VERSION 5.8 ;
BUSBITCHARS "[]" ;
DIVIDERCHAR "/" ;
UNITS
    DATABASE MICRONS 1000 ;
END UNITS

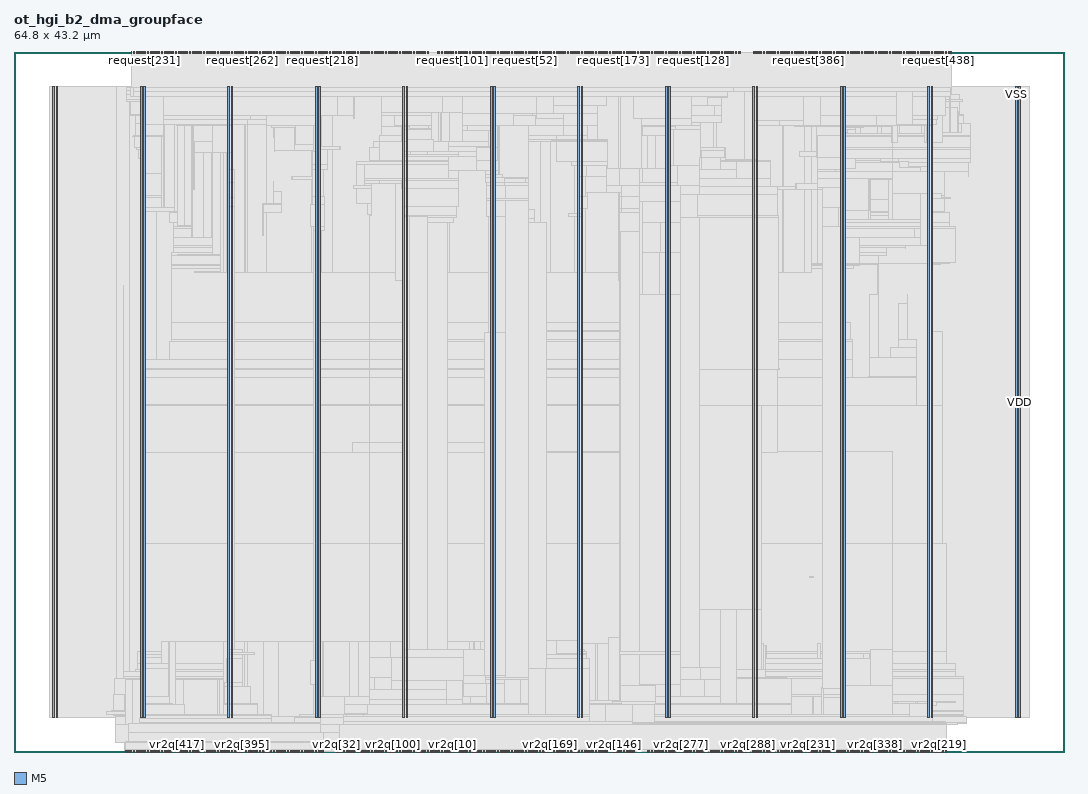
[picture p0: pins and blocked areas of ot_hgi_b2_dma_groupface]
MACRO ot_hgi_b2_dma_groupface
  FOREIGN ot_hgi_b2_dma_groupface 0 0 ;
  CLASS BLOCK ;
  SIZE 64.8 BY 43.2 ;
  PIN clk
    DIRECTION INPUT ;
    USE SIGNAL ;
    PORT
      LAYER M5 ;
        RECT  38.736 43.116 38.76 43.2 ;
    END
  END clk
  PIN request[0]
    DIRECTION INPUT ;
    USE SIGNAL ;
    PORT
      LAYER M5 ;
        RECT  38.832 43.116 38.856 43.2 ;
    END
  END request[0]
  PIN request[100]
    DIRECTION INPUT ;
    USE SIGNAL ;
    PORT
      LAYER M5 ;
        RECT  26.928 43.116 26.952 43.2 ;
    END
  END request[100]
  PIN request[101]
    DIRECTION INPUT ;
    USE SIGNAL ;
    PORT
      LAYER M5 ;
        RECT  27.024 43.116 27.048 43.2 ;
    END
  END request[101]
  PIN request[102]
    DIRECTION INPUT ;
    USE SIGNAL ;
    PORT
      LAYER M5 ;
        RECT  27.12 43.116 27.144 43.2 ;
    END
  END request[102]
  PIN request[103]
    DIRECTION INPUT ;
    USE SIGNAL ;
    PORT
      LAYER M5 ;
        RECT  27.216 43.116 27.24 43.2 ;
    END
  END request[103]
  PIN request[104]
    DIRECTION INPUT ;
    USE SIGNAL ;
    PORT
      LAYER M5 ;
        RECT  27.312 43.116 27.336 43.2 ;
    END
  END request[104]
  PIN request[105]
    DIRECTION INPUT ;
    USE SIGNAL ;
    PORT
      LAYER M5 ;
        RECT  27.408 43.116 27.432 43.2 ;
    END
  END request[105]
  PIN request[106]
    DIRECTION INPUT ;
    USE SIGNAL ;
    PORT
      LAYER M5 ;
        RECT  27.504 43.116 27.528 43.2 ;
    END
  END request[106]
  PIN request[107]
    DIRECTION INPUT ;
    USE SIGNAL ;
    PORT
      LAYER M5 ;
        RECT  27.6 43.116 27.624 43.2 ;
    END
  END request[107]
  PIN request[108]
    DIRECTION INPUT ;
    USE SIGNAL ;
    PORT
      LAYER M5 ;
        RECT  27.696 43.116 27.72 43.2 ;
    END
  END request[108]
  PIN request[109]
    DIRECTION INPUT ;
    USE SIGNAL ;
    PORT
      LAYER M5 ;
        RECT  27.792 43.116 27.816 43.2 ;
    END
  END request[109]
  PIN request[10]
    DIRECTION INPUT ;
    USE SIGNAL ;
    PORT
      LAYER M5 ;
        RECT  39.792 43.116 39.816 43.2 ;
    END
  END request[10]
  PIN request[110]
    DIRECTION INPUT ;
    USE SIGNAL ;
    PORT
      LAYER M5 ;
        RECT  27.888 43.116 27.912 43.2 ;
    END
  END request[110]
  PIN request[111]
    DIRECTION INPUT ;
    USE SIGNAL ;
    PORT
      LAYER M5 ;
        RECT  27.984 43.116 28.008 43.2 ;
    END
  END request[111]
  PIN request[112]
    DIRECTION INPUT ;
    USE SIGNAL ;
    PORT
      LAYER M5 ;
        RECT  28.08 43.116 28.104 43.2 ;
    END
  END request[112]
  PIN request[113]
    DIRECTION INPUT ;
    USE SIGNAL ;
    PORT
      LAYER M5 ;
        RECT  28.176 43.116 28.2 43.2 ;
    END
  END request[113]
  PIN request[114]
    DIRECTION INPUT ;
    USE SIGNAL ;
    PORT
      LAYER M5 ;
        RECT  28.272 43.116 28.296 43.2 ;
    END
  END request[114]
  PIN request[115]
    DIRECTION INPUT ;
    USE SIGNAL ;
    PORT
      LAYER M5 ;
        RECT  28.368 43.116 28.392 43.2 ;
    END
  END request[115]
  PIN request[116]
    DIRECTION INPUT ;
    USE SIGNAL ;
    PORT
      LAYER M5 ;
        RECT  28.464 43.116 28.488 43.2 ;
    END
  END request[116]
  PIN request[117]
    DIRECTION INPUT ;
    USE SIGNAL ;
    PORT
      LAYER M5 ;
        RECT  28.56 43.116 28.584 43.2 ;
    END
  END request[117]
  PIN request[118]
    DIRECTION INPUT ;
    USE SIGNAL ;
    PORT
      LAYER M5 ;
        RECT  28.656 43.116 28.68 43.2 ;
    END
  END request[118]
  PIN request[119]
    DIRECTION INPUT ;
    USE SIGNAL ;
    PORT
      LAYER M5 ;
        RECT  28.752 43.116 28.776 43.2 ;
    END
  END request[119]
  PIN request[11]
    DIRECTION INPUT ;
    USE SIGNAL ;
    PORT
      LAYER M5 ;
        RECT  39.888 43.116 39.912 43.2 ;
    END
  END request[11]
  PIN request[120]
    DIRECTION INPUT ;
    USE SIGNAL ;
    PORT
      LAYER M5 ;
        RECT  28.848 43.116 28.872 43.2 ;
    END
  END request[120]
  PIN request[121]
    DIRECTION INPUT ;
    USE SIGNAL ;
    PORT
      LAYER M5 ;
        RECT  28.944 43.116 28.968 43.2 ;
    END
  END request[121]
  PIN request[122]
    DIRECTION INPUT ;
    USE SIGNAL ;
    PORT
      LAYER M5 ;
        RECT  29.04 43.116 29.064 43.2 ;
    END
  END request[122]
  PIN request[123]
    DIRECTION INPUT ;
    USE SIGNAL ;
    PORT
      LAYER M5 ;
        RECT  29.136 43.116 29.16 43.2 ;
    END
  END request[123]
  PIN request[124]
    DIRECTION INPUT ;
    USE SIGNAL ;
    PORT
      LAYER M5 ;
        RECT  29.232 43.116 29.256 43.2 ;
    END
  END request[124]
  PIN request[125]
    DIRECTION INPUT ;
    USE SIGNAL ;
    PORT
      LAYER M5 ;
        RECT  29.328 43.116 29.352 43.2 ;
    END
  END request[125]
  PIN request[126]
    DIRECTION INPUT ;
    USE SIGNAL ;
    PORT
      LAYER M5 ;
        RECT  29.424 43.116 29.448 43.2 ;
    END
  END request[126]
  PIN request[127]
    DIRECTION INPUT ;
    USE SIGNAL ;
    PORT
      LAYER M5 ;
        RECT  41.808 43.116 41.832 43.2 ;
    END
  END request[127]
  PIN request[128]
    DIRECTION INPUT ;
    USE SIGNAL ;
    PORT
      LAYER M5 ;
        RECT  41.904 43.116 41.928 43.2 ;
    END
  END request[128]
  PIN request[129]
    DIRECTION INPUT ;
    USE SIGNAL ;
    PORT
      LAYER M5 ;
        RECT  42 43.116 42.024 43.2 ;
    END
  END request[129]
  PIN request[12]
    DIRECTION INPUT ;
    USE SIGNAL ;
    PORT
      LAYER M5 ;
        RECT  39.984 43.116 40.008 43.2 ;
    END
  END request[12]
  PIN request[130]
    DIRECTION INPUT ;
    USE SIGNAL ;
    PORT
      LAYER M5 ;
        RECT  42.096 43.116 42.12 43.2 ;
    END
  END request[130]
  PIN request[131]
    DIRECTION INPUT ;
    USE SIGNAL ;
    PORT
      LAYER M5 ;
        RECT  42.192 43.116 42.216 43.2 ;
    END
  END request[131]
  PIN request[132]
    DIRECTION INPUT ;
    USE SIGNAL ;
    PORT
      LAYER M5 ;
        RECT  42.288 43.116 42.312 43.2 ;
    END
  END request[132]
  PIN request[133]
    DIRECTION INPUT ;
    USE SIGNAL ;
    PORT
      LAYER M5 ;
        RECT  42.384 43.116 42.408 43.2 ;
    END
  END request[133]
  PIN request[134]
    DIRECTION INPUT ;
    USE SIGNAL ;
    PORT
      LAYER M5 ;
        RECT  42.48 43.116 42.504 43.2 ;
    END
  END request[134]
  PIN request[135]
    DIRECTION INPUT ;
    USE SIGNAL ;
    PORT
      LAYER M5 ;
        RECT  42.576 43.116 42.6 43.2 ;
    END
  END request[135]
  PIN request[136]
    DIRECTION INPUT ;
    USE SIGNAL ;
    PORT
      LAYER M5 ;
        RECT  42.672 43.116 42.696 43.2 ;
    END
  END request[136]
  PIN request[137]
    DIRECTION INPUT ;
    USE SIGNAL ;
    PORT
      LAYER M5 ;
        RECT  42.768 43.116 42.792 43.2 ;
    END
  END request[137]
  PIN request[138]
    DIRECTION INPUT ;
    USE SIGNAL ;
    PORT
      LAYER M5 ;
        RECT  42.864 43.116 42.888 43.2 ;
    END
  END request[138]
  PIN request[139]
    DIRECTION INPUT ;
    USE SIGNAL ;
    PORT
      LAYER M5 ;
        RECT  42.96 43.116 42.984 43.2 ;
    END
  END request[139]
  PIN request[13]
    DIRECTION INPUT ;
    USE SIGNAL ;
    PORT
      LAYER M5 ;
        RECT  40.08 43.116 40.104 43.2 ;
    END
  END request[13]
  PIN request[140]
    DIRECTION INPUT ;
    USE SIGNAL ;
    PORT
      LAYER M5 ;
        RECT  43.056 43.116 43.08 43.2 ;
    END
  END request[140]
  PIN request[141]
    DIRECTION INPUT ;
    USE SIGNAL ;
    PORT
      LAYER M5 ;
        RECT  43.152 43.116 43.176 43.2 ;
    END
  END request[141]
  PIN request[142]
    DIRECTION INPUT ;
    USE SIGNAL ;
    PORT
      LAYER M5 ;
        RECT  43.248 43.116 43.272 43.2 ;
    END
  END request[142]
  PIN request[143]
    DIRECTION INPUT ;
    USE SIGNAL ;
    PORT
      LAYER M5 ;
        RECT  43.344 43.116 43.368 43.2 ;
    END
  END request[143]
  PIN request[144]
    DIRECTION INPUT ;
    USE SIGNAL ;
    PORT
      LAYER M5 ;
        RECT  43.44 43.116 43.464 43.2 ;
    END
  END request[144]
  PIN request[145]
    DIRECTION INPUT ;
    USE SIGNAL ;
    PORT
      LAYER M5 ;
        RECT  43.536 43.116 43.56 43.2 ;
    END
  END request[145]
  PIN request[146]
    DIRECTION INPUT ;
    USE SIGNAL ;
    PORT
      LAYER M5 ;
        RECT  43.632 43.116 43.656 43.2 ;
    END
  END request[146]
  PIN request[147]
    DIRECTION INPUT ;
    USE SIGNAL ;
    PORT
      LAYER M5 ;
        RECT  43.728 43.116 43.752 43.2 ;
    END
  END request[147]
  PIN request[148]
    DIRECTION INPUT ;
    USE SIGNAL ;
    PORT
      LAYER M5 ;
        RECT  43.824 43.116 43.848 43.2 ;
    END
  END request[148]
  PIN request[149]
    DIRECTION INPUT ;
    USE SIGNAL ;
    PORT
      LAYER M5 ;
        RECT  43.92 43.116 43.944 43.2 ;
    END
  END request[149]
  PIN request[14]
    DIRECTION INPUT ;
    USE SIGNAL ;
    PORT
      LAYER M5 ;
        RECT  40.176 43.116 40.2 43.2 ;
    END
  END request[14]
  PIN request[150]
    DIRECTION INPUT ;
    USE SIGNAL ;
    PORT
      LAYER M5 ;
        RECT  44.016 43.116 44.04 43.2 ;
    END
  END request[150]
  PIN request[151]
    DIRECTION INPUT ;
    USE SIGNAL ;
    PORT
      LAYER M5 ;
        RECT  44.112 43.116 44.136 43.2 ;
    END
  END request[151]
  PIN request[152]
    DIRECTION INPUT ;
    USE SIGNAL ;
    PORT
      LAYER M5 ;
        RECT  44.208 43.116 44.232 43.2 ;
    END
  END request[152]
  PIN request[153]
    DIRECTION INPUT ;
    USE SIGNAL ;
    PORT
      LAYER M5 ;
        RECT  44.304 43.116 44.328 43.2 ;
    END
  END request[153]
  PIN request[154]
    DIRECTION INPUT ;
    USE SIGNAL ;
    PORT
      LAYER M5 ;
        RECT  44.4 43.116 44.424 43.2 ;
    END
  END request[154]
  PIN request[155]
    DIRECTION INPUT ;
    USE SIGNAL ;
    PORT
      LAYER M5 ;
        RECT  44.496 43.116 44.52 43.2 ;
    END
  END request[155]
  PIN request[156]
    DIRECTION INPUT ;
    USE SIGNAL ;
    PORT
      LAYER M5 ;
        RECT  44.592 43.116 44.616 43.2 ;
    END
  END request[156]
  PIN request[157]
    DIRECTION INPUT ;
    USE SIGNAL ;
    PORT
      LAYER M5 ;
        RECT  44.688 43.116 44.712 43.2 ;
    END
  END request[157]
  PIN request[158]
    DIRECTION INPUT ;
    USE SIGNAL ;
    PORT
      LAYER M5 ;
        RECT  44.784 43.116 44.808 43.2 ;
    END
  END request[158]
  PIN request[159]
    DIRECTION INPUT ;
    USE SIGNAL ;
    PORT
      LAYER M5 ;
        RECT  35.664 43.116 35.688 43.2 ;
    END
  END request[159]
  PIN request[15]
    DIRECTION INPUT ;
    USE SIGNAL ;
    PORT
      LAYER M5 ;
        RECT  40.272 43.116 40.296 43.2 ;
    END
  END request[15]
  PIN request[160]
    DIRECTION INPUT ;
    USE SIGNAL ;
    PORT
      LAYER M5 ;
        RECT  35.76 43.116 35.784 43.2 ;
    END
  END request[160]
  PIN request[161]
    DIRECTION INPUT ;
    USE SIGNAL ;
    PORT
      LAYER M5 ;
        RECT  35.856 43.116 35.88 43.2 ;
    END
  END request[161]
  PIN request[162]
    DIRECTION INPUT ;
    USE SIGNAL ;
    PORT
      LAYER M5 ;
        RECT  35.952 43.116 35.976 43.2 ;
    END
  END request[162]
  PIN request[163]
    DIRECTION INPUT ;
    USE SIGNAL ;
    PORT
      LAYER M5 ;
        RECT  36.048 43.116 36.072 43.2 ;
    END
  END request[163]
  PIN request[164]
    DIRECTION INPUT ;
    USE SIGNAL ;
    PORT
      LAYER M5 ;
        RECT  36.144 43.116 36.168 43.2 ;
    END
  END request[164]
  PIN request[165]
    DIRECTION INPUT ;
    USE SIGNAL ;
    PORT
      LAYER M5 ;
        RECT  36.24 43.116 36.264 43.2 ;
    END
  END request[165]
  PIN request[166]
    DIRECTION INPUT ;
    USE SIGNAL ;
    PORT
      LAYER M5 ;
        RECT  36.336 43.116 36.36 43.2 ;
    END
  END request[166]
  PIN request[167]
    DIRECTION INPUT ;
    USE SIGNAL ;
    PORT
      LAYER M5 ;
        RECT  36.432 43.116 36.456 43.2 ;
    END
  END request[167]
  PIN request[168]
    DIRECTION INPUT ;
    USE SIGNAL ;
    PORT
      LAYER M5 ;
        RECT  36.528 43.116 36.552 43.2 ;
    END
  END request[168]
  PIN request[169]
    DIRECTION INPUT ;
    USE SIGNAL ;
    PORT
      LAYER M5 ;
        RECT  36.624 43.116 36.648 43.2 ;
    END
  END request[169]
  PIN request[16]
    DIRECTION INPUT ;
    USE SIGNAL ;
    PORT
      LAYER M5 ;
        RECT  40.368 43.116 40.392 43.2 ;
    END
  END request[16]
  PIN request[170]
    DIRECTION INPUT ;
    USE SIGNAL ;
    PORT
      LAYER M5 ;
        RECT  36.72 43.116 36.744 43.2 ;
    END
  END request[170]
  PIN request[171]
    DIRECTION INPUT ;
    USE SIGNAL ;
    PORT
      LAYER M5 ;
        RECT  36.816 43.116 36.84 43.2 ;
    END
  END request[171]
  PIN request[172]
    DIRECTION INPUT ;
    USE SIGNAL ;
    PORT
      LAYER M5 ;
        RECT  36.912 43.116 36.936 43.2 ;
    END
  END request[172]
  PIN request[173]
    DIRECTION INPUT ;
    USE SIGNAL ;
    PORT
      LAYER M5 ;
        RECT  37.008 43.116 37.032 43.2 ;
    END
  END request[173]
  PIN request[174]
    DIRECTION INPUT ;
    USE SIGNAL ;
    PORT
      LAYER M5 ;
        RECT  37.104 43.116 37.128 43.2 ;
    END
  END request[174]
  PIN request[175]
    DIRECTION INPUT ;
    USE SIGNAL ;
    PORT
      LAYER M5 ;
        RECT  37.2 43.116 37.224 43.2 ;
    END
  END request[175]
  PIN request[176]
    DIRECTION INPUT ;
    USE SIGNAL ;
    PORT
      LAYER M5 ;
        RECT  37.296 43.116 37.32 43.2 ;
    END
  END request[176]
  PIN request[177]
    DIRECTION INPUT ;
    USE SIGNAL ;
    PORT
      LAYER M5 ;
        RECT  37.392 43.116 37.416 43.2 ;
    END
  END request[177]
  PIN request[178]
    DIRECTION INPUT ;
    USE SIGNAL ;
    PORT
      LAYER M5 ;
        RECT  37.488 43.116 37.512 43.2 ;
    END
  END request[178]
  PIN request[179]
    DIRECTION INPUT ;
    USE SIGNAL ;
    PORT
      LAYER M5 ;
        RECT  37.584 43.116 37.608 43.2 ;
    END
  END request[179]
  PIN request[17]
    DIRECTION INPUT ;
    USE SIGNAL ;
    PORT
      LAYER M5 ;
        RECT  40.464 43.116 40.488 43.2 ;
    END
  END request[17]
  PIN request[180]
    DIRECTION INPUT ;
    USE SIGNAL ;
    PORT
      LAYER M5 ;
        RECT  37.68 43.116 37.704 43.2 ;
    END
  END request[180]
  PIN request[181]
    DIRECTION INPUT ;
    USE SIGNAL ;
    PORT
      LAYER M5 ;
        RECT  37.776 43.116 37.8 43.2 ;
    END
  END request[181]
  PIN request[182]
    DIRECTION INPUT ;
    USE SIGNAL ;
    PORT
      LAYER M5 ;
        RECT  37.872 43.116 37.896 43.2 ;
    END
  END request[182]
  PIN request[183]
    DIRECTION INPUT ;
    USE SIGNAL ;
    PORT
      LAYER M5 ;
        RECT  37.968 43.116 37.992 43.2 ;
    END
  END request[183]
  PIN request[184]
    DIRECTION INPUT ;
    USE SIGNAL ;
    PORT
      LAYER M5 ;
        RECT  38.064 43.116 38.088 43.2 ;
    END
  END request[184]
  PIN request[185]
    DIRECTION INPUT ;
    USE SIGNAL ;
    PORT
      LAYER M5 ;
        RECT  38.16 43.116 38.184 43.2 ;
    END
  END request[185]
  PIN request[186]
    DIRECTION INPUT ;
    USE SIGNAL ;
    PORT
      LAYER M5 ;
        RECT  38.256 43.116 38.28 43.2 ;
    END
  END request[186]
  PIN request[187]
    DIRECTION INPUT ;
    USE SIGNAL ;
    PORT
      LAYER M5 ;
        RECT  38.352 43.116 38.376 43.2 ;
    END
  END request[187]
  PIN request[188]
    DIRECTION INPUT ;
    USE SIGNAL ;
    PORT
      LAYER M5 ;
        RECT  38.448 43.116 38.472 43.2 ;
    END
  END request[188]
  PIN request[189]
    DIRECTION INPUT ;
    USE SIGNAL ;
    PORT
      LAYER M5 ;
        RECT  38.544 43.116 38.568 43.2 ;
    END
  END request[189]
  PIN request[18]
    DIRECTION INPUT ;
    USE SIGNAL ;
    PORT
      LAYER M5 ;
        RECT  40.56 43.116 40.584 43.2 ;
    END
  END request[18]
  PIN request[190]
    DIRECTION INPUT ;
    USE SIGNAL ;
    PORT
      LAYER M5 ;
        RECT  38.64 43.116 38.664 43.2 ;
    END
  END request[190]
  PIN request[191]
    DIRECTION INPUT ;
    USE SIGNAL ;
    PORT
      LAYER M5 ;
        RECT  16.464 43.116 16.488 43.2 ;
    END
  END request[191]
  PIN request[192]
    DIRECTION INPUT ;
    USE SIGNAL ;
    PORT
      LAYER M5 ;
        RECT  16.56 43.116 16.584 43.2 ;
    END
  END request[192]
  PIN request[193]
    DIRECTION INPUT ;
    USE SIGNAL ;
    PORT
      LAYER M5 ;
        RECT  16.656 43.116 16.68 43.2 ;
    END
  END request[193]
  PIN request[194]
    DIRECTION INPUT ;
    USE SIGNAL ;
    PORT
      LAYER M5 ;
        RECT  16.752 43.116 16.776 43.2 ;
    END
  END request[194]
  PIN request[195]
    DIRECTION INPUT ;
    USE SIGNAL ;
    PORT
      LAYER M5 ;
        RECT  16.848 43.116 16.872 43.2 ;
    END
  END request[195]
  PIN request[196]
    DIRECTION INPUT ;
    USE SIGNAL ;
    PORT
      LAYER M5 ;
        RECT  16.944 43.116 16.968 43.2 ;
    END
  END request[196]
  PIN request[197]
    DIRECTION INPUT ;
    USE SIGNAL ;
    PORT
      LAYER M5 ;
        RECT  17.04 43.116 17.064 43.2 ;
    END
  END request[197]
  PIN request[198]
    DIRECTION INPUT ;
    USE SIGNAL ;
    PORT
      LAYER M5 ;
        RECT  17.136 43.116 17.16 43.2 ;
    END
  END request[198]
  PIN request[199]
    DIRECTION INPUT ;
    USE SIGNAL ;
    PORT
      LAYER M5 ;
        RECT  17.232 43.116 17.256 43.2 ;
    END
  END request[199]
  PIN request[19]
    DIRECTION INPUT ;
    USE SIGNAL ;
    PORT
      LAYER M5 ;
        RECT  40.656 43.116 40.68 43.2 ;
    END
  END request[19]
  PIN request[1]
    DIRECTION INPUT ;
    USE SIGNAL ;
    PORT
      LAYER M5 ;
        RECT  38.928 43.116 38.952 43.2 ;
    END
  END request[1]
  PIN request[200]
    DIRECTION INPUT ;
    USE SIGNAL ;
    PORT
      LAYER M5 ;
        RECT  17.328 43.116 17.352 43.2 ;
    END
  END request[200]
  PIN request[201]
    DIRECTION INPUT ;
    USE SIGNAL ;
    PORT
      LAYER M5 ;
        RECT  17.424 43.116 17.448 43.2 ;
    END
  END request[201]
  PIN request[202]
    DIRECTION INPUT ;
    USE SIGNAL ;
    PORT
      LAYER M5 ;
        RECT  17.52 43.116 17.544 43.2 ;
    END
  END request[202]
  PIN request[203]
    DIRECTION INPUT ;
    USE SIGNAL ;
    PORT
      LAYER M5 ;
        RECT  17.616 43.116 17.64 43.2 ;
    END
  END request[203]
  PIN request[204]
    DIRECTION INPUT ;
    USE SIGNAL ;
    PORT
      LAYER M5 ;
        RECT  17.712 43.116 17.736 43.2 ;
    END
  END request[204]
  PIN request[205]
    DIRECTION INPUT ;
    USE SIGNAL ;
    PORT
      LAYER M5 ;
        RECT  17.808 43.116 17.832 43.2 ;
    END
  END request[205]
  PIN request[206]
    DIRECTION INPUT ;
    USE SIGNAL ;
    PORT
      LAYER M5 ;
        RECT  17.904 43.116 17.928 43.2 ;
    END
  END request[206]
  PIN request[207]
    DIRECTION INPUT ;
    USE SIGNAL ;
    PORT
      LAYER M5 ;
        RECT  18 43.116 18.024 43.2 ;
    END
  END request[207]
  PIN request[208]
    DIRECTION INPUT ;
    USE SIGNAL ;
    PORT
      LAYER M5 ;
        RECT  18.096 43.116 18.12 43.2 ;
    END
  END request[208]
  PIN request[209]
    DIRECTION INPUT ;
    USE SIGNAL ;
    PORT
      LAYER M5 ;
        RECT  18.192 43.116 18.216 43.2 ;
    END
  END request[209]
  PIN request[20]
    DIRECTION INPUT ;
    USE SIGNAL ;
    PORT
      LAYER M5 ;
        RECT  40.752 43.116 40.776 43.2 ;
    END
  END request[20]
  PIN request[210]
    DIRECTION INPUT ;
    USE SIGNAL ;
    PORT
      LAYER M5 ;
        RECT  18.288 43.116 18.312 43.2 ;
    END
  END request[210]
  PIN request[211]
    DIRECTION INPUT ;
    USE SIGNAL ;
    PORT
      LAYER M5 ;
        RECT  18.384 43.116 18.408 43.2 ;
    END
  END request[211]
  PIN request[212]
    DIRECTION INPUT ;
    USE SIGNAL ;
    PORT
      LAYER M5 ;
        RECT  18.48 43.116 18.504 43.2 ;
    END
  END request[212]
  PIN request[213]
    DIRECTION INPUT ;
    USE SIGNAL ;
    PORT
      LAYER M5 ;
        RECT  18.576 43.116 18.6 43.2 ;
    END
  END request[213]
  PIN request[214]
    DIRECTION INPUT ;
    USE SIGNAL ;
    PORT
      LAYER M5 ;
        RECT  18.672 43.116 18.696 43.2 ;
    END
  END request[214]
  PIN request[215]
    DIRECTION INPUT ;
    USE SIGNAL ;
    PORT
      LAYER M5 ;
        RECT  18.768 43.116 18.792 43.2 ;
    END
  END request[215]
  PIN request[216]
    DIRECTION INPUT ;
    USE SIGNAL ;
    PORT
      LAYER M5 ;
        RECT  18.864 43.116 18.888 43.2 ;
    END
  END request[216]
  PIN request[217]
    DIRECTION INPUT ;
    USE SIGNAL ;
    PORT
      LAYER M5 ;
        RECT  18.96 43.116 18.984 43.2 ;
    END
  END request[217]
  PIN request[218]
    DIRECTION INPUT ;
    USE SIGNAL ;
    PORT
      LAYER M5 ;
        RECT  19.056 43.116 19.08 43.2 ;
    END
  END request[218]
  PIN request[219]
    DIRECTION INPUT ;
    USE SIGNAL ;
    PORT
      LAYER M5 ;
        RECT  19.152 43.116 19.176 43.2 ;
    END
  END request[219]
  PIN request[21]
    DIRECTION INPUT ;
    USE SIGNAL ;
    PORT
      LAYER M5 ;
        RECT  40.848 43.116 40.872 43.2 ;
    END
  END request[21]
  PIN request[220]
    DIRECTION INPUT ;
    USE SIGNAL ;
    PORT
      LAYER M5 ;
        RECT  19.248 43.116 19.272 43.2 ;
    END
  END request[220]
  PIN request[221]
    DIRECTION INPUT ;
    USE SIGNAL ;
    PORT
      LAYER M5 ;
        RECT  19.344 43.116 19.368 43.2 ;
    END
  END request[221]
  PIN request[222]
    DIRECTION INPUT ;
    USE SIGNAL ;
    PORT
      LAYER M5 ;
        RECT  19.44 43.116 19.464 43.2 ;
    END
  END request[222]
  PIN request[223]
    DIRECTION INPUT ;
    USE SIGNAL ;
    PORT
      LAYER M5 ;
        RECT  7.248 43.116 7.272 43.2 ;
    END
  END request[223]
  PIN request[224]
    DIRECTION INPUT ;
    USE SIGNAL ;
    PORT
      LAYER M5 ;
        RECT  7.344 43.116 7.368 43.2 ;
    END
  END request[224]
  PIN request[225]
    DIRECTION INPUT ;
    USE SIGNAL ;
    PORT
      LAYER M5 ;
        RECT  7.44 43.116 7.464 43.2 ;
    END
  END request[225]
  PIN request[226]
    DIRECTION INPUT ;
    USE SIGNAL ;
    PORT
      LAYER M5 ;
        RECT  7.536 43.116 7.56 43.2 ;
    END
  END request[226]
  PIN request[227]
    DIRECTION INPUT ;
    USE SIGNAL ;
    PORT
      LAYER M5 ;
        RECT  7.632 43.116 7.656 43.2 ;
    END
  END request[227]
  PIN request[228]
    DIRECTION INPUT ;
    USE SIGNAL ;
    PORT
      LAYER M5 ;
        RECT  7.728 43.116 7.752 43.2 ;
    END
  END request[228]
  PIN request[229]
    DIRECTION INPUT ;
    USE SIGNAL ;
    PORT
      LAYER M5 ;
        RECT  7.824 43.116 7.848 43.2 ;
    END
  END request[229]
  PIN request[22]
    DIRECTION INPUT ;
    USE SIGNAL ;
    PORT
      LAYER M5 ;
        RECT  40.944 43.116 40.968 43.2 ;
    END
  END request[22]
  PIN request[230]
    DIRECTION INPUT ;
    USE SIGNAL ;
    PORT
      LAYER M5 ;
        RECT  7.92 43.116 7.944 43.2 ;
    END
  END request[230]
  PIN request[231]
    DIRECTION INPUT ;
    USE SIGNAL ;
    PORT
      LAYER M5 ;
        RECT  8.016 43.116 8.04 43.2 ;
    END
  END request[231]
  PIN request[232]
    DIRECTION INPUT ;
    USE SIGNAL ;
    PORT
      LAYER M5 ;
        RECT  8.112 43.116 8.136 43.2 ;
    END
  END request[232]
  PIN request[233]
    DIRECTION INPUT ;
    USE SIGNAL ;
    PORT
      LAYER M5 ;
        RECT  8.208 43.116 8.232 43.2 ;
    END
  END request[233]
  PIN request[234]
    DIRECTION INPUT ;
    USE SIGNAL ;
    PORT
      LAYER M5 ;
        RECT  8.304 43.116 8.328 43.2 ;
    END
  END request[234]
  PIN request[235]
    DIRECTION INPUT ;
    USE SIGNAL ;
    PORT
      LAYER M5 ;
        RECT  8.4 43.116 8.424 43.2 ;
    END
  END request[235]
  PIN request[236]
    DIRECTION INPUT ;
    USE SIGNAL ;
    PORT
      LAYER M5 ;
        RECT  8.496 43.116 8.52 43.2 ;
    END
  END request[236]
  PIN request[237]
    DIRECTION INPUT ;
    USE SIGNAL ;
    PORT
      LAYER M5 ;
        RECT  8.592 43.116 8.616 43.2 ;
    END
  END request[237]
  PIN request[238]
    DIRECTION INPUT ;
    USE SIGNAL ;
    PORT
      LAYER M5 ;
        RECT  8.688 43.116 8.712 43.2 ;
    END
  END request[238]
  PIN request[239]
    DIRECTION INPUT ;
    USE SIGNAL ;
    PORT
      LAYER M5 ;
        RECT  8.784 43.116 8.808 43.2 ;
    END
  END request[239]
  PIN request[23]
    DIRECTION INPUT ;
    USE SIGNAL ;
    PORT
      LAYER M5 ;
        RECT  41.04 43.116 41.064 43.2 ;
    END
  END request[23]
  PIN request[240]
    DIRECTION INPUT ;
    USE SIGNAL ;
    PORT
      LAYER M5 ;
        RECT  8.88 43.116 8.904 43.2 ;
    END
  END request[240]
  PIN request[241]
    DIRECTION INPUT ;
    USE SIGNAL ;
    PORT
      LAYER M5 ;
        RECT  8.976 43.116 9 43.2 ;
    END
  END request[241]
  PIN request[242]
    DIRECTION INPUT ;
    USE SIGNAL ;
    PORT
      LAYER M5 ;
        RECT  9.072 43.116 9.096 43.2 ;
    END
  END request[242]
  PIN request[243]
    DIRECTION INPUT ;
    USE SIGNAL ;
    PORT
      LAYER M5 ;
        RECT  9.168 43.116 9.192 43.2 ;
    END
  END request[243]
  PIN request[244]
    DIRECTION INPUT ;
    USE SIGNAL ;
    PORT
      LAYER M5 ;
        RECT  9.264 43.116 9.288 43.2 ;
    END
  END request[244]
  PIN request[245]
    DIRECTION INPUT ;
    USE SIGNAL ;
    PORT
      LAYER M5 ;
        RECT  9.36 43.116 9.384 43.2 ;
    END
  END request[245]
  PIN request[246]
    DIRECTION INPUT ;
    USE SIGNAL ;
    PORT
      LAYER M5 ;
        RECT  9.456 43.116 9.48 43.2 ;
    END
  END request[246]
  PIN request[247]
    DIRECTION INPUT ;
    USE SIGNAL ;
    PORT
      LAYER M5 ;
        RECT  9.552 43.116 9.576 43.2 ;
    END
  END request[247]
  PIN request[248]
    DIRECTION INPUT ;
    USE SIGNAL ;
    PORT
      LAYER M5 ;
        RECT  9.648 43.116 9.672 43.2 ;
    END
  END request[248]
  PIN request[249]
    DIRECTION INPUT ;
    USE SIGNAL ;
    PORT
      LAYER M5 ;
        RECT  9.744 43.116 9.768 43.2 ;
    END
  END request[249]
  PIN request[24]
    DIRECTION INPUT ;
    USE SIGNAL ;
    PORT
      LAYER M5 ;
        RECT  41.136 43.116 41.16 43.2 ;
    END
  END request[24]
  PIN request[250]
    DIRECTION INPUT ;
    USE SIGNAL ;
    PORT
      LAYER M5 ;
        RECT  9.84 43.116 9.864 43.2 ;
    END
  END request[250]
  PIN request[251]
    DIRECTION INPUT ;
    USE SIGNAL ;
    PORT
      LAYER M5 ;
        RECT  9.936 43.116 9.96 43.2 ;
    END
  END request[251]
  PIN request[252]
    DIRECTION INPUT ;
    USE SIGNAL ;
    PORT
      LAYER M5 ;
        RECT  10.032 43.116 10.056 43.2 ;
    END
  END request[252]
  PIN request[253]
    DIRECTION INPUT ;
    USE SIGNAL ;
    PORT
      LAYER M5 ;
        RECT  10.128 43.116 10.152 43.2 ;
    END
  END request[253]
  PIN request[254]
    DIRECTION INPUT ;
    USE SIGNAL ;
    PORT
      LAYER M5 ;
        RECT  10.224 43.116 10.248 43.2 ;
    END
  END request[254]
  PIN request[255]
    DIRECTION INPUT ;
    USE SIGNAL ;
    PORT
      LAYER M5 ;
        RECT  13.392 43.116 13.416 43.2 ;
    END
  END request[255]
  PIN request[256]
    DIRECTION INPUT ;
    USE SIGNAL ;
    PORT
      LAYER M5 ;
        RECT  13.488 43.116 13.512 43.2 ;
    END
  END request[256]
  PIN request[257]
    DIRECTION INPUT ;
    USE SIGNAL ;
    PORT
      LAYER M5 ;
        RECT  13.584 43.116 13.608 43.2 ;
    END
  END request[257]
  PIN request[258]
    DIRECTION INPUT ;
    USE SIGNAL ;
    PORT
      LAYER M5 ;
        RECT  13.68 43.116 13.704 43.2 ;
    END
  END request[258]
  PIN request[259]
    DIRECTION INPUT ;
    USE SIGNAL ;
    PORT
      LAYER M5 ;
        RECT  13.776 43.116 13.8 43.2 ;
    END
  END request[259]
  PIN request[25]
    DIRECTION INPUT ;
    USE SIGNAL ;
    PORT
      LAYER M5 ;
        RECT  41.232 43.116 41.256 43.2 ;
    END
  END request[25]
  PIN request[260]
    DIRECTION INPUT ;
    USE SIGNAL ;
    PORT
      LAYER M5 ;
        RECT  13.872 43.116 13.896 43.2 ;
    END
  END request[260]
  PIN request[261]
    DIRECTION INPUT ;
    USE SIGNAL ;
    PORT
      LAYER M5 ;
        RECT  13.968 43.116 13.992 43.2 ;
    END
  END request[261]
  PIN request[262]
    DIRECTION INPUT ;
    USE SIGNAL ;
    PORT
      LAYER M5 ;
        RECT  14.064 43.116 14.088 43.2 ;
    END
  END request[262]
  PIN request[263]
    DIRECTION INPUT ;
    USE SIGNAL ;
    PORT
      LAYER M5 ;
        RECT  14.16 43.116 14.184 43.2 ;
    END
  END request[263]
  PIN request[264]
    DIRECTION INPUT ;
    USE SIGNAL ;
    PORT
      LAYER M5 ;
        RECT  14.256 43.116 14.28 43.2 ;
    END
  END request[264]
  PIN request[265]
    DIRECTION INPUT ;
    USE SIGNAL ;
    PORT
      LAYER M5 ;
        RECT  14.352 43.116 14.376 43.2 ;
    END
  END request[265]
  PIN request[266]
    DIRECTION INPUT ;
    USE SIGNAL ;
    PORT
      LAYER M5 ;
        RECT  14.448 43.116 14.472 43.2 ;
    END
  END request[266]
  PIN request[267]
    DIRECTION INPUT ;
    USE SIGNAL ;
    PORT
      LAYER M5 ;
        RECT  14.544 43.116 14.568 43.2 ;
    END
  END request[267]
  PIN request[268]
    DIRECTION INPUT ;
    USE SIGNAL ;
    PORT
      LAYER M5 ;
        RECT  14.64 43.116 14.664 43.2 ;
    END
  END request[268]
  PIN request[269]
    DIRECTION INPUT ;
    USE SIGNAL ;
    PORT
      LAYER M5 ;
        RECT  14.736 43.116 14.76 43.2 ;
    END
  END request[269]
  PIN request[26]
    DIRECTION INPUT ;
    USE SIGNAL ;
    PORT
      LAYER M5 ;
        RECT  41.328 43.116 41.352 43.2 ;
    END
  END request[26]
  PIN request[270]
    DIRECTION INPUT ;
    USE SIGNAL ;
    PORT
      LAYER M5 ;
        RECT  14.832 43.116 14.856 43.2 ;
    END
  END request[270]
  PIN request[271]
    DIRECTION INPUT ;
    USE SIGNAL ;
    PORT
      LAYER M5 ;
        RECT  14.928 43.116 14.952 43.2 ;
    END
  END request[271]
  PIN request[272]
    DIRECTION INPUT ;
    USE SIGNAL ;
    PORT
      LAYER M5 ;
        RECT  15.024 43.116 15.048 43.2 ;
    END
  END request[272]
  PIN request[273]
    DIRECTION INPUT ;
    USE SIGNAL ;
    PORT
      LAYER M5 ;
        RECT  15.12 43.116 15.144 43.2 ;
    END
  END request[273]
  PIN request[274]
    DIRECTION INPUT ;
    USE SIGNAL ;
    PORT
      LAYER M5 ;
        RECT  15.216 43.116 15.24 43.2 ;
    END
  END request[274]
  PIN request[275]
    DIRECTION INPUT ;
    USE SIGNAL ;
    PORT
      LAYER M5 ;
        RECT  15.312 43.116 15.336 43.2 ;
    END
  END request[275]
  PIN request[276]
    DIRECTION INPUT ;
    USE SIGNAL ;
    PORT
      LAYER M5 ;
        RECT  15.408 43.116 15.432 43.2 ;
    END
  END request[276]
  PIN request[277]
    DIRECTION INPUT ;
    USE SIGNAL ;
    PORT
      LAYER M5 ;
        RECT  15.504 43.116 15.528 43.2 ;
    END
  END request[277]
  PIN request[278]
    DIRECTION INPUT ;
    USE SIGNAL ;
    PORT
      LAYER M5 ;
        RECT  15.6 43.116 15.624 43.2 ;
    END
  END request[278]
  PIN request[279]
    DIRECTION INPUT ;
    USE SIGNAL ;
    PORT
      LAYER M5 ;
        RECT  15.696 43.116 15.72 43.2 ;
    END
  END request[279]
  PIN request[27]
    DIRECTION INPUT ;
    USE SIGNAL ;
    PORT
      LAYER M5 ;
        RECT  41.424 43.116 41.448 43.2 ;
    END
  END request[27]
  PIN request[280]
    DIRECTION INPUT ;
    USE SIGNAL ;
    PORT
      LAYER M5 ;
        RECT  15.792 43.116 15.816 43.2 ;
    END
  END request[280]
  PIN request[281]
    DIRECTION INPUT ;
    USE SIGNAL ;
    PORT
      LAYER M5 ;
        RECT  15.888 43.116 15.912 43.2 ;
    END
  END request[281]
  PIN request[282]
    DIRECTION INPUT ;
    USE SIGNAL ;
    PORT
      LAYER M5 ;
        RECT  15.984 43.116 16.008 43.2 ;
    END
  END request[282]
  PIN request[283]
    DIRECTION INPUT ;
    USE SIGNAL ;
    PORT
      LAYER M5 ;
        RECT  16.08 43.116 16.104 43.2 ;
    END
  END request[283]
  PIN request[284]
    DIRECTION INPUT ;
    USE SIGNAL ;
    PORT
      LAYER M5 ;
        RECT  16.176 43.116 16.2 43.2 ;
    END
  END request[284]
  PIN request[285]
    DIRECTION INPUT ;
    USE SIGNAL ;
    PORT
      LAYER M5 ;
        RECT  16.272 43.116 16.296 43.2 ;
    END
  END request[285]
  PIN request[286]
    DIRECTION INPUT ;
    USE SIGNAL ;
    PORT
      LAYER M5 ;
        RECT  16.368 43.116 16.392 43.2 ;
    END
  END request[286]
  PIN request[287]
    DIRECTION INPUT ;
    USE SIGNAL ;
    PORT
      LAYER M5 ;
        RECT  10.32 43.116 10.344 43.2 ;
    END
  END request[287]
  PIN request[288]
    DIRECTION INPUT ;
    USE SIGNAL ;
    PORT
      LAYER M5 ;
        RECT  10.416 43.116 10.44 43.2 ;
    END
  END request[288]
  PIN request[289]
    DIRECTION INPUT ;
    USE SIGNAL ;
    PORT
      LAYER M5 ;
        RECT  10.512 43.116 10.536 43.2 ;
    END
  END request[289]
  PIN request[28]
    DIRECTION INPUT ;
    USE SIGNAL ;
    PORT
      LAYER M5 ;
        RECT  41.52 43.116 41.544 43.2 ;
    END
  END request[28]
  PIN request[290]
    DIRECTION INPUT ;
    USE SIGNAL ;
    PORT
      LAYER M5 ;
        RECT  10.608 43.116 10.632 43.2 ;
    END
  END request[290]
  PIN request[291]
    DIRECTION INPUT ;
    USE SIGNAL ;
    PORT
      LAYER M5 ;
        RECT  10.704 43.116 10.728 43.2 ;
    END
  END request[291]
  PIN request[292]
    DIRECTION INPUT ;
    USE SIGNAL ;
    PORT
      LAYER M5 ;
        RECT  10.8 43.116 10.824 43.2 ;
    END
  END request[292]
  PIN request[293]
    DIRECTION INPUT ;
    USE SIGNAL ;
    PORT
      LAYER M5 ;
        RECT  10.896 43.116 10.92 43.2 ;
    END
  END request[293]
  PIN request[294]
    DIRECTION INPUT ;
    USE SIGNAL ;
    PORT
      LAYER M5 ;
        RECT  10.992 43.116 11.016 43.2 ;
    END
  END request[294]
  PIN request[295]
    DIRECTION INPUT ;
    USE SIGNAL ;
    PORT
      LAYER M5 ;
        RECT  11.088 43.116 11.112 43.2 ;
    END
  END request[295]
  PIN request[296]
    DIRECTION INPUT ;
    USE SIGNAL ;
    PORT
      LAYER M5 ;
        RECT  11.184 43.116 11.208 43.2 ;
    END
  END request[296]
  PIN request[297]
    DIRECTION INPUT ;
    USE SIGNAL ;
    PORT
      LAYER M5 ;
        RECT  11.28 43.116 11.304 43.2 ;
    END
  END request[297]
  PIN request[298]
    DIRECTION INPUT ;
    USE SIGNAL ;
    PORT
      LAYER M5 ;
        RECT  11.376 43.116 11.4 43.2 ;
    END
  END request[298]
  PIN request[299]
    DIRECTION INPUT ;
    USE SIGNAL ;
    PORT
      LAYER M5 ;
        RECT  11.472 43.116 11.496 43.2 ;
    END
  END request[299]
  PIN request[29]
    DIRECTION INPUT ;
    USE SIGNAL ;
    PORT
      LAYER M5 ;
        RECT  41.616 43.116 41.64 43.2 ;
    END
  END request[29]
  PIN request[2]
    DIRECTION INPUT ;
    USE SIGNAL ;
    PORT
      LAYER M5 ;
        RECT  39.024 43.116 39.048 43.2 ;
    END
  END request[2]
  PIN request[300]
    DIRECTION INPUT ;
    USE SIGNAL ;
    PORT
      LAYER M5 ;
        RECT  11.568 43.116 11.592 43.2 ;
    END
  END request[300]
  PIN request[301]
    DIRECTION INPUT ;
    USE SIGNAL ;
    PORT
      LAYER M5 ;
        RECT  11.664 43.116 11.688 43.2 ;
    END
  END request[301]
  PIN request[302]
    DIRECTION INPUT ;
    USE SIGNAL ;
    PORT
      LAYER M5 ;
        RECT  11.76 43.116 11.784 43.2 ;
    END
  END request[302]
  PIN request[303]
    DIRECTION INPUT ;
    USE SIGNAL ;
    PORT
      LAYER M5 ;
        RECT  11.856 43.116 11.88 43.2 ;
    END
  END request[303]
  PIN request[304]
    DIRECTION INPUT ;
    USE SIGNAL ;
    PORT
      LAYER M5 ;
        RECT  11.952 43.116 11.976 43.2 ;
    END
  END request[304]
  PIN request[305]
    DIRECTION INPUT ;
    USE SIGNAL ;
    PORT
      LAYER M5 ;
        RECT  12.048 43.116 12.072 43.2 ;
    END
  END request[305]
  PIN request[306]
    DIRECTION INPUT ;
    USE SIGNAL ;
    PORT
      LAYER M5 ;
        RECT  12.144 43.116 12.168 43.2 ;
    END
  END request[306]
  PIN request[307]
    DIRECTION INPUT ;
    USE SIGNAL ;
    PORT
      LAYER M5 ;
        RECT  12.24 43.116 12.264 43.2 ;
    END
  END request[307]
  PIN request[308]
    DIRECTION INPUT ;
    USE SIGNAL ;
    PORT
      LAYER M5 ;
        RECT  12.336 43.116 12.36 43.2 ;
    END
  END request[308]
  PIN request[309]
    DIRECTION INPUT ;
    USE SIGNAL ;
    PORT
      LAYER M5 ;
        RECT  12.432 43.116 12.456 43.2 ;
    END
  END request[309]
  PIN request[30]
    DIRECTION INPUT ;
    USE SIGNAL ;
    PORT
      LAYER M5 ;
        RECT  41.712 43.116 41.736 43.2 ;
    END
  END request[30]
  PIN request[310]
    DIRECTION INPUT ;
    USE SIGNAL ;
    PORT
      LAYER M5 ;
        RECT  12.528 43.116 12.552 43.2 ;
    END
  END request[310]
  PIN request[311]
    DIRECTION INPUT ;
    USE SIGNAL ;
    PORT
      LAYER M5 ;
        RECT  12.624 43.116 12.648 43.2 ;
    END
  END request[311]
  PIN request[312]
    DIRECTION INPUT ;
    USE SIGNAL ;
    PORT
      LAYER M5 ;
        RECT  12.72 43.116 12.744 43.2 ;
    END
  END request[312]
  PIN request[313]
    DIRECTION INPUT ;
    USE SIGNAL ;
    PORT
      LAYER M5 ;
        RECT  12.816 43.116 12.84 43.2 ;
    END
  END request[313]
  PIN request[314]
    DIRECTION INPUT ;
    USE SIGNAL ;
    PORT
      LAYER M5 ;
        RECT  12.912 43.116 12.936 43.2 ;
    END
  END request[314]
  PIN request[315]
    DIRECTION INPUT ;
    USE SIGNAL ;
    PORT
      LAYER M5 ;
        RECT  13.008 43.116 13.032 43.2 ;
    END
  END request[315]
  PIN request[316]
    DIRECTION INPUT ;
    USE SIGNAL ;
    PORT
      LAYER M5 ;
        RECT  13.104 43.116 13.128 43.2 ;
    END
  END request[316]
  PIN request[317]
    DIRECTION INPUT ;
    USE SIGNAL ;
    PORT
      LAYER M5 ;
        RECT  13.2 43.116 13.224 43.2 ;
    END
  END request[317]
  PIN request[318]
    DIRECTION INPUT ;
    USE SIGNAL ;
    PORT
      LAYER M5 ;
        RECT  13.296 43.116 13.32 43.2 ;
    END
  END request[318]
  PIN request[319]
    DIRECTION INPUT ;
    USE SIGNAL ;
    PORT
      LAYER M5 ;
        RECT  19.536 43.116 19.56 43.2 ;
    END
  END request[319]
  PIN request[31]
    DIRECTION INPUT ;
    USE SIGNAL ;
    PORT
      LAYER M5 ;
        RECT  29.52 43.116 29.544 43.2 ;
    END
  END request[31]
  PIN request[320]
    DIRECTION INPUT ;
    USE SIGNAL ;
    PORT
      LAYER M5 ;
        RECT  19.632 43.116 19.656 43.2 ;
    END
  END request[320]
  PIN request[321]
    DIRECTION INPUT ;
    USE SIGNAL ;
    PORT
      LAYER M5 ;
        RECT  19.728 43.116 19.752 43.2 ;
    END
  END request[321]
  PIN request[322]
    DIRECTION INPUT ;
    USE SIGNAL ;
    PORT
      LAYER M5 ;
        RECT  19.824 43.116 19.848 43.2 ;
    END
  END request[322]
  PIN request[323]
    DIRECTION INPUT ;
    USE SIGNAL ;
    PORT
      LAYER M5 ;
        RECT  19.92 43.116 19.944 43.2 ;
    END
  END request[323]
  PIN request[324]
    DIRECTION INPUT ;
    USE SIGNAL ;
    PORT
      LAYER M5 ;
        RECT  20.016 43.116 20.04 43.2 ;
    END
  END request[324]
  PIN request[325]
    DIRECTION INPUT ;
    USE SIGNAL ;
    PORT
      LAYER M5 ;
        RECT  20.112 43.116 20.136 43.2 ;
    END
  END request[325]
  PIN request[326]
    DIRECTION INPUT ;
    USE SIGNAL ;
    PORT
      LAYER M5 ;
        RECT  20.208 43.116 20.232 43.2 ;
    END
  END request[326]
  PIN request[327]
    DIRECTION INPUT ;
    USE SIGNAL ;
    PORT
      LAYER M5 ;
        RECT  20.304 43.116 20.328 43.2 ;
    END
  END request[327]
  PIN request[328]
    DIRECTION INPUT ;
    USE SIGNAL ;
    PORT
      LAYER M5 ;
        RECT  20.4 43.116 20.424 43.2 ;
    END
  END request[328]
  PIN request[329]
    DIRECTION INPUT ;
    USE SIGNAL ;
    PORT
      LAYER M5 ;
        RECT  20.496 43.116 20.52 43.2 ;
    END
  END request[329]
  PIN request[32]
    DIRECTION INPUT ;
    USE SIGNAL ;
    PORT
      LAYER M5 ;
        RECT  29.616 43.116 29.64 43.2 ;
    END
  END request[32]
  PIN request[330]
    DIRECTION INPUT ;
    USE SIGNAL ;
    PORT
      LAYER M5 ;
        RECT  20.592 43.116 20.616 43.2 ;
    END
  END request[330]
  PIN request[331]
    DIRECTION INPUT ;
    USE SIGNAL ;
    PORT
      LAYER M5 ;
        RECT  20.688 43.116 20.712 43.2 ;
    END
  END request[331]
  PIN request[332]
    DIRECTION INPUT ;
    USE SIGNAL ;
    PORT
      LAYER M5 ;
        RECT  20.784 43.116 20.808 43.2 ;
    END
  END request[332]
  PIN request[333]
    DIRECTION INPUT ;
    USE SIGNAL ;
    PORT
      LAYER M5 ;
        RECT  20.88 43.116 20.904 43.2 ;
    END
  END request[333]
  PIN request[334]
    DIRECTION INPUT ;
    USE SIGNAL ;
    PORT
      LAYER M5 ;
        RECT  20.976 43.116 21 43.2 ;
    END
  END request[334]
  PIN request[335]
    DIRECTION INPUT ;
    USE SIGNAL ;
    PORT
      LAYER M5 ;
        RECT  21.072 43.116 21.096 43.2 ;
    END
  END request[335]
  PIN request[336]
    DIRECTION INPUT ;
    USE SIGNAL ;
    PORT
      LAYER M5 ;
        RECT  21.168 43.116 21.192 43.2 ;
    END
  END request[336]
  PIN request[337]
    DIRECTION INPUT ;
    USE SIGNAL ;
    PORT
      LAYER M5 ;
        RECT  21.264 43.116 21.288 43.2 ;
    END
  END request[337]
  PIN request[338]
    DIRECTION INPUT ;
    USE SIGNAL ;
    PORT
      LAYER M5 ;
        RECT  21.36 43.116 21.384 43.2 ;
    END
  END request[338]
  PIN request[339]
    DIRECTION INPUT ;
    USE SIGNAL ;
    PORT
      LAYER M5 ;
        RECT  21.456 43.116 21.48 43.2 ;
    END
  END request[339]
  PIN request[33]
    DIRECTION INPUT ;
    USE SIGNAL ;
    PORT
      LAYER M5 ;
        RECT  29.712 43.116 29.736 43.2 ;
    END
  END request[33]
  PIN request[340]
    DIRECTION INPUT ;
    USE SIGNAL ;
    PORT
      LAYER M5 ;
        RECT  21.552 43.116 21.576 43.2 ;
    END
  END request[340]
  PIN request[341]
    DIRECTION INPUT ;
    USE SIGNAL ;
    PORT
      LAYER M5 ;
        RECT  21.648 43.116 21.672 43.2 ;
    END
  END request[341]
  PIN request[342]
    DIRECTION INPUT ;
    USE SIGNAL ;
    PORT
      LAYER M5 ;
        RECT  21.744 43.116 21.768 43.2 ;
    END
  END request[342]
  PIN request[343]
    DIRECTION INPUT ;
    USE SIGNAL ;
    PORT
      LAYER M5 ;
        RECT  21.84 43.116 21.864 43.2 ;
    END
  END request[343]
  PIN request[344]
    DIRECTION INPUT ;
    USE SIGNAL ;
    PORT
      LAYER M5 ;
        RECT  21.936 43.116 21.96 43.2 ;
    END
  END request[344]
  PIN request[345]
    DIRECTION INPUT ;
    USE SIGNAL ;
    PORT
      LAYER M5 ;
        RECT  22.032 43.116 22.056 43.2 ;
    END
  END request[345]
  PIN request[346]
    DIRECTION INPUT ;
    USE SIGNAL ;
    PORT
      LAYER M5 ;
        RECT  22.128 43.116 22.152 43.2 ;
    END
  END request[346]
  PIN request[347]
    DIRECTION INPUT ;
    USE SIGNAL ;
    PORT
      LAYER M5 ;
        RECT  22.224 43.116 22.248 43.2 ;
    END
  END request[347]
  PIN request[348]
    DIRECTION INPUT ;
    USE SIGNAL ;
    PORT
      LAYER M5 ;
        RECT  22.32 43.116 22.344 43.2 ;
    END
  END request[348]
  PIN request[349]
    DIRECTION INPUT ;
    USE SIGNAL ;
    PORT
      LAYER M5 ;
        RECT  22.416 43.116 22.44 43.2 ;
    END
  END request[349]
  PIN request[34]
    DIRECTION INPUT ;
    USE SIGNAL ;
    PORT
      LAYER M5 ;
        RECT  29.808 43.116 29.832 43.2 ;
    END
  END request[34]
  PIN request[350]
    DIRECTION INPUT ;
    USE SIGNAL ;
    PORT
      LAYER M5 ;
        RECT  22.512 43.116 22.536 43.2 ;
    END
  END request[350]
  PIN request[351]
    DIRECTION INPUT ;
    USE SIGNAL ;
    PORT
      LAYER M5 ;
        RECT  22.608 43.116 22.632 43.2 ;
    END
  END request[351]
  PIN request[352]
    DIRECTION INPUT ;
    USE SIGNAL ;
    PORT
      LAYER M5 ;
        RECT  22.704 43.116 22.728 43.2 ;
    END
  END request[352]
  PIN request[353]
    DIRECTION INPUT ;
    USE SIGNAL ;
    PORT
      LAYER M5 ;
        RECT  22.8 43.116 22.824 43.2 ;
    END
  END request[353]
  PIN request[354]
    DIRECTION INPUT ;
    USE SIGNAL ;
    PORT
      LAYER M5 ;
        RECT  22.896 43.116 22.92 43.2 ;
    END
  END request[354]
  PIN request[355]
    DIRECTION INPUT ;
    USE SIGNAL ;
    PORT
      LAYER M5 ;
        RECT  22.992 43.116 23.016 43.2 ;
    END
  END request[355]
  PIN request[356]
    DIRECTION INPUT ;
    USE SIGNAL ;
    PORT
      LAYER M5 ;
        RECT  23.088 43.116 23.112 43.2 ;
    END
  END request[356]
  PIN request[357]
    DIRECTION INPUT ;
    USE SIGNAL ;
    PORT
      LAYER M5 ;
        RECT  23.184 43.116 23.208 43.2 ;
    END
  END request[357]
  PIN request[358]
    DIRECTION INPUT ;
    USE SIGNAL ;
    PORT
      LAYER M5 ;
        RECT  23.28 43.116 23.304 43.2 ;
    END
  END request[358]
  PIN request[359]
    DIRECTION INPUT ;
    USE SIGNAL ;
    PORT
      LAYER M5 ;
        RECT  23.376 43.116 23.4 43.2 ;
    END
  END request[359]
  PIN request[35]
    DIRECTION INPUT ;
    USE SIGNAL ;
    PORT
      LAYER M5 ;
        RECT  29.904 43.116 29.928 43.2 ;
    END
  END request[35]
  PIN request[360]
    DIRECTION INPUT ;
    USE SIGNAL ;
    PORT
      LAYER M5 ;
        RECT  23.472 43.116 23.496 43.2 ;
    END
  END request[360]
  PIN request[361]
    DIRECTION INPUT ;
    USE SIGNAL ;
    PORT
      LAYER M5 ;
        RECT  23.568 43.116 23.592 43.2 ;
    END
  END request[361]
  PIN request[362]
    DIRECTION INPUT ;
    USE SIGNAL ;
    PORT
      LAYER M5 ;
        RECT  23.664 43.116 23.688 43.2 ;
    END
  END request[362]
  PIN request[363]
    DIRECTION INPUT ;
    USE SIGNAL ;
    PORT
      LAYER M5 ;
        RECT  23.76 43.116 23.784 43.2 ;
    END
  END request[363]
  PIN request[364]
    DIRECTION INPUT ;
    USE SIGNAL ;
    PORT
      LAYER M5 ;
        RECT  23.856 43.116 23.88 43.2 ;
    END
  END request[364]
  PIN request[365]
    DIRECTION INPUT ;
    USE SIGNAL ;
    PORT
      LAYER M5 ;
        RECT  23.952 43.116 23.976 43.2 ;
    END
  END request[365]
  PIN request[366]
    DIRECTION INPUT ;
    USE SIGNAL ;
    PORT
      LAYER M5 ;
        RECT  24.048 43.116 24.072 43.2 ;
    END
  END request[366]
  PIN request[367]
    DIRECTION INPUT ;
    USE SIGNAL ;
    PORT
      LAYER M5 ;
        RECT  24.144 43.116 24.168 43.2 ;
    END
  END request[367]
  PIN request[368]
    DIRECTION INPUT ;
    USE SIGNAL ;
    PORT
      LAYER M5 ;
        RECT  24.24 43.116 24.264 43.2 ;
    END
  END request[368]
  PIN request[369]
    DIRECTION INPUT ;
    USE SIGNAL ;
    PORT
      LAYER M5 ;
        RECT  24.336 43.116 24.36 43.2 ;
    END
  END request[369]
  PIN request[36]
    DIRECTION INPUT ;
    USE SIGNAL ;
    PORT
      LAYER M5 ;
        RECT  30 43.116 30.024 43.2 ;
    END
  END request[36]
  PIN request[370]
    DIRECTION INPUT ;
    USE SIGNAL ;
    PORT
      LAYER M5 ;
        RECT  24.432 43.116 24.456 43.2 ;
    END
  END request[370]
  PIN request[371]
    DIRECTION INPUT ;
    USE SIGNAL ;
    PORT
      LAYER M5 ;
        RECT  24.528 43.116 24.552 43.2 ;
    END
  END request[371]
  PIN request[372]
    DIRECTION INPUT ;
    USE SIGNAL ;
    PORT
      LAYER M5 ;
        RECT  24.624 43.116 24.648 43.2 ;
    END
  END request[372]
  PIN request[373]
    DIRECTION INPUT ;
    USE SIGNAL ;
    PORT
      LAYER M5 ;
        RECT  24.72 43.116 24.744 43.2 ;
    END
  END request[373]
  PIN request[374]
    DIRECTION INPUT ;
    USE SIGNAL ;
    PORT
      LAYER M5 ;
        RECT  24.816 43.116 24.84 43.2 ;
    END
  END request[374]
  PIN request[375]
    DIRECTION INPUT ;
    USE SIGNAL ;
    PORT
      LAYER M5 ;
        RECT  24.912 43.116 24.936 43.2 ;
    END
  END request[375]
  PIN request[376]
    DIRECTION INPUT ;
    USE SIGNAL ;
    PORT
      LAYER M5 ;
        RECT  25.008 43.116 25.032 43.2 ;
    END
  END request[376]
  PIN request[377]
    DIRECTION INPUT ;
    USE SIGNAL ;
    PORT
      LAYER M5 ;
        RECT  25.104 43.116 25.128 43.2 ;
    END
  END request[377]
  PIN request[378]
    DIRECTION INPUT ;
    USE SIGNAL ;
    PORT
      LAYER M5 ;
        RECT  25.2 43.116 25.224 43.2 ;
    END
  END request[378]
  PIN request[379]
    DIRECTION INPUT ;
    USE SIGNAL ;
    PORT
      LAYER M5 ;
        RECT  25.296 43.116 25.32 43.2 ;
    END
  END request[379]
  PIN request[37]
    DIRECTION INPUT ;
    USE SIGNAL ;
    PORT
      LAYER M5 ;
        RECT  30.096 43.116 30.12 43.2 ;
    END
  END request[37]
  PIN request[380]
    DIRECTION INPUT ;
    USE SIGNAL ;
    PORT
      LAYER M5 ;
        RECT  25.392 43.116 25.416 43.2 ;
    END
  END request[380]
  PIN request[381]
    DIRECTION INPUT ;
    USE SIGNAL ;
    PORT
      LAYER M5 ;
        RECT  25.488 43.116 25.512 43.2 ;
    END
  END request[381]
  PIN request[382]
    DIRECTION INPUT ;
    USE SIGNAL ;
    PORT
      LAYER M5 ;
        RECT  25.584 43.116 25.608 43.2 ;
    END
  END request[382]
  PIN request[383]
    DIRECTION INPUT ;
    USE SIGNAL ;
    PORT
      LAYER M5 ;
        RECT  48.72 43.116 48.744 43.2 ;
    END
  END request[383]
  PIN request[384]
    DIRECTION INPUT ;
    USE SIGNAL ;
    PORT
      LAYER M5 ;
        RECT  48.816 43.116 48.84 43.2 ;
    END
  END request[384]
  PIN request[385]
    DIRECTION INPUT ;
    USE SIGNAL ;
    PORT
      LAYER M5 ;
        RECT  48.912 43.116 48.936 43.2 ;
    END
  END request[385]
  PIN request[386]
    DIRECTION INPUT ;
    USE SIGNAL ;
    PORT
      LAYER M5 ;
        RECT  49.008 43.116 49.032 43.2 ;
    END
  END request[386]
  PIN request[387]
    DIRECTION INPUT ;
    USE SIGNAL ;
    PORT
      LAYER M5 ;
        RECT  49.104 43.116 49.128 43.2 ;
    END
  END request[387]
  PIN request[388]
    DIRECTION INPUT ;
    USE SIGNAL ;
    PORT
      LAYER M5 ;
        RECT  49.2 43.116 49.224 43.2 ;
    END
  END request[388]
  PIN request[389]
    DIRECTION INPUT ;
    USE SIGNAL ;
    PORT
      LAYER M5 ;
        RECT  49.296 43.116 49.32 43.2 ;
    END
  END request[389]
  PIN request[38]
    DIRECTION INPUT ;
    USE SIGNAL ;
    PORT
      LAYER M5 ;
        RECT  30.192 43.116 30.216 43.2 ;
    END
  END request[38]
  PIN request[390]
    DIRECTION INPUT ;
    USE SIGNAL ;
    PORT
      LAYER M5 ;
        RECT  49.392 43.116 49.416 43.2 ;
    END
  END request[390]
  PIN request[391]
    DIRECTION INPUT ;
    USE SIGNAL ;
    PORT
      LAYER M5 ;
        RECT  49.488 43.116 49.512 43.2 ;
    END
  END request[391]
  PIN request[392]
    DIRECTION INPUT ;
    USE SIGNAL ;
    PORT
      LAYER M5 ;
        RECT  49.584 43.116 49.608 43.2 ;
    END
  END request[392]
  PIN request[393]
    DIRECTION INPUT ;
    USE SIGNAL ;
    PORT
      LAYER M5 ;
        RECT  49.68 43.116 49.704 43.2 ;
    END
  END request[393]
  PIN request[394]
    DIRECTION INPUT ;
    USE SIGNAL ;
    PORT
      LAYER M5 ;
        RECT  49.776 43.116 49.8 43.2 ;
    END
  END request[394]
  PIN request[395]
    DIRECTION INPUT ;
    USE SIGNAL ;
    PORT
      LAYER M5 ;
        RECT  49.872 43.116 49.896 43.2 ;
    END
  END request[395]
  PIN request[396]
    DIRECTION INPUT ;
    USE SIGNAL ;
    PORT
      LAYER M5 ;
        RECT  49.968 43.116 49.992 43.2 ;
    END
  END request[396]
  PIN request[397]
    DIRECTION INPUT ;
    USE SIGNAL ;
    PORT
      LAYER M5 ;
        RECT  50.064 43.116 50.088 43.2 ;
    END
  END request[397]
  PIN request[398]
    DIRECTION INPUT ;
    USE SIGNAL ;
    PORT
      LAYER M5 ;
        RECT  50.16 43.116 50.184 43.2 ;
    END
  END request[398]
  PIN request[399]
    DIRECTION INPUT ;
    USE SIGNAL ;
    PORT
      LAYER M5 ;
        RECT  50.256 43.116 50.28 43.2 ;
    END
  END request[399]
  PIN request[39]
    DIRECTION INPUT ;
    USE SIGNAL ;
    PORT
      LAYER M5 ;
        RECT  30.288 43.116 30.312 43.2 ;
    END
  END request[39]
  PIN request[3]
    DIRECTION INPUT ;
    USE SIGNAL ;
    PORT
      LAYER M5 ;
        RECT  39.12 43.116 39.144 43.2 ;
    END
  END request[3]
  PIN request[400]
    DIRECTION INPUT ;
    USE SIGNAL ;
    PORT
      LAYER M5 ;
        RECT  50.352 43.116 50.376 43.2 ;
    END
  END request[400]
  PIN request[401]
    DIRECTION INPUT ;
    USE SIGNAL ;
    PORT
      LAYER M5 ;
        RECT  50.448 43.116 50.472 43.2 ;
    END
  END request[401]
  PIN request[402]
    DIRECTION INPUT ;
    USE SIGNAL ;
    PORT
      LAYER M5 ;
        RECT  50.544 43.116 50.568 43.2 ;
    END
  END request[402]
  PIN request[403]
    DIRECTION INPUT ;
    USE SIGNAL ;
    PORT
      LAYER M5 ;
        RECT  50.64 43.116 50.664 43.2 ;
    END
  END request[403]
  PIN request[404]
    DIRECTION INPUT ;
    USE SIGNAL ;
    PORT
      LAYER M5 ;
        RECT  50.736 43.116 50.76 43.2 ;
    END
  END request[404]
  PIN request[405]
    DIRECTION INPUT ;
    USE SIGNAL ;
    PORT
      LAYER M5 ;
        RECT  50.832 43.116 50.856 43.2 ;
    END
  END request[405]
  PIN request[406]
    DIRECTION INPUT ;
    USE SIGNAL ;
    PORT
      LAYER M5 ;
        RECT  50.928 43.116 50.952 43.2 ;
    END
  END request[406]
  PIN request[407]
    DIRECTION INPUT ;
    USE SIGNAL ;
    PORT
      LAYER M5 ;
        RECT  51.024 43.116 51.048 43.2 ;
    END
  END request[407]
  PIN request[408]
    DIRECTION INPUT ;
    USE SIGNAL ;
    PORT
      LAYER M5 ;
        RECT  51.12 43.116 51.144 43.2 ;
    END
  END request[408]
  PIN request[409]
    DIRECTION INPUT ;
    USE SIGNAL ;
    PORT
      LAYER M5 ;
        RECT  51.216 43.116 51.24 43.2 ;
    END
  END request[409]
  PIN request[40]
    DIRECTION INPUT ;
    USE SIGNAL ;
    PORT
      LAYER M5 ;
        RECT  30.384 43.116 30.408 43.2 ;
    END
  END request[40]
  PIN request[410]
    DIRECTION INPUT ;
    USE SIGNAL ;
    PORT
      LAYER M5 ;
        RECT  51.312 43.116 51.336 43.2 ;
    END
  END request[410]
  PIN request[411]
    DIRECTION INPUT ;
    USE SIGNAL ;
    PORT
      LAYER M5 ;
        RECT  51.408 43.116 51.432 43.2 ;
    END
  END request[411]
  PIN request[412]
    DIRECTION INPUT ;
    USE SIGNAL ;
    PORT
      LAYER M5 ;
        RECT  51.504 43.116 51.528 43.2 ;
    END
  END request[412]
  PIN request[413]
    DIRECTION INPUT ;
    USE SIGNAL ;
    PORT
      LAYER M5 ;
        RECT  51.6 43.116 51.624 43.2 ;
    END
  END request[413]
  PIN request[414]
    DIRECTION INPUT ;
    USE SIGNAL ;
    PORT
      LAYER M5 ;
        RECT  51.696 43.116 51.72 43.2 ;
    END
  END request[414]
  PIN request[415]
    DIRECTION INPUT ;
    USE SIGNAL ;
    PORT
      LAYER M5 ;
        RECT  54.864 43.116 54.888 43.2 ;
    END
  END request[415]
  PIN request[416]
    DIRECTION INPUT ;
    USE SIGNAL ;
    PORT
      LAYER M5 ;
        RECT  54.96 43.116 54.984 43.2 ;
    END
  END request[416]
  PIN request[417]
    DIRECTION INPUT ;
    USE SIGNAL ;
    PORT
      LAYER M5 ;
        RECT  55.056 43.116 55.08 43.2 ;
    END
  END request[417]
  PIN request[418]
    DIRECTION INPUT ;
    USE SIGNAL ;
    PORT
      LAYER M5 ;
        RECT  55.152 43.116 55.176 43.2 ;
    END
  END request[418]
  PIN request[419]
    DIRECTION INPUT ;
    USE SIGNAL ;
    PORT
      LAYER M5 ;
        RECT  55.248 43.116 55.272 43.2 ;
    END
  END request[419]
  PIN request[41]
    DIRECTION INPUT ;
    USE SIGNAL ;
    PORT
      LAYER M5 ;
        RECT  30.48 43.116 30.504 43.2 ;
    END
  END request[41]
  PIN request[420]
    DIRECTION INPUT ;
    USE SIGNAL ;
    PORT
      LAYER M5 ;
        RECT  55.344 43.116 55.368 43.2 ;
    END
  END request[420]
  PIN request[421]
    DIRECTION INPUT ;
    USE SIGNAL ;
    PORT
      LAYER M5 ;
        RECT  55.44 43.116 55.464 43.2 ;
    END
  END request[421]
  PIN request[422]
    DIRECTION INPUT ;
    USE SIGNAL ;
    PORT
      LAYER M5 ;
        RECT  55.536 43.116 55.56 43.2 ;
    END
  END request[422]
  PIN request[423]
    DIRECTION INPUT ;
    USE SIGNAL ;
    PORT
      LAYER M5 ;
        RECT  55.632 43.116 55.656 43.2 ;
    END
  END request[423]
  PIN request[424]
    DIRECTION INPUT ;
    USE SIGNAL ;
    PORT
      LAYER M5 ;
        RECT  55.728 43.116 55.752 43.2 ;
    END
  END request[424]
  PIN request[425]
    DIRECTION INPUT ;
    USE SIGNAL ;
    PORT
      LAYER M5 ;
        RECT  55.824 43.116 55.848 43.2 ;
    END
  END request[425]
  PIN request[426]
    DIRECTION INPUT ;
    USE SIGNAL ;
    PORT
      LAYER M5 ;
        RECT  55.92 43.116 55.944 43.2 ;
    END
  END request[426]
  PIN request[427]
    DIRECTION INPUT ;
    USE SIGNAL ;
    PORT
      LAYER M5 ;
        RECT  56.016 43.116 56.04 43.2 ;
    END
  END request[427]
  PIN request[428]
    DIRECTION INPUT ;
    USE SIGNAL ;
    PORT
      LAYER M5 ;
        RECT  56.112 43.116 56.136 43.2 ;
    END
  END request[428]
  PIN request[429]
    DIRECTION INPUT ;
    USE SIGNAL ;
    PORT
      LAYER M5 ;
        RECT  56.208 43.116 56.232 43.2 ;
    END
  END request[429]
  PIN request[42]
    DIRECTION INPUT ;
    USE SIGNAL ;
    PORT
      LAYER M5 ;
        RECT  30.576 43.116 30.6 43.2 ;
    END
  END request[42]
  PIN request[430]
    DIRECTION INPUT ;
    USE SIGNAL ;
    PORT
      LAYER M5 ;
        RECT  56.304 43.116 56.328 43.2 ;
    END
  END request[430]
  PIN request[431]
    DIRECTION INPUT ;
    USE SIGNAL ;
    PORT
      LAYER M5 ;
        RECT  56.4 43.116 56.424 43.2 ;
    END
  END request[431]
  PIN request[432]
    DIRECTION INPUT ;
    USE SIGNAL ;
    PORT
      LAYER M5 ;
        RECT  56.496 43.116 56.52 43.2 ;
    END
  END request[432]
  PIN request[433]
    DIRECTION INPUT ;
    USE SIGNAL ;
    PORT
      LAYER M5 ;
        RECT  56.592 43.116 56.616 43.2 ;
    END
  END request[433]
  PIN request[434]
    DIRECTION INPUT ;
    USE SIGNAL ;
    PORT
      LAYER M5 ;
        RECT  56.688 43.116 56.712 43.2 ;
    END
  END request[434]
  PIN request[435]
    DIRECTION INPUT ;
    USE SIGNAL ;
    PORT
      LAYER M5 ;
        RECT  56.784 43.116 56.808 43.2 ;
    END
  END request[435]
  PIN request[436]
    DIRECTION INPUT ;
    USE SIGNAL ;
    PORT
      LAYER M5 ;
        RECT  56.88 43.116 56.904 43.2 ;
    END
  END request[436]
  PIN request[437]
    DIRECTION INPUT ;
    USE SIGNAL ;
    PORT
      LAYER M5 ;
        RECT  56.976 43.116 57 43.2 ;
    END
  END request[437]
  PIN request[438]
    DIRECTION INPUT ;
    USE SIGNAL ;
    PORT
      LAYER M5 ;
        RECT  57.072 43.116 57.096 43.2 ;
    END
  END request[438]
  PIN request[439]
    DIRECTION INPUT ;
    USE SIGNAL ;
    PORT
      LAYER M5 ;
        RECT  57.168 43.116 57.192 43.2 ;
    END
  END request[439]
  PIN request[43]
    DIRECTION INPUT ;
    USE SIGNAL ;
    PORT
      LAYER M5 ;
        RECT  30.672 43.116 30.696 43.2 ;
    END
  END request[43]
  PIN request[440]
    DIRECTION INPUT ;
    USE SIGNAL ;
    PORT
      LAYER M5 ;
        RECT  57.264 43.116 57.288 43.2 ;
    END
  END request[440]
  PIN request[441]
    DIRECTION INPUT ;
    USE SIGNAL ;
    PORT
      LAYER M5 ;
        RECT  57.36 43.116 57.384 43.2 ;
    END
  END request[441]
  PIN request[442]
    DIRECTION INPUT ;
    USE SIGNAL ;
    PORT
      LAYER M5 ;
        RECT  57.456 43.116 57.48 43.2 ;
    END
  END request[442]
  PIN request[443]
    DIRECTION INPUT ;
    USE SIGNAL ;
    PORT
      LAYER M5 ;
        RECT  57.552 43.116 57.576 43.2 ;
    END
  END request[443]
  PIN request[444]
    DIRECTION INPUT ;
    USE SIGNAL ;
    PORT
      LAYER M5 ;
        RECT  57.648 43.116 57.672 43.2 ;
    END
  END request[444]
  PIN request[445]
    DIRECTION INPUT ;
    USE SIGNAL ;
    PORT
      LAYER M5 ;
        RECT  57.744 43.116 57.768 43.2 ;
    END
  END request[445]
  PIN request[446]
    DIRECTION INPUT ;
    USE SIGNAL ;
    PORT
      LAYER M5 ;
        RECT  57.84 43.116 57.864 43.2 ;
    END
  END request[446]
  PIN request[447]
    DIRECTION INPUT ;
    USE SIGNAL ;
    PORT
      LAYER M5 ;
        RECT  45.648 43.116 45.672 43.2 ;
    END
  END request[447]
  PIN request[448]
    DIRECTION INPUT ;
    USE SIGNAL ;
    PORT
      LAYER M5 ;
        RECT  45.744 43.116 45.768 43.2 ;
    END
  END request[448]
  PIN request[449]
    DIRECTION INPUT ;
    USE SIGNAL ;
    PORT
      LAYER M5 ;
        RECT  45.84 43.116 45.864 43.2 ;
    END
  END request[449]
  PIN request[44]
    DIRECTION INPUT ;
    USE SIGNAL ;
    PORT
      LAYER M5 ;
        RECT  30.768 43.116 30.792 43.2 ;
    END
  END request[44]
  PIN request[450]
    DIRECTION INPUT ;
    USE SIGNAL ;
    PORT
      LAYER M5 ;
        RECT  45.936 43.116 45.96 43.2 ;
    END
  END request[450]
  PIN request[451]
    DIRECTION INPUT ;
    USE SIGNAL ;
    PORT
      LAYER M5 ;
        RECT  46.032 43.116 46.056 43.2 ;
    END
  END request[451]
  PIN request[452]
    DIRECTION INPUT ;
    USE SIGNAL ;
    PORT
      LAYER M5 ;
        RECT  46.128 43.116 46.152 43.2 ;
    END
  END request[452]
  PIN request[453]
    DIRECTION INPUT ;
    USE SIGNAL ;
    PORT
      LAYER M5 ;
        RECT  46.224 43.116 46.248 43.2 ;
    END
  END request[453]
  PIN request[454]
    DIRECTION INPUT ;
    USE SIGNAL ;
    PORT
      LAYER M5 ;
        RECT  46.32 43.116 46.344 43.2 ;
    END
  END request[454]
  PIN request[455]
    DIRECTION INPUT ;
    USE SIGNAL ;
    PORT
      LAYER M5 ;
        RECT  46.416 43.116 46.44 43.2 ;
    END
  END request[455]
  PIN request[456]
    DIRECTION INPUT ;
    USE SIGNAL ;
    PORT
      LAYER M5 ;
        RECT  46.512 43.116 46.536 43.2 ;
    END
  END request[456]
  PIN request[457]
    DIRECTION INPUT ;
    USE SIGNAL ;
    PORT
      LAYER M5 ;
        RECT  46.608 43.116 46.632 43.2 ;
    END
  END request[457]
  PIN request[458]
    DIRECTION INPUT ;
    USE SIGNAL ;
    PORT
      LAYER M5 ;
        RECT  46.704 43.116 46.728 43.2 ;
    END
  END request[458]
  PIN request[459]
    DIRECTION INPUT ;
    USE SIGNAL ;
    PORT
      LAYER M5 ;
        RECT  46.8 43.116 46.824 43.2 ;
    END
  END request[459]
  PIN request[45]
    DIRECTION INPUT ;
    USE SIGNAL ;
    PORT
      LAYER M5 ;
        RECT  30.864 43.116 30.888 43.2 ;
    END
  END request[45]
  PIN request[460]
    DIRECTION INPUT ;
    USE SIGNAL ;
    PORT
      LAYER M5 ;
        RECT  46.896 43.116 46.92 43.2 ;
    END
  END request[460]
  PIN request[461]
    DIRECTION INPUT ;
    USE SIGNAL ;
    PORT
      LAYER M5 ;
        RECT  46.992 43.116 47.016 43.2 ;
    END
  END request[461]
  PIN request[462]
    DIRECTION INPUT ;
    USE SIGNAL ;
    PORT
      LAYER M5 ;
        RECT  47.088 43.116 47.112 43.2 ;
    END
  END request[462]
  PIN request[463]
    DIRECTION INPUT ;
    USE SIGNAL ;
    PORT
      LAYER M5 ;
        RECT  47.184 43.116 47.208 43.2 ;
    END
  END request[463]
  PIN request[464]
    DIRECTION INPUT ;
    USE SIGNAL ;
    PORT
      LAYER M5 ;
        RECT  47.28 43.116 47.304 43.2 ;
    END
  END request[464]
  PIN request[465]
    DIRECTION INPUT ;
    USE SIGNAL ;
    PORT
      LAYER M5 ;
        RECT  47.376 43.116 47.4 43.2 ;
    END
  END request[465]
  PIN request[466]
    DIRECTION INPUT ;
    USE SIGNAL ;
    PORT
      LAYER M5 ;
        RECT  47.472 43.116 47.496 43.2 ;
    END
  END request[466]
  PIN request[467]
    DIRECTION INPUT ;
    USE SIGNAL ;
    PORT
      LAYER M5 ;
        RECT  47.568 43.116 47.592 43.2 ;
    END
  END request[467]
  PIN request[468]
    DIRECTION INPUT ;
    USE SIGNAL ;
    PORT
      LAYER M5 ;
        RECT  47.664 43.116 47.688 43.2 ;
    END
  END request[468]
  PIN request[469]
    DIRECTION INPUT ;
    USE SIGNAL ;
    PORT
      LAYER M5 ;
        RECT  47.76 43.116 47.784 43.2 ;
    END
  END request[469]
  PIN request[46]
    DIRECTION INPUT ;
    USE SIGNAL ;
    PORT
      LAYER M5 ;
        RECT  30.96 43.116 30.984 43.2 ;
    END
  END request[46]
  PIN request[470]
    DIRECTION INPUT ;
    USE SIGNAL ;
    PORT
      LAYER M5 ;
        RECT  47.856 43.116 47.88 43.2 ;
    END
  END request[470]
  PIN request[471]
    DIRECTION INPUT ;
    USE SIGNAL ;
    PORT
      LAYER M5 ;
        RECT  47.952 43.116 47.976 43.2 ;
    END
  END request[471]
  PIN request[472]
    DIRECTION INPUT ;
    USE SIGNAL ;
    PORT
      LAYER M5 ;
        RECT  48.048 43.116 48.072 43.2 ;
    END
  END request[472]
  PIN request[473]
    DIRECTION INPUT ;
    USE SIGNAL ;
    PORT
      LAYER M5 ;
        RECT  48.144 43.116 48.168 43.2 ;
    END
  END request[473]
  PIN request[474]
    DIRECTION INPUT ;
    USE SIGNAL ;
    PORT
      LAYER M5 ;
        RECT  48.24 43.116 48.264 43.2 ;
    END
  END request[474]
  PIN request[475]
    DIRECTION INPUT ;
    USE SIGNAL ;
    PORT
      LAYER M5 ;
        RECT  48.336 43.116 48.36 43.2 ;
    END
  END request[475]
  PIN request[476]
    DIRECTION INPUT ;
    USE SIGNAL ;
    PORT
      LAYER M5 ;
        RECT  48.432 43.116 48.456 43.2 ;
    END
  END request[476]
  PIN request[477]
    DIRECTION INPUT ;
    USE SIGNAL ;
    PORT
      LAYER M5 ;
        RECT  48.528 43.116 48.552 43.2 ;
    END
  END request[477]
  PIN request[478]
    DIRECTION INPUT ;
    USE SIGNAL ;
    PORT
      LAYER M5 ;
        RECT  48.624 43.116 48.648 43.2 ;
    END
  END request[478]
  PIN request[479]
    DIRECTION INPUT ;
    USE SIGNAL ;
    PORT
      LAYER M5 ;
        RECT  51.792 43.116 51.816 43.2 ;
    END
  END request[479]
  PIN request[47]
    DIRECTION INPUT ;
    USE SIGNAL ;
    PORT
      LAYER M5 ;
        RECT  31.056 43.116 31.08 43.2 ;
    END
  END request[47]
  PIN request[480]
    DIRECTION INPUT ;
    USE SIGNAL ;
    PORT
      LAYER M5 ;
        RECT  51.888 43.116 51.912 43.2 ;
    END
  END request[480]
  PIN request[481]
    DIRECTION INPUT ;
    USE SIGNAL ;
    PORT
      LAYER M5 ;
        RECT  51.984 43.116 52.008 43.2 ;
    END
  END request[481]
  PIN request[482]
    DIRECTION INPUT ;
    USE SIGNAL ;
    PORT
      LAYER M5 ;
        RECT  52.08 43.116 52.104 43.2 ;
    END
  END request[482]
  PIN request[483]
    DIRECTION INPUT ;
    USE SIGNAL ;
    PORT
      LAYER M5 ;
        RECT  52.176 43.116 52.2 43.2 ;
    END
  END request[483]
  PIN request[484]
    DIRECTION INPUT ;
    USE SIGNAL ;
    PORT
      LAYER M5 ;
        RECT  52.272 43.116 52.296 43.2 ;
    END
  END request[484]
  PIN request[485]
    DIRECTION INPUT ;
    USE SIGNAL ;
    PORT
      LAYER M5 ;
        RECT  52.368 43.116 52.392 43.2 ;
    END
  END request[485]
  PIN request[486]
    DIRECTION INPUT ;
    USE SIGNAL ;
    PORT
      LAYER M5 ;
        RECT  52.464 43.116 52.488 43.2 ;
    END
  END request[486]
  PIN request[487]
    DIRECTION INPUT ;
    USE SIGNAL ;
    PORT
      LAYER M5 ;
        RECT  52.56 43.116 52.584 43.2 ;
    END
  END request[487]
  PIN request[488]
    DIRECTION INPUT ;
    USE SIGNAL ;
    PORT
      LAYER M5 ;
        RECT  52.656 43.116 52.68 43.2 ;
    END
  END request[488]
  PIN request[489]
    DIRECTION INPUT ;
    USE SIGNAL ;
    PORT
      LAYER M5 ;
        RECT  52.752 43.116 52.776 43.2 ;
    END
  END request[489]
  PIN request[48]
    DIRECTION INPUT ;
    USE SIGNAL ;
    PORT
      LAYER M5 ;
        RECT  31.152 43.116 31.176 43.2 ;
    END
  END request[48]
  PIN request[490]
    DIRECTION INPUT ;
    USE SIGNAL ;
    PORT
      LAYER M5 ;
        RECT  52.848 43.116 52.872 43.2 ;
    END
  END request[490]
  PIN request[491]
    DIRECTION INPUT ;
    USE SIGNAL ;
    PORT
      LAYER M5 ;
        RECT  52.944 43.116 52.968 43.2 ;
    END
  END request[491]
  PIN request[492]
    DIRECTION INPUT ;
    USE SIGNAL ;
    PORT
      LAYER M5 ;
        RECT  53.04 43.116 53.064 43.2 ;
    END
  END request[492]
  PIN request[493]
    DIRECTION INPUT ;
    USE SIGNAL ;
    PORT
      LAYER M5 ;
        RECT  53.136 43.116 53.16 43.2 ;
    END
  END request[493]
  PIN request[494]
    DIRECTION INPUT ;
    USE SIGNAL ;
    PORT
      LAYER M5 ;
        RECT  53.232 43.116 53.256 43.2 ;
    END
  END request[494]
  PIN request[495]
    DIRECTION INPUT ;
    USE SIGNAL ;
    PORT
      LAYER M5 ;
        RECT  53.328 43.116 53.352 43.2 ;
    END
  END request[495]
  PIN request[496]
    DIRECTION INPUT ;
    USE SIGNAL ;
    PORT
      LAYER M5 ;
        RECT  53.424 43.116 53.448 43.2 ;
    END
  END request[496]
  PIN request[497]
    DIRECTION INPUT ;
    USE SIGNAL ;
    PORT
      LAYER M5 ;
        RECT  53.52 43.116 53.544 43.2 ;
    END
  END request[497]
  PIN request[498]
    DIRECTION INPUT ;
    USE SIGNAL ;
    PORT
      LAYER M5 ;
        RECT  53.616 43.116 53.64 43.2 ;
    END
  END request[498]
  PIN request[499]
    DIRECTION INPUT ;
    USE SIGNAL ;
    PORT
      LAYER M5 ;
        RECT  53.712 43.116 53.736 43.2 ;
    END
  END request[499]
  PIN request[49]
    DIRECTION INPUT ;
    USE SIGNAL ;
    PORT
      LAYER M5 ;
        RECT  31.248 43.116 31.272 43.2 ;
    END
  END request[49]
  PIN request[4]
    DIRECTION INPUT ;
    USE SIGNAL ;
    PORT
      LAYER M5 ;
        RECT  39.216 43.116 39.24 43.2 ;
    END
  END request[4]
  PIN request[500]
    DIRECTION INPUT ;
    USE SIGNAL ;
    PORT
      LAYER M5 ;
        RECT  53.808 43.116 53.832 43.2 ;
    END
  END request[500]
  PIN request[501]
    DIRECTION INPUT ;
    USE SIGNAL ;
    PORT
      LAYER M5 ;
        RECT  53.904 43.116 53.928 43.2 ;
    END
  END request[501]
  PIN request[502]
    DIRECTION INPUT ;
    USE SIGNAL ;
    PORT
      LAYER M5 ;
        RECT  54 43.116 54.024 43.2 ;
    END
  END request[502]
  PIN request[503]
    DIRECTION INPUT ;
    USE SIGNAL ;
    PORT
      LAYER M5 ;
        RECT  54.096 43.116 54.12 43.2 ;
    END
  END request[503]
  PIN request[504]
    DIRECTION INPUT ;
    USE SIGNAL ;
    PORT
      LAYER M5 ;
        RECT  54.192 43.116 54.216 43.2 ;
    END
  END request[504]
  PIN request[505]
    DIRECTION INPUT ;
    USE SIGNAL ;
    PORT
      LAYER M5 ;
        RECT  54.288 43.116 54.312 43.2 ;
    END
  END request[505]
  PIN request[506]
    DIRECTION INPUT ;
    USE SIGNAL ;
    PORT
      LAYER M5 ;
        RECT  54.384 43.116 54.408 43.2 ;
    END
  END request[506]
  PIN request[507]
    DIRECTION INPUT ;
    USE SIGNAL ;
    PORT
      LAYER M5 ;
        RECT  54.48 43.116 54.504 43.2 ;
    END
  END request[507]
  PIN request[508]
    DIRECTION INPUT ;
    USE SIGNAL ;
    PORT
      LAYER M5 ;
        RECT  54.576 43.116 54.6 43.2 ;
    END
  END request[508]
  PIN request[509]
    DIRECTION INPUT ;
    USE SIGNAL ;
    PORT
      LAYER M5 ;
        RECT  54.672 43.116 54.696 43.2 ;
    END
  END request[509]
  PIN request[50]
    DIRECTION INPUT ;
    USE SIGNAL ;
    PORT
      LAYER M5 ;
        RECT  31.344 43.116 31.368 43.2 ;
    END
  END request[50]
  PIN request[510]
    DIRECTION INPUT ;
    USE SIGNAL ;
    PORT
      LAYER M5 ;
        RECT  54.768 43.116 54.792 43.2 ;
    END
  END request[510]
  PIN request[511]
    DIRECTION INPUT ;
    USE SIGNAL ;
    PORT
      LAYER M5 ;
        RECT  26.16 43.116 26.184 43.2 ;
    END
  END request[511]
  PIN request[512]
    DIRECTION INPUT ;
    USE SIGNAL ;
    PORT
      LAYER M5 ;
        RECT  26.256 43.116 26.28 43.2 ;
    END
  END request[512]
  PIN request[51]
    DIRECTION INPUT ;
    USE SIGNAL ;
    PORT
      LAYER M5 ;
        RECT  31.44 43.116 31.464 43.2 ;
    END
  END request[51]
  PIN request[52]
    DIRECTION INPUT ;
    USE SIGNAL ;
    PORT
      LAYER M5 ;
        RECT  31.536 43.116 31.56 43.2 ;
    END
  END request[52]
  PIN request[53]
    DIRECTION INPUT ;
    USE SIGNAL ;
    PORT
      LAYER M5 ;
        RECT  31.632 43.116 31.656 43.2 ;
    END
  END request[53]
  PIN request[54]
    DIRECTION INPUT ;
    USE SIGNAL ;
    PORT
      LAYER M5 ;
        RECT  31.728 43.116 31.752 43.2 ;
    END
  END request[54]
  PIN request[55]
    DIRECTION INPUT ;
    USE SIGNAL ;
    PORT
      LAYER M5 ;
        RECT  31.824 43.116 31.848 43.2 ;
    END
  END request[55]
  PIN request[56]
    DIRECTION INPUT ;
    USE SIGNAL ;
    PORT
      LAYER M5 ;
        RECT  31.92 43.116 31.944 43.2 ;
    END
  END request[56]
  PIN request[57]
    DIRECTION INPUT ;
    USE SIGNAL ;
    PORT
      LAYER M5 ;
        RECT  32.016 43.116 32.04 43.2 ;
    END
  END request[57]
  PIN request[58]
    DIRECTION INPUT ;
    USE SIGNAL ;
    PORT
      LAYER M5 ;
        RECT  32.112 43.116 32.136 43.2 ;
    END
  END request[58]
  PIN request[59]
    DIRECTION INPUT ;
    USE SIGNAL ;
    PORT
      LAYER M5 ;
        RECT  32.208 43.116 32.232 43.2 ;
    END
  END request[59]
  PIN request[5]
    DIRECTION INPUT ;
    USE SIGNAL ;
    PORT
      LAYER M5 ;
        RECT  39.312 43.116 39.336 43.2 ;
    END
  END request[5]
  PIN request[60]
    DIRECTION INPUT ;
    USE SIGNAL ;
    PORT
      LAYER M5 ;
        RECT  32.304 43.116 32.328 43.2 ;
    END
  END request[60]
  PIN request[61]
    DIRECTION INPUT ;
    USE SIGNAL ;
    PORT
      LAYER M5 ;
        RECT  32.4 43.116 32.424 43.2 ;
    END
  END request[61]
  PIN request[62]
    DIRECTION INPUT ;
    USE SIGNAL ;
    PORT
      LAYER M5 ;
        RECT  32.496 43.116 32.52 43.2 ;
    END
  END request[62]
  PIN request[63]
    DIRECTION INPUT ;
    USE SIGNAL ;
    PORT
      LAYER M5 ;
        RECT  32.592 43.116 32.616 43.2 ;
    END
  END request[63]
  PIN request[64]
    DIRECTION INPUT ;
    USE SIGNAL ;
    PORT
      LAYER M5 ;
        RECT  32.688 43.116 32.712 43.2 ;
    END
  END request[64]
  PIN request[65]
    DIRECTION INPUT ;
    USE SIGNAL ;
    PORT
      LAYER M5 ;
        RECT  32.784 43.116 32.808 43.2 ;
    END
  END request[65]
  PIN request[66]
    DIRECTION INPUT ;
    USE SIGNAL ;
    PORT
      LAYER M5 ;
        RECT  32.88 43.116 32.904 43.2 ;
    END
  END request[66]
  PIN request[67]
    DIRECTION INPUT ;
    USE SIGNAL ;
    PORT
      LAYER M5 ;
        RECT  32.976 43.116 33 43.2 ;
    END
  END request[67]
  PIN request[68]
    DIRECTION INPUT ;
    USE SIGNAL ;
    PORT
      LAYER M5 ;
        RECT  33.072 43.116 33.096 43.2 ;
    END
  END request[68]
  PIN request[69]
    DIRECTION INPUT ;
    USE SIGNAL ;
    PORT
      LAYER M5 ;
        RECT  33.168 43.116 33.192 43.2 ;
    END
  END request[69]
  PIN request[6]
    DIRECTION INPUT ;
    USE SIGNAL ;
    PORT
      LAYER M5 ;
        RECT  39.408 43.116 39.432 43.2 ;
    END
  END request[6]
  PIN request[70]
    DIRECTION INPUT ;
    USE SIGNAL ;
    PORT
      LAYER M5 ;
        RECT  33.264 43.116 33.288 43.2 ;
    END
  END request[70]
  PIN request[71]
    DIRECTION INPUT ;
    USE SIGNAL ;
    PORT
      LAYER M5 ;
        RECT  33.36 43.116 33.384 43.2 ;
    END
  END request[71]
  PIN request[72]
    DIRECTION INPUT ;
    USE SIGNAL ;
    PORT
      LAYER M5 ;
        RECT  33.456 43.116 33.48 43.2 ;
    END
  END request[72]
  PIN request[73]
    DIRECTION INPUT ;
    USE SIGNAL ;
    PORT
      LAYER M5 ;
        RECT  33.552 43.116 33.576 43.2 ;
    END
  END request[73]
  PIN request[74]
    DIRECTION INPUT ;
    USE SIGNAL ;
    PORT
      LAYER M5 ;
        RECT  33.648 43.116 33.672 43.2 ;
    END
  END request[74]
  PIN request[75]
    DIRECTION INPUT ;
    USE SIGNAL ;
    PORT
      LAYER M5 ;
        RECT  33.744 43.116 33.768 43.2 ;
    END
  END request[75]
  PIN request[76]
    DIRECTION INPUT ;
    USE SIGNAL ;
    PORT
      LAYER M5 ;
        RECT  33.84 43.116 33.864 43.2 ;
    END
  END request[76]
  PIN request[77]
    DIRECTION INPUT ;
    USE SIGNAL ;
    PORT
      LAYER M5 ;
        RECT  33.936 43.116 33.96 43.2 ;
    END
  END request[77]
  PIN request[78]
    DIRECTION INPUT ;
    USE SIGNAL ;
    PORT
      LAYER M5 ;
        RECT  34.032 43.116 34.056 43.2 ;
    END
  END request[78]
  PIN request[79]
    DIRECTION INPUT ;
    USE SIGNAL ;
    PORT
      LAYER M5 ;
        RECT  34.128 43.116 34.152 43.2 ;
    END
  END request[79]
  PIN request[7]
    DIRECTION INPUT ;
    USE SIGNAL ;
    PORT
      LAYER M5 ;
        RECT  39.504 43.116 39.528 43.2 ;
    END
  END request[7]
  PIN request[80]
    DIRECTION INPUT ;
    USE SIGNAL ;
    PORT
      LAYER M5 ;
        RECT  34.224 43.116 34.248 43.2 ;
    END
  END request[80]
  PIN request[81]
    DIRECTION INPUT ;
    USE SIGNAL ;
    PORT
      LAYER M5 ;
        RECT  34.32 43.116 34.344 43.2 ;
    END
  END request[81]
  PIN request[82]
    DIRECTION INPUT ;
    USE SIGNAL ;
    PORT
      LAYER M5 ;
        RECT  34.416 43.116 34.44 43.2 ;
    END
  END request[82]
  PIN request[83]
    DIRECTION INPUT ;
    USE SIGNAL ;
    PORT
      LAYER M5 ;
        RECT  34.512 43.116 34.536 43.2 ;
    END
  END request[83]
  PIN request[84]
    DIRECTION INPUT ;
    USE SIGNAL ;
    PORT
      LAYER M5 ;
        RECT  34.608 43.116 34.632 43.2 ;
    END
  END request[84]
  PIN request[85]
    DIRECTION INPUT ;
    USE SIGNAL ;
    PORT
      LAYER M5 ;
        RECT  34.704 43.116 34.728 43.2 ;
    END
  END request[85]
  PIN request[86]
    DIRECTION INPUT ;
    USE SIGNAL ;
    PORT
      LAYER M5 ;
        RECT  34.8 43.116 34.824 43.2 ;
    END
  END request[86]
  PIN request[87]
    DIRECTION INPUT ;
    USE SIGNAL ;
    PORT
      LAYER M5 ;
        RECT  34.896 43.116 34.92 43.2 ;
    END
  END request[87]
  PIN request[88]
    DIRECTION INPUT ;
    USE SIGNAL ;
    PORT
      LAYER M5 ;
        RECT  34.992 43.116 35.016 43.2 ;
    END
  END request[88]
  PIN request[89]
    DIRECTION INPUT ;
    USE SIGNAL ;
    PORT
      LAYER M5 ;
        RECT  35.088 43.116 35.112 43.2 ;
    END
  END request[89]
  PIN request[8]
    DIRECTION INPUT ;
    USE SIGNAL ;
    PORT
      LAYER M5 ;
        RECT  39.6 43.116 39.624 43.2 ;
    END
  END request[8]
  PIN request[90]
    DIRECTION INPUT ;
    USE SIGNAL ;
    PORT
      LAYER M5 ;
        RECT  35.184 43.116 35.208 43.2 ;
    END
  END request[90]
  PIN request[91]
    DIRECTION INPUT ;
    USE SIGNAL ;
    PORT
      LAYER M5 ;
        RECT  35.28 43.116 35.304 43.2 ;
    END
  END request[91]
  PIN request[92]
    DIRECTION INPUT ;
    USE SIGNAL ;
    PORT
      LAYER M5 ;
        RECT  35.376 43.116 35.4 43.2 ;
    END
  END request[92]
  PIN request[93]
    DIRECTION INPUT ;
    USE SIGNAL ;
    PORT
      LAYER M5 ;
        RECT  35.472 43.116 35.496 43.2 ;
    END
  END request[93]
  PIN request[94]
    DIRECTION INPUT ;
    USE SIGNAL ;
    PORT
      LAYER M5 ;
        RECT  35.568 43.116 35.592 43.2 ;
    END
  END request[94]
  PIN request[95]
    DIRECTION INPUT ;
    USE SIGNAL ;
    PORT
      LAYER M5 ;
        RECT  26.448 43.116 26.472 43.2 ;
    END
  END request[95]
  PIN request[96]
    DIRECTION INPUT ;
    USE SIGNAL ;
    PORT
      LAYER M5 ;
        RECT  26.544 43.116 26.568 43.2 ;
    END
  END request[96]
  PIN request[97]
    DIRECTION INPUT ;
    USE SIGNAL ;
    PORT
      LAYER M5 ;
        RECT  26.64 43.116 26.664 43.2 ;
    END
  END request[97]
  PIN request[98]
    DIRECTION INPUT ;
    USE SIGNAL ;
    PORT
      LAYER M5 ;
        RECT  26.736 43.116 26.76 43.2 ;
    END
  END request[98]
  PIN request[99]
    DIRECTION INPUT ;
    USE SIGNAL ;
    PORT
      LAYER M5 ;
        RECT  26.832 43.116 26.856 43.2 ;
    END
  END request[99]
  PIN request[9]
    DIRECTION INPUT ;
    USE SIGNAL ;
    PORT
      LAYER M5 ;
        RECT  39.696 43.116 39.72 43.2 ;
    END
  END request[9]
  PIN rst_n
    DIRECTION INPUT ;
    USE SIGNAL ;
    PORT
      LAYER M5 ;
        RECT  26.352 43.116 26.376 43.2 ;
    END
  END rst_n
  PIN vr2q[0]
    DIRECTION OUTPUT ;
    USE SIGNAL ;
    PORT
      LAYER M5 ;
        RECT  26.064 0 26.088 0.084 ;
    END
  END vr2q[0]
  PIN vr2q[100]
    DIRECTION OUTPUT ;
    USE SIGNAL ;
    PORT
      LAYER M5 ;
        RECT  23.376 0 23.4 0.084 ;
    END
  END vr2q[100]
  PIN vr2q[101]
    DIRECTION OUTPUT ;
    USE SIGNAL ;
    PORT
      LAYER M5 ;
        RECT  23.472 0 23.496 0.084 ;
    END
  END vr2q[101]
  PIN vr2q[102]
    DIRECTION OUTPUT ;
    USE SIGNAL ;
    PORT
      LAYER M5 ;
        RECT  23.568 0 23.592 0.084 ;
    END
  END vr2q[102]
  PIN vr2q[103]
    DIRECTION OUTPUT ;
    USE SIGNAL ;
    PORT
      LAYER M5 ;
        RECT  23.664 0 23.688 0.084 ;
    END
  END vr2q[103]
  PIN vr2q[104]
    DIRECTION OUTPUT ;
    USE SIGNAL ;
    PORT
      LAYER M5 ;
        RECT  23.76 0 23.784 0.084 ;
    END
  END vr2q[104]
  PIN vr2q[105]
    DIRECTION OUTPUT ;
    USE SIGNAL ;
    PORT
      LAYER M5 ;
        RECT  23.856 0 23.88 0.084 ;
    END
  END vr2q[105]
  PIN vr2q[106]
    DIRECTION OUTPUT ;
    USE SIGNAL ;
    PORT
      LAYER M5 ;
        RECT  23.952 0 23.976 0.084 ;
    END
  END vr2q[106]
  PIN vr2q[107]
    DIRECTION OUTPUT ;
    USE SIGNAL ;
    PORT
      LAYER M5 ;
        RECT  24.048 0 24.072 0.084 ;
    END
  END vr2q[107]
  PIN vr2q[108]
    DIRECTION OUTPUT ;
    USE SIGNAL ;
    PORT
      LAYER M5 ;
        RECT  24.144 0 24.168 0.084 ;
    END
  END vr2q[108]
  PIN vr2q[109]
    DIRECTION OUTPUT ;
    USE SIGNAL ;
    PORT
      LAYER M5 ;
        RECT  24.24 0 24.264 0.084 ;
    END
  END vr2q[109]
  PIN vr2q[10]
    DIRECTION OUTPUT ;
    USE SIGNAL ;
    PORT
      LAYER M5 ;
        RECT  27.024 0 27.048 0.084 ;
    END
  END vr2q[10]
  PIN vr2q[110]
    DIRECTION OUTPUT ;
    USE SIGNAL ;
    PORT
      LAYER M5 ;
        RECT  24.336 0 24.36 0.084 ;
    END
  END vr2q[110]
  PIN vr2q[111]
    DIRECTION OUTPUT ;
    USE SIGNAL ;
    PORT
      LAYER M5 ;
        RECT  24.432 0 24.456 0.084 ;
    END
  END vr2q[111]
  PIN vr2q[112]
    DIRECTION OUTPUT ;
    USE SIGNAL ;
    PORT
      LAYER M5 ;
        RECT  24.528 0 24.552 0.084 ;
    END
  END vr2q[112]
  PIN vr2q[113]
    DIRECTION OUTPUT ;
    USE SIGNAL ;
    PORT
      LAYER M5 ;
        RECT  24.624 0 24.648 0.084 ;
    END
  END vr2q[113]
  PIN vr2q[114]
    DIRECTION OUTPUT ;
    USE SIGNAL ;
    PORT
      LAYER M5 ;
        RECT  24.72 0 24.744 0.084 ;
    END
  END vr2q[114]
  PIN vr2q[115]
    DIRECTION OUTPUT ;
    USE SIGNAL ;
    PORT
      LAYER M5 ;
        RECT  24.816 0 24.84 0.084 ;
    END
  END vr2q[115]
  PIN vr2q[116]
    DIRECTION OUTPUT ;
    USE SIGNAL ;
    PORT
      LAYER M5 ;
        RECT  24.912 0 24.936 0.084 ;
    END
  END vr2q[116]
  PIN vr2q[117]
    DIRECTION OUTPUT ;
    USE SIGNAL ;
    PORT
      LAYER M5 ;
        RECT  25.008 0 25.032 0.084 ;
    END
  END vr2q[117]
  PIN vr2q[118]
    DIRECTION OUTPUT ;
    USE SIGNAL ;
    PORT
      LAYER M5 ;
        RECT  25.104 0 25.128 0.084 ;
    END
  END vr2q[118]
  PIN vr2q[119]
    DIRECTION OUTPUT ;
    USE SIGNAL ;
    PORT
      LAYER M5 ;
        RECT  25.2 0 25.224 0.084 ;
    END
  END vr2q[119]
  PIN vr2q[11]
    DIRECTION OUTPUT ;
    USE SIGNAL ;
    PORT
      LAYER M5 ;
        RECT  27.12 0 27.144 0.084 ;
    END
  END vr2q[11]
  PIN vr2q[120]
    DIRECTION OUTPUT ;
    USE SIGNAL ;
    PORT
      LAYER M5 ;
        RECT  25.296 0 25.32 0.084 ;
    END
  END vr2q[120]
  PIN vr2q[121]
    DIRECTION OUTPUT ;
    USE SIGNAL ;
    PORT
      LAYER M5 ;
        RECT  25.392 0 25.416 0.084 ;
    END
  END vr2q[121]
  PIN vr2q[122]
    DIRECTION OUTPUT ;
    USE SIGNAL ;
    PORT
      LAYER M5 ;
        RECT  25.488 0 25.512 0.084 ;
    END
  END vr2q[122]
  PIN vr2q[123]
    DIRECTION OUTPUT ;
    USE SIGNAL ;
    PORT
      LAYER M5 ;
        RECT  25.584 0 25.608 0.084 ;
    END
  END vr2q[123]
  PIN vr2q[124]
    DIRECTION OUTPUT ;
    USE SIGNAL ;
    PORT
      LAYER M5 ;
        RECT  25.68 0 25.704 0.084 ;
    END
  END vr2q[124]
  PIN vr2q[125]
    DIRECTION OUTPUT ;
    USE SIGNAL ;
    PORT
      LAYER M5 ;
        RECT  25.776 0 25.8 0.084 ;
    END
  END vr2q[125]
  PIN vr2q[126]
    DIRECTION OUTPUT ;
    USE SIGNAL ;
    PORT
      LAYER M5 ;
        RECT  25.872 0 25.896 0.084 ;
    END
  END vr2q[126]
  PIN vr2q[127]
    DIRECTION OUTPUT ;
    USE SIGNAL ;
    PORT
      LAYER M5 ;
        RECT  25.968 0 25.992 0.084 ;
    END
  END vr2q[127]
  PIN vr2q[128]
    DIRECTION OUTPUT ;
    USE SIGNAL ;
    PORT
      LAYER M5 ;
        RECT  35.28 0 35.304 0.084 ;
    END
  END vr2q[128]
  PIN vr2q[129]
    DIRECTION OUTPUT ;
    USE SIGNAL ;
    PORT
      LAYER M5 ;
        RECT  35.376 0 35.4 0.084 ;
    END
  END vr2q[129]
  PIN vr2q[12]
    DIRECTION OUTPUT ;
    USE SIGNAL ;
    PORT
      LAYER M5 ;
        RECT  27.216 0 27.24 0.084 ;
    END
  END vr2q[12]
  PIN vr2q[130]
    DIRECTION OUTPUT ;
    USE SIGNAL ;
    PORT
      LAYER M5 ;
        RECT  35.472 0 35.496 0.084 ;
    END
  END vr2q[130]
  PIN vr2q[131]
    DIRECTION OUTPUT ;
    USE SIGNAL ;
    PORT
      LAYER M5 ;
        RECT  35.568 0 35.592 0.084 ;
    END
  END vr2q[131]
  PIN vr2q[132]
    DIRECTION OUTPUT ;
    USE SIGNAL ;
    PORT
      LAYER M5 ;
        RECT  35.664 0 35.688 0.084 ;
    END
  END vr2q[132]
  PIN vr2q[133]
    DIRECTION OUTPUT ;
    USE SIGNAL ;
    PORT
      LAYER M5 ;
        RECT  35.76 0 35.784 0.084 ;
    END
  END vr2q[133]
  PIN vr2q[134]
    DIRECTION OUTPUT ;
    USE SIGNAL ;
    PORT
      LAYER M5 ;
        RECT  35.856 0 35.88 0.084 ;
    END
  END vr2q[134]
  PIN vr2q[135]
    DIRECTION OUTPUT ;
    USE SIGNAL ;
    PORT
      LAYER M5 ;
        RECT  35.952 0 35.976 0.084 ;
    END
  END vr2q[135]
  PIN vr2q[136]
    DIRECTION OUTPUT ;
    USE SIGNAL ;
    PORT
      LAYER M5 ;
        RECT  36.048 0 36.072 0.084 ;
    END
  END vr2q[136]
  PIN vr2q[137]
    DIRECTION OUTPUT ;
    USE SIGNAL ;
    PORT
      LAYER M5 ;
        RECT  36.144 0 36.168 0.084 ;
    END
  END vr2q[137]
  PIN vr2q[138]
    DIRECTION OUTPUT ;
    USE SIGNAL ;
    PORT
      LAYER M5 ;
        RECT  36.24 0 36.264 0.084 ;
    END
  END vr2q[138]
  PIN vr2q[139]
    DIRECTION OUTPUT ;
    USE SIGNAL ;
    PORT
      LAYER M5 ;
        RECT  36.336 0 36.36 0.084 ;
    END
  END vr2q[139]
  PIN vr2q[13]
    DIRECTION OUTPUT ;
    USE SIGNAL ;
    PORT
      LAYER M5 ;
        RECT  27.312 0 27.336 0.084 ;
    END
  END vr2q[13]
  PIN vr2q[140]
    DIRECTION OUTPUT ;
    USE SIGNAL ;
    PORT
      LAYER M5 ;
        RECT  36.432 0 36.456 0.084 ;
    END
  END vr2q[140]
  PIN vr2q[141]
    DIRECTION OUTPUT ;
    USE SIGNAL ;
    PORT
      LAYER M5 ;
        RECT  36.528 0 36.552 0.084 ;
    END
  END vr2q[141]
  PIN vr2q[142]
    DIRECTION OUTPUT ;
    USE SIGNAL ;
    PORT
      LAYER M5 ;
        RECT  36.624 0 36.648 0.084 ;
    END
  END vr2q[142]
  PIN vr2q[143]
    DIRECTION OUTPUT ;
    USE SIGNAL ;
    PORT
      LAYER M5 ;
        RECT  36.72 0 36.744 0.084 ;
    END
  END vr2q[143]
  PIN vr2q[144]
    DIRECTION OUTPUT ;
    USE SIGNAL ;
    PORT
      LAYER M5 ;
        RECT  36.816 0 36.84 0.084 ;
    END
  END vr2q[144]
  PIN vr2q[145]
    DIRECTION OUTPUT ;
    USE SIGNAL ;
    PORT
      LAYER M5 ;
        RECT  36.912 0 36.936 0.084 ;
    END
  END vr2q[145]
  PIN vr2q[146]
    DIRECTION OUTPUT ;
    USE SIGNAL ;
    PORT
      LAYER M5 ;
        RECT  37.008 0 37.032 0.084 ;
    END
  END vr2q[146]
  PIN vr2q[147]
    DIRECTION OUTPUT ;
    USE SIGNAL ;
    PORT
      LAYER M5 ;
        RECT  37.104 0 37.128 0.084 ;
    END
  END vr2q[147]
  PIN vr2q[148]
    DIRECTION OUTPUT ;
    USE SIGNAL ;
    PORT
      LAYER M5 ;
        RECT  37.2 0 37.224 0.084 ;
    END
  END vr2q[148]
  PIN vr2q[149]
    DIRECTION OUTPUT ;
    USE SIGNAL ;
    PORT
      LAYER M5 ;
        RECT  37.296 0 37.32 0.084 ;
    END
  END vr2q[149]
  PIN vr2q[14]
    DIRECTION OUTPUT ;
    USE SIGNAL ;
    PORT
      LAYER M5 ;
        RECT  27.408 0 27.432 0.084 ;
    END
  END vr2q[14]
  PIN vr2q[150]
    DIRECTION OUTPUT ;
    USE SIGNAL ;
    PORT
      LAYER M5 ;
        RECT  37.392 0 37.416 0.084 ;
    END
  END vr2q[150]
  PIN vr2q[151]
    DIRECTION OUTPUT ;
    USE SIGNAL ;
    PORT
      LAYER M5 ;
        RECT  37.488 0 37.512 0.084 ;
    END
  END vr2q[151]
  PIN vr2q[152]
    DIRECTION OUTPUT ;
    USE SIGNAL ;
    PORT
      LAYER M5 ;
        RECT  37.584 0 37.608 0.084 ;
    END
  END vr2q[152]
  PIN vr2q[153]
    DIRECTION OUTPUT ;
    USE SIGNAL ;
    PORT
      LAYER M5 ;
        RECT  37.68 0 37.704 0.084 ;
    END
  END vr2q[153]
  PIN vr2q[154]
    DIRECTION OUTPUT ;
    USE SIGNAL ;
    PORT
      LAYER M5 ;
        RECT  37.776 0 37.8 0.084 ;
    END
  END vr2q[154]
  PIN vr2q[155]
    DIRECTION OUTPUT ;
    USE SIGNAL ;
    PORT
      LAYER M5 ;
        RECT  37.872 0 37.896 0.084 ;
    END
  END vr2q[155]
  PIN vr2q[156]
    DIRECTION OUTPUT ;
    USE SIGNAL ;
    PORT
      LAYER M5 ;
        RECT  37.968 0 37.992 0.084 ;
    END
  END vr2q[156]
  PIN vr2q[157]
    DIRECTION OUTPUT ;
    USE SIGNAL ;
    PORT
      LAYER M5 ;
        RECT  38.064 0 38.088 0.084 ;
    END
  END vr2q[157]
  PIN vr2q[158]
    DIRECTION OUTPUT ;
    USE SIGNAL ;
    PORT
      LAYER M5 ;
        RECT  38.16 0 38.184 0.084 ;
    END
  END vr2q[158]
  PIN vr2q[159]
    DIRECTION OUTPUT ;
    USE SIGNAL ;
    PORT
      LAYER M5 ;
        RECT  38.256 0 38.28 0.084 ;
    END
  END vr2q[159]
  PIN vr2q[15]
    DIRECTION OUTPUT ;
    USE SIGNAL ;
    PORT
      LAYER M5 ;
        RECT  27.504 0 27.528 0.084 ;
    END
  END vr2q[15]
  PIN vr2q[160]
    DIRECTION OUTPUT ;
    USE SIGNAL ;
    PORT
      LAYER M5 ;
        RECT  32.208 0 32.232 0.084 ;
    END
  END vr2q[160]
  PIN vr2q[161]
    DIRECTION OUTPUT ;
    USE SIGNAL ;
    PORT
      LAYER M5 ;
        RECT  32.304 0 32.328 0.084 ;
    END
  END vr2q[161]
  PIN vr2q[162]
    DIRECTION OUTPUT ;
    USE SIGNAL ;
    PORT
      LAYER M5 ;
        RECT  32.4 0 32.424 0.084 ;
    END
  END vr2q[162]
  PIN vr2q[163]
    DIRECTION OUTPUT ;
    USE SIGNAL ;
    PORT
      LAYER M5 ;
        RECT  32.496 0 32.52 0.084 ;
    END
  END vr2q[163]
  PIN vr2q[164]
    DIRECTION OUTPUT ;
    USE SIGNAL ;
    PORT
      LAYER M5 ;
        RECT  32.592 0 32.616 0.084 ;
    END
  END vr2q[164]
  PIN vr2q[165]
    DIRECTION OUTPUT ;
    USE SIGNAL ;
    PORT
      LAYER M5 ;
        RECT  32.688 0 32.712 0.084 ;
    END
  END vr2q[165]
  PIN vr2q[166]
    DIRECTION OUTPUT ;
    USE SIGNAL ;
    PORT
      LAYER M5 ;
        RECT  32.784 0 32.808 0.084 ;
    END
  END vr2q[166]
  PIN vr2q[167]
    DIRECTION OUTPUT ;
    USE SIGNAL ;
    PORT
      LAYER M5 ;
        RECT  32.88 0 32.904 0.084 ;
    END
  END vr2q[167]
  PIN vr2q[168]
    DIRECTION OUTPUT ;
    USE SIGNAL ;
    PORT
      LAYER M5 ;
        RECT  32.976 0 33 0.084 ;
    END
  END vr2q[168]
  PIN vr2q[169]
    DIRECTION OUTPUT ;
    USE SIGNAL ;
    PORT
      LAYER M5 ;
        RECT  33.072 0 33.096 0.084 ;
    END
  END vr2q[169]
  PIN vr2q[16]
    DIRECTION OUTPUT ;
    USE SIGNAL ;
    PORT
      LAYER M5 ;
        RECT  27.6 0 27.624 0.084 ;
    END
  END vr2q[16]
  PIN vr2q[170]
    DIRECTION OUTPUT ;
    USE SIGNAL ;
    PORT
      LAYER M5 ;
        RECT  33.168 0 33.192 0.084 ;
    END
  END vr2q[170]
  PIN vr2q[171]
    DIRECTION OUTPUT ;
    USE SIGNAL ;
    PORT
      LAYER M5 ;
        RECT  33.264 0 33.288 0.084 ;
    END
  END vr2q[171]
  PIN vr2q[172]
    DIRECTION OUTPUT ;
    USE SIGNAL ;
    PORT
      LAYER M5 ;
        RECT  33.36 0 33.384 0.084 ;
    END
  END vr2q[172]
  PIN vr2q[173]
    DIRECTION OUTPUT ;
    USE SIGNAL ;
    PORT
      LAYER M5 ;
        RECT  33.456 0 33.48 0.084 ;
    END
  END vr2q[173]
  PIN vr2q[174]
    DIRECTION OUTPUT ;
    USE SIGNAL ;
    PORT
      LAYER M5 ;
        RECT  33.552 0 33.576 0.084 ;
    END
  END vr2q[174]
  PIN vr2q[175]
    DIRECTION OUTPUT ;
    USE SIGNAL ;
    PORT
      LAYER M5 ;
        RECT  33.648 0 33.672 0.084 ;
    END
  END vr2q[175]
  PIN vr2q[176]
    DIRECTION OUTPUT ;
    USE SIGNAL ;
    PORT
      LAYER M5 ;
        RECT  33.744 0 33.768 0.084 ;
    END
  END vr2q[176]
  PIN vr2q[177]
    DIRECTION OUTPUT ;
    USE SIGNAL ;
    PORT
      LAYER M5 ;
        RECT  33.84 0 33.864 0.084 ;
    END
  END vr2q[177]
  PIN vr2q[178]
    DIRECTION OUTPUT ;
    USE SIGNAL ;
    PORT
      LAYER M5 ;
        RECT  33.936 0 33.96 0.084 ;
    END
  END vr2q[178]
  PIN vr2q[179]
    DIRECTION OUTPUT ;
    USE SIGNAL ;
    PORT
      LAYER M5 ;
        RECT  34.032 0 34.056 0.084 ;
    END
  END vr2q[179]
  PIN vr2q[17]
    DIRECTION OUTPUT ;
    USE SIGNAL ;
    PORT
      LAYER M5 ;
        RECT  27.696 0 27.72 0.084 ;
    END
  END vr2q[17]
  PIN vr2q[180]
    DIRECTION OUTPUT ;
    USE SIGNAL ;
    PORT
      LAYER M5 ;
        RECT  34.128 0 34.152 0.084 ;
    END
  END vr2q[180]
  PIN vr2q[181]
    DIRECTION OUTPUT ;
    USE SIGNAL ;
    PORT
      LAYER M5 ;
        RECT  34.224 0 34.248 0.084 ;
    END
  END vr2q[181]
  PIN vr2q[182]
    DIRECTION OUTPUT ;
    USE SIGNAL ;
    PORT
      LAYER M5 ;
        RECT  34.32 0 34.344 0.084 ;
    END
  END vr2q[182]
  PIN vr2q[183]
    DIRECTION OUTPUT ;
    USE SIGNAL ;
    PORT
      LAYER M5 ;
        RECT  34.416 0 34.44 0.084 ;
    END
  END vr2q[183]
  PIN vr2q[184]
    DIRECTION OUTPUT ;
    USE SIGNAL ;
    PORT
      LAYER M5 ;
        RECT  34.512 0 34.536 0.084 ;
    END
  END vr2q[184]
  PIN vr2q[185]
    DIRECTION OUTPUT ;
    USE SIGNAL ;
    PORT
      LAYER M5 ;
        RECT  34.608 0 34.632 0.084 ;
    END
  END vr2q[185]
  PIN vr2q[186]
    DIRECTION OUTPUT ;
    USE SIGNAL ;
    PORT
      LAYER M5 ;
        RECT  34.704 0 34.728 0.084 ;
    END
  END vr2q[186]
  PIN vr2q[187]
    DIRECTION OUTPUT ;
    USE SIGNAL ;
    PORT
      LAYER M5 ;
        RECT  34.8 0 34.824 0.084 ;
    END
  END vr2q[187]
  PIN vr2q[188]
    DIRECTION OUTPUT ;
    USE SIGNAL ;
    PORT
      LAYER M5 ;
        RECT  34.896 0 34.92 0.084 ;
    END
  END vr2q[188]
  PIN vr2q[189]
    DIRECTION OUTPUT ;
    USE SIGNAL ;
    PORT
      LAYER M5 ;
        RECT  34.992 0 35.016 0.084 ;
    END
  END vr2q[189]
  PIN vr2q[18]
    DIRECTION OUTPUT ;
    USE SIGNAL ;
    PORT
      LAYER M5 ;
        RECT  27.792 0 27.816 0.084 ;
    END
  END vr2q[18]
  PIN vr2q[190]
    DIRECTION OUTPUT ;
    USE SIGNAL ;
    PORT
      LAYER M5 ;
        RECT  35.088 0 35.112 0.084 ;
    END
  END vr2q[190]
  PIN vr2q[191]
    DIRECTION OUTPUT ;
    USE SIGNAL ;
    PORT
      LAYER M5 ;
        RECT  35.184 0 35.208 0.084 ;
    END
  END vr2q[191]
  PIN vr2q[192]
    DIRECTION OUTPUT ;
    USE SIGNAL ;
    PORT
      LAYER M5 ;
        RECT  54.48 0 54.504 0.084 ;
    END
  END vr2q[192]
  PIN vr2q[193]
    DIRECTION OUTPUT ;
    USE SIGNAL ;
    PORT
      LAYER M5 ;
        RECT  54.576 0 54.6 0.084 ;
    END
  END vr2q[193]
  PIN vr2q[194]
    DIRECTION OUTPUT ;
    USE SIGNAL ;
    PORT
      LAYER M5 ;
        RECT  54.672 0 54.696 0.084 ;
    END
  END vr2q[194]
  PIN vr2q[195]
    DIRECTION OUTPUT ;
    USE SIGNAL ;
    PORT
      LAYER M5 ;
        RECT  54.768 0 54.792 0.084 ;
    END
  END vr2q[195]
  PIN vr2q[196]
    DIRECTION OUTPUT ;
    USE SIGNAL ;
    PORT
      LAYER M5 ;
        RECT  54.864 0 54.888 0.084 ;
    END
  END vr2q[196]
  PIN vr2q[197]
    DIRECTION OUTPUT ;
    USE SIGNAL ;
    PORT
      LAYER M5 ;
        RECT  54.96 0 54.984 0.084 ;
    END
  END vr2q[197]
  PIN vr2q[198]
    DIRECTION OUTPUT ;
    USE SIGNAL ;
    PORT
      LAYER M5 ;
        RECT  55.056 0 55.08 0.084 ;
    END
  END vr2q[198]
  PIN vr2q[199]
    DIRECTION OUTPUT ;
    USE SIGNAL ;
    PORT
      LAYER M5 ;
        RECT  55.152 0 55.176 0.084 ;
    END
  END vr2q[199]
  PIN vr2q[19]
    DIRECTION OUTPUT ;
    USE SIGNAL ;
    PORT
      LAYER M5 ;
        RECT  27.888 0 27.912 0.084 ;
    END
  END vr2q[19]
  PIN vr2q[1]
    DIRECTION OUTPUT ;
    USE SIGNAL ;
    PORT
      LAYER M5 ;
        RECT  26.16 0 26.184 0.084 ;
    END
  END vr2q[1]
  PIN vr2q[200]
    DIRECTION OUTPUT ;
    USE SIGNAL ;
    PORT
      LAYER M5 ;
        RECT  55.248 0 55.272 0.084 ;
    END
  END vr2q[200]
  PIN vr2q[201]
    DIRECTION OUTPUT ;
    USE SIGNAL ;
    PORT
      LAYER M5 ;
        RECT  55.344 0 55.368 0.084 ;
    END
  END vr2q[201]
  PIN vr2q[202]
    DIRECTION OUTPUT ;
    USE SIGNAL ;
    PORT
      LAYER M5 ;
        RECT  55.44 0 55.464 0.084 ;
    END
  END vr2q[202]
  PIN vr2q[203]
    DIRECTION OUTPUT ;
    USE SIGNAL ;
    PORT
      LAYER M5 ;
        RECT  55.536 0 55.56 0.084 ;
    END
  END vr2q[203]
  PIN vr2q[204]
    DIRECTION OUTPUT ;
    USE SIGNAL ;
    PORT
      LAYER M5 ;
        RECT  55.632 0 55.656 0.084 ;
    END
  END vr2q[204]
  PIN vr2q[205]
    DIRECTION OUTPUT ;
    USE SIGNAL ;
    PORT
      LAYER M5 ;
        RECT  55.728 0 55.752 0.084 ;
    END
  END vr2q[205]
  PIN vr2q[206]
    DIRECTION OUTPUT ;
    USE SIGNAL ;
    PORT
      LAYER M5 ;
        RECT  55.824 0 55.848 0.084 ;
    END
  END vr2q[206]
  PIN vr2q[207]
    DIRECTION OUTPUT ;
    USE SIGNAL ;
    PORT
      LAYER M5 ;
        RECT  55.92 0 55.944 0.084 ;
    END
  END vr2q[207]
  PIN vr2q[208]
    DIRECTION OUTPUT ;
    USE SIGNAL ;
    PORT
      LAYER M5 ;
        RECT  56.016 0 56.04 0.084 ;
    END
  END vr2q[208]
  PIN vr2q[209]
    DIRECTION OUTPUT ;
    USE SIGNAL ;
    PORT
      LAYER M5 ;
        RECT  56.112 0 56.136 0.084 ;
    END
  END vr2q[209]
  PIN vr2q[20]
    DIRECTION OUTPUT ;
    USE SIGNAL ;
    PORT
      LAYER M5 ;
        RECT  27.984 0 28.008 0.084 ;
    END
  END vr2q[20]
  PIN vr2q[210]
    DIRECTION OUTPUT ;
    USE SIGNAL ;
    PORT
      LAYER M5 ;
        RECT  56.208 0 56.232 0.084 ;
    END
  END vr2q[210]
  PIN vr2q[211]
    DIRECTION OUTPUT ;
    USE SIGNAL ;
    PORT
      LAYER M5 ;
        RECT  56.304 0 56.328 0.084 ;
    END
  END vr2q[211]
  PIN vr2q[212]
    DIRECTION OUTPUT ;
    USE SIGNAL ;
    PORT
      LAYER M5 ;
        RECT  56.4 0 56.424 0.084 ;
    END
  END vr2q[212]
  PIN vr2q[213]
    DIRECTION OUTPUT ;
    USE SIGNAL ;
    PORT
      LAYER M5 ;
        RECT  56.496 0 56.52 0.084 ;
    END
  END vr2q[213]
  PIN vr2q[214]
    DIRECTION OUTPUT ;
    USE SIGNAL ;
    PORT
      LAYER M5 ;
        RECT  56.592 0 56.616 0.084 ;
    END
  END vr2q[214]
  PIN vr2q[215]
    DIRECTION OUTPUT ;
    USE SIGNAL ;
    PORT
      LAYER M5 ;
        RECT  56.688 0 56.712 0.084 ;
    END
  END vr2q[215]
  PIN vr2q[216]
    DIRECTION OUTPUT ;
    USE SIGNAL ;
    PORT
      LAYER M5 ;
        RECT  56.784 0 56.808 0.084 ;
    END
  END vr2q[216]
  PIN vr2q[217]
    DIRECTION OUTPUT ;
    USE SIGNAL ;
    PORT
      LAYER M5 ;
        RECT  56.88 0 56.904 0.084 ;
    END
  END vr2q[217]
  PIN vr2q[218]
    DIRECTION OUTPUT ;
    USE SIGNAL ;
    PORT
      LAYER M5 ;
        RECT  56.976 0 57 0.084 ;
    END
  END vr2q[218]
  PIN vr2q[219]
    DIRECTION OUTPUT ;
    USE SIGNAL ;
    PORT
      LAYER M5 ;
        RECT  57.072 0 57.096 0.084 ;
    END
  END vr2q[219]
  PIN vr2q[21]
    DIRECTION OUTPUT ;
    USE SIGNAL ;
    PORT
      LAYER M5 ;
        RECT  28.08 0 28.104 0.084 ;
    END
  END vr2q[21]
  PIN vr2q[220]
    DIRECTION OUTPUT ;
    USE SIGNAL ;
    PORT
      LAYER M5 ;
        RECT  57.168 0 57.192 0.084 ;
    END
  END vr2q[220]
  PIN vr2q[221]
    DIRECTION OUTPUT ;
    USE SIGNAL ;
    PORT
      LAYER M5 ;
        RECT  57.264 0 57.288 0.084 ;
    END
  END vr2q[221]
  PIN vr2q[222]
    DIRECTION OUTPUT ;
    USE SIGNAL ;
    PORT
      LAYER M5 ;
        RECT  57.36 0 57.384 0.084 ;
    END
  END vr2q[222]
  PIN vr2q[223]
    DIRECTION OUTPUT ;
    USE SIGNAL ;
    PORT
      LAYER M5 ;
        RECT  57.456 0 57.48 0.084 ;
    END
  END vr2q[223]
  PIN vr2q[224]
    DIRECTION OUTPUT ;
    USE SIGNAL ;
    PORT
      LAYER M5 ;
        RECT  48.336 0 48.36 0.084 ;
    END
  END vr2q[224]
  PIN vr2q[225]
    DIRECTION OUTPUT ;
    USE SIGNAL ;
    PORT
      LAYER M5 ;
        RECT  48.432 0 48.456 0.084 ;
    END
  END vr2q[225]
  PIN vr2q[226]
    DIRECTION OUTPUT ;
    USE SIGNAL ;
    PORT
      LAYER M5 ;
        RECT  48.528 0 48.552 0.084 ;
    END
  END vr2q[226]
  PIN vr2q[227]
    DIRECTION OUTPUT ;
    USE SIGNAL ;
    PORT
      LAYER M5 ;
        RECT  48.624 0 48.648 0.084 ;
    END
  END vr2q[227]
  PIN vr2q[228]
    DIRECTION OUTPUT ;
    USE SIGNAL ;
    PORT
      LAYER M5 ;
        RECT  48.72 0 48.744 0.084 ;
    END
  END vr2q[228]
  PIN vr2q[229]
    DIRECTION OUTPUT ;
    USE SIGNAL ;
    PORT
      LAYER M5 ;
        RECT  48.816 0 48.84 0.084 ;
    END
  END vr2q[229]
  PIN vr2q[22]
    DIRECTION OUTPUT ;
    USE SIGNAL ;
    PORT
      LAYER M5 ;
        RECT  28.176 0 28.2 0.084 ;
    END
  END vr2q[22]
  PIN vr2q[230]
    DIRECTION OUTPUT ;
    USE SIGNAL ;
    PORT
      LAYER M5 ;
        RECT  48.912 0 48.936 0.084 ;
    END
  END vr2q[230]
  PIN vr2q[231]
    DIRECTION OUTPUT ;
    USE SIGNAL ;
    PORT
      LAYER M5 ;
        RECT  49.008 0 49.032 0.084 ;
    END
  END vr2q[231]
  PIN vr2q[232]
    DIRECTION OUTPUT ;
    USE SIGNAL ;
    PORT
      LAYER M5 ;
        RECT  49.104 0 49.128 0.084 ;
    END
  END vr2q[232]
  PIN vr2q[233]
    DIRECTION OUTPUT ;
    USE SIGNAL ;
    PORT
      LAYER M5 ;
        RECT  49.2 0 49.224 0.084 ;
    END
  END vr2q[233]
  PIN vr2q[234]
    DIRECTION OUTPUT ;
    USE SIGNAL ;
    PORT
      LAYER M5 ;
        RECT  49.296 0 49.32 0.084 ;
    END
  END vr2q[234]
  PIN vr2q[235]
    DIRECTION OUTPUT ;
    USE SIGNAL ;
    PORT
      LAYER M5 ;
        RECT  49.392 0 49.416 0.084 ;
    END
  END vr2q[235]
  PIN vr2q[236]
    DIRECTION OUTPUT ;
    USE SIGNAL ;
    PORT
      LAYER M5 ;
        RECT  49.488 0 49.512 0.084 ;
    END
  END vr2q[236]
  PIN vr2q[237]
    DIRECTION OUTPUT ;
    USE SIGNAL ;
    PORT
      LAYER M5 ;
        RECT  49.584 0 49.608 0.084 ;
    END
  END vr2q[237]
  PIN vr2q[238]
    DIRECTION OUTPUT ;
    USE SIGNAL ;
    PORT
      LAYER M5 ;
        RECT  49.68 0 49.704 0.084 ;
    END
  END vr2q[238]
  PIN vr2q[239]
    DIRECTION OUTPUT ;
    USE SIGNAL ;
    PORT
      LAYER M5 ;
        RECT  49.776 0 49.8 0.084 ;
    END
  END vr2q[239]
  PIN vr2q[23]
    DIRECTION OUTPUT ;
    USE SIGNAL ;
    PORT
      LAYER M5 ;
        RECT  28.272 0 28.296 0.084 ;
    END
  END vr2q[23]
  PIN vr2q[240]
    DIRECTION OUTPUT ;
    USE SIGNAL ;
    PORT
      LAYER M5 ;
        RECT  49.872 0 49.896 0.084 ;
    END
  END vr2q[240]
  PIN vr2q[241]
    DIRECTION OUTPUT ;
    USE SIGNAL ;
    PORT
      LAYER M5 ;
        RECT  49.968 0 49.992 0.084 ;
    END
  END vr2q[241]
  PIN vr2q[242]
    DIRECTION OUTPUT ;
    USE SIGNAL ;
    PORT
      LAYER M5 ;
        RECT  50.064 0 50.088 0.084 ;
    END
  END vr2q[242]
  PIN vr2q[243]
    DIRECTION OUTPUT ;
    USE SIGNAL ;
    PORT
      LAYER M5 ;
        RECT  50.16 0 50.184 0.084 ;
    END
  END vr2q[243]
  PIN vr2q[244]
    DIRECTION OUTPUT ;
    USE SIGNAL ;
    PORT
      LAYER M5 ;
        RECT  50.256 0 50.28 0.084 ;
    END
  END vr2q[244]
  PIN vr2q[245]
    DIRECTION OUTPUT ;
    USE SIGNAL ;
    PORT
      LAYER M5 ;
        RECT  50.352 0 50.376 0.084 ;
    END
  END vr2q[245]
  PIN vr2q[246]
    DIRECTION OUTPUT ;
    USE SIGNAL ;
    PORT
      LAYER M5 ;
        RECT  50.448 0 50.472 0.084 ;
    END
  END vr2q[246]
  PIN vr2q[247]
    DIRECTION OUTPUT ;
    USE SIGNAL ;
    PORT
      LAYER M5 ;
        RECT  50.544 0 50.568 0.084 ;
    END
  END vr2q[247]
  PIN vr2q[248]
    DIRECTION OUTPUT ;
    USE SIGNAL ;
    PORT
      LAYER M5 ;
        RECT  50.64 0 50.664 0.084 ;
    END
  END vr2q[248]
  PIN vr2q[249]
    DIRECTION OUTPUT ;
    USE SIGNAL ;
    PORT
      LAYER M5 ;
        RECT  50.736 0 50.76 0.084 ;
    END
  END vr2q[249]
  PIN vr2q[24]
    DIRECTION OUTPUT ;
    USE SIGNAL ;
    PORT
      LAYER M5 ;
        RECT  28.368 0 28.392 0.084 ;
    END
  END vr2q[24]
  PIN vr2q[250]
    DIRECTION OUTPUT ;
    USE SIGNAL ;
    PORT
      LAYER M5 ;
        RECT  50.832 0 50.856 0.084 ;
    END
  END vr2q[250]
  PIN vr2q[251]
    DIRECTION OUTPUT ;
    USE SIGNAL ;
    PORT
      LAYER M5 ;
        RECT  50.928 0 50.952 0.084 ;
    END
  END vr2q[251]
  PIN vr2q[252]
    DIRECTION OUTPUT ;
    USE SIGNAL ;
    PORT
      LAYER M5 ;
        RECT  51.024 0 51.048 0.084 ;
    END
  END vr2q[252]
  PIN vr2q[253]
    DIRECTION OUTPUT ;
    USE SIGNAL ;
    PORT
      LAYER M5 ;
        RECT  51.12 0 51.144 0.084 ;
    END
  END vr2q[253]
  PIN vr2q[254]
    DIRECTION OUTPUT ;
    USE SIGNAL ;
    PORT
      LAYER M5 ;
        RECT  51.216 0 51.24 0.084 ;
    END
  END vr2q[254]
  PIN vr2q[255]
    DIRECTION OUTPUT ;
    USE SIGNAL ;
    PORT
      LAYER M5 ;
        RECT  51.312 0 51.336 0.084 ;
    END
  END vr2q[255]
  PIN vr2q[256]
    DIRECTION OUTPUT ;
    USE SIGNAL ;
    PORT
      LAYER M5 ;
        RECT  39.12 0 39.144 0.084 ;
    END
  END vr2q[256]
  PIN vr2q[257]
    DIRECTION OUTPUT ;
    USE SIGNAL ;
    PORT
      LAYER M5 ;
        RECT  39.216 0 39.24 0.084 ;
    END
  END vr2q[257]
  PIN vr2q[258]
    DIRECTION OUTPUT ;
    USE SIGNAL ;
    PORT
      LAYER M5 ;
        RECT  39.312 0 39.336 0.084 ;
    END
  END vr2q[258]
  PIN vr2q[259]
    DIRECTION OUTPUT ;
    USE SIGNAL ;
    PORT
      LAYER M5 ;
        RECT  39.408 0 39.432 0.084 ;
    END
  END vr2q[259]
  PIN vr2q[25]
    DIRECTION OUTPUT ;
    USE SIGNAL ;
    PORT
      LAYER M5 ;
        RECT  28.464 0 28.488 0.084 ;
    END
  END vr2q[25]
  PIN vr2q[260]
    DIRECTION OUTPUT ;
    USE SIGNAL ;
    PORT
      LAYER M5 ;
        RECT  39.504 0 39.528 0.084 ;
    END
  END vr2q[260]
  PIN vr2q[261]
    DIRECTION OUTPUT ;
    USE SIGNAL ;
    PORT
      LAYER M5 ;
        RECT  39.6 0 39.624 0.084 ;
    END
  END vr2q[261]
  PIN vr2q[262]
    DIRECTION OUTPUT ;
    USE SIGNAL ;
    PORT
      LAYER M5 ;
        RECT  39.696 0 39.72 0.084 ;
    END
  END vr2q[262]
  PIN vr2q[263]
    DIRECTION OUTPUT ;
    USE SIGNAL ;
    PORT
      LAYER M5 ;
        RECT  39.792 0 39.816 0.084 ;
    END
  END vr2q[263]
  PIN vr2q[264]
    DIRECTION OUTPUT ;
    USE SIGNAL ;
    PORT
      LAYER M5 ;
        RECT  39.888 0 39.912 0.084 ;
    END
  END vr2q[264]
  PIN vr2q[265]
    DIRECTION OUTPUT ;
    USE SIGNAL ;
    PORT
      LAYER M5 ;
        RECT  39.984 0 40.008 0.084 ;
    END
  END vr2q[265]
  PIN vr2q[266]
    DIRECTION OUTPUT ;
    USE SIGNAL ;
    PORT
      LAYER M5 ;
        RECT  40.08 0 40.104 0.084 ;
    END
  END vr2q[266]
  PIN vr2q[267]
    DIRECTION OUTPUT ;
    USE SIGNAL ;
    PORT
      LAYER M5 ;
        RECT  40.176 0 40.2 0.084 ;
    END
  END vr2q[267]
  PIN vr2q[268]
    DIRECTION OUTPUT ;
    USE SIGNAL ;
    PORT
      LAYER M5 ;
        RECT  40.272 0 40.296 0.084 ;
    END
  END vr2q[268]
  PIN vr2q[269]
    DIRECTION OUTPUT ;
    USE SIGNAL ;
    PORT
      LAYER M5 ;
        RECT  40.368 0 40.392 0.084 ;
    END
  END vr2q[269]
  PIN vr2q[26]
    DIRECTION OUTPUT ;
    USE SIGNAL ;
    PORT
      LAYER M5 ;
        RECT  28.56 0 28.584 0.084 ;
    END
  END vr2q[26]
  PIN vr2q[270]
    DIRECTION OUTPUT ;
    USE SIGNAL ;
    PORT
      LAYER M5 ;
        RECT  40.464 0 40.488 0.084 ;
    END
  END vr2q[270]
  PIN vr2q[271]
    DIRECTION OUTPUT ;
    USE SIGNAL ;
    PORT
      LAYER M5 ;
        RECT  40.56 0 40.584 0.084 ;
    END
  END vr2q[271]
  PIN vr2q[272]
    DIRECTION OUTPUT ;
    USE SIGNAL ;
    PORT
      LAYER M5 ;
        RECT  40.656 0 40.68 0.084 ;
    END
  END vr2q[272]
  PIN vr2q[273]
    DIRECTION OUTPUT ;
    USE SIGNAL ;
    PORT
      LAYER M5 ;
        RECT  40.752 0 40.776 0.084 ;
    END
  END vr2q[273]
  PIN vr2q[274]
    DIRECTION OUTPUT ;
    USE SIGNAL ;
    PORT
      LAYER M5 ;
        RECT  40.848 0 40.872 0.084 ;
    END
  END vr2q[274]
  PIN vr2q[275]
    DIRECTION OUTPUT ;
    USE SIGNAL ;
    PORT
      LAYER M5 ;
        RECT  40.944 0 40.968 0.084 ;
    END
  END vr2q[275]
  PIN vr2q[276]
    DIRECTION OUTPUT ;
    USE SIGNAL ;
    PORT
      LAYER M5 ;
        RECT  41.04 0 41.064 0.084 ;
    END
  END vr2q[276]
  PIN vr2q[277]
    DIRECTION OUTPUT ;
    USE SIGNAL ;
    PORT
      LAYER M5 ;
        RECT  41.136 0 41.16 0.084 ;
    END
  END vr2q[277]
  PIN vr2q[278]
    DIRECTION OUTPUT ;
    USE SIGNAL ;
    PORT
      LAYER M5 ;
        RECT  41.232 0 41.256 0.084 ;
    END
  END vr2q[278]
  PIN vr2q[279]
    DIRECTION OUTPUT ;
    USE SIGNAL ;
    PORT
      LAYER M5 ;
        RECT  41.328 0 41.352 0.084 ;
    END
  END vr2q[279]
  PIN vr2q[27]
    DIRECTION OUTPUT ;
    USE SIGNAL ;
    PORT
      LAYER M5 ;
        RECT  28.656 0 28.68 0.084 ;
    END
  END vr2q[27]
  PIN vr2q[280]
    DIRECTION OUTPUT ;
    USE SIGNAL ;
    PORT
      LAYER M5 ;
        RECT  41.424 0 41.448 0.084 ;
    END
  END vr2q[280]
  PIN vr2q[281]
    DIRECTION OUTPUT ;
    USE SIGNAL ;
    PORT
      LAYER M5 ;
        RECT  41.52 0 41.544 0.084 ;
    END
  END vr2q[281]
  PIN vr2q[282]
    DIRECTION OUTPUT ;
    USE SIGNAL ;
    PORT
      LAYER M5 ;
        RECT  41.616 0 41.64 0.084 ;
    END
  END vr2q[282]
  PIN vr2q[283]
    DIRECTION OUTPUT ;
    USE SIGNAL ;
    PORT
      LAYER M5 ;
        RECT  41.712 0 41.736 0.084 ;
    END
  END vr2q[283]
  PIN vr2q[284]
    DIRECTION OUTPUT ;
    USE SIGNAL ;
    PORT
      LAYER M5 ;
        RECT  41.808 0 41.832 0.084 ;
    END
  END vr2q[284]
  PIN vr2q[285]
    DIRECTION OUTPUT ;
    USE SIGNAL ;
    PORT
      LAYER M5 ;
        RECT  41.904 0 41.928 0.084 ;
    END
  END vr2q[285]
  PIN vr2q[286]
    DIRECTION OUTPUT ;
    USE SIGNAL ;
    PORT
      LAYER M5 ;
        RECT  42 0 42.024 0.084 ;
    END
  END vr2q[286]
  PIN vr2q[287]
    DIRECTION OUTPUT ;
    USE SIGNAL ;
    PORT
      LAYER M5 ;
        RECT  42.096 0 42.12 0.084 ;
    END
  END vr2q[287]
  PIN vr2q[288]
    DIRECTION OUTPUT ;
    USE SIGNAL ;
    PORT
      LAYER M5 ;
        RECT  45.264 0 45.288 0.084 ;
    END
  END vr2q[288]
  PIN vr2q[289]
    DIRECTION OUTPUT ;
    USE SIGNAL ;
    PORT
      LAYER M5 ;
        RECT  45.36 0 45.384 0.084 ;
    END
  END vr2q[289]
  PIN vr2q[28]
    DIRECTION OUTPUT ;
    USE SIGNAL ;
    PORT
      LAYER M5 ;
        RECT  28.752 0 28.776 0.084 ;
    END
  END vr2q[28]
  PIN vr2q[290]
    DIRECTION OUTPUT ;
    USE SIGNAL ;
    PORT
      LAYER M5 ;
        RECT  45.456 0 45.48 0.084 ;
    END
  END vr2q[290]
  PIN vr2q[291]
    DIRECTION OUTPUT ;
    USE SIGNAL ;
    PORT
      LAYER M5 ;
        RECT  45.552 0 45.576 0.084 ;
    END
  END vr2q[291]
  PIN vr2q[292]
    DIRECTION OUTPUT ;
    USE SIGNAL ;
    PORT
      LAYER M5 ;
        RECT  45.648 0 45.672 0.084 ;
    END
  END vr2q[292]
  PIN vr2q[293]
    DIRECTION OUTPUT ;
    USE SIGNAL ;
    PORT
      LAYER M5 ;
        RECT  45.744 0 45.768 0.084 ;
    END
  END vr2q[293]
  PIN vr2q[294]
    DIRECTION OUTPUT ;
    USE SIGNAL ;
    PORT
      LAYER M5 ;
        RECT  45.84 0 45.864 0.084 ;
    END
  END vr2q[294]
  PIN vr2q[295]
    DIRECTION OUTPUT ;
    USE SIGNAL ;
    PORT
      LAYER M5 ;
        RECT  45.936 0 45.96 0.084 ;
    END
  END vr2q[295]
  PIN vr2q[296]
    DIRECTION OUTPUT ;
    USE SIGNAL ;
    PORT
      LAYER M5 ;
        RECT  46.032 0 46.056 0.084 ;
    END
  END vr2q[296]
  PIN vr2q[297]
    DIRECTION OUTPUT ;
    USE SIGNAL ;
    PORT
      LAYER M5 ;
        RECT  46.128 0 46.152 0.084 ;
    END
  END vr2q[297]
  PIN vr2q[298]
    DIRECTION OUTPUT ;
    USE SIGNAL ;
    PORT
      LAYER M5 ;
        RECT  46.224 0 46.248 0.084 ;
    END
  END vr2q[298]
  PIN vr2q[299]
    DIRECTION OUTPUT ;
    USE SIGNAL ;
    PORT
      LAYER M5 ;
        RECT  46.32 0 46.344 0.084 ;
    END
  END vr2q[299]
  PIN vr2q[29]
    DIRECTION OUTPUT ;
    USE SIGNAL ;
    PORT
      LAYER M5 ;
        RECT  28.848 0 28.872 0.084 ;
    END
  END vr2q[29]
  PIN vr2q[2]
    DIRECTION OUTPUT ;
    USE SIGNAL ;
    PORT
      LAYER M5 ;
        RECT  26.256 0 26.28 0.084 ;
    END
  END vr2q[2]
  PIN vr2q[300]
    DIRECTION OUTPUT ;
    USE SIGNAL ;
    PORT
      LAYER M5 ;
        RECT  46.416 0 46.44 0.084 ;
    END
  END vr2q[300]
  PIN vr2q[301]
    DIRECTION OUTPUT ;
    USE SIGNAL ;
    PORT
      LAYER M5 ;
        RECT  46.512 0 46.536 0.084 ;
    END
  END vr2q[301]
  PIN vr2q[302]
    DIRECTION OUTPUT ;
    USE SIGNAL ;
    PORT
      LAYER M5 ;
        RECT  46.608 0 46.632 0.084 ;
    END
  END vr2q[302]
  PIN vr2q[303]
    DIRECTION OUTPUT ;
    USE SIGNAL ;
    PORT
      LAYER M5 ;
        RECT  46.704 0 46.728 0.084 ;
    END
  END vr2q[303]
  PIN vr2q[304]
    DIRECTION OUTPUT ;
    USE SIGNAL ;
    PORT
      LAYER M5 ;
        RECT  46.8 0 46.824 0.084 ;
    END
  END vr2q[304]
  PIN vr2q[305]
    DIRECTION OUTPUT ;
    USE SIGNAL ;
    PORT
      LAYER M5 ;
        RECT  46.896 0 46.92 0.084 ;
    END
  END vr2q[305]
  PIN vr2q[306]
    DIRECTION OUTPUT ;
    USE SIGNAL ;
    PORT
      LAYER M5 ;
        RECT  46.992 0 47.016 0.084 ;
    END
  END vr2q[306]
  PIN vr2q[307]
    DIRECTION OUTPUT ;
    USE SIGNAL ;
    PORT
      LAYER M5 ;
        RECT  47.088 0 47.112 0.084 ;
    END
  END vr2q[307]
  PIN vr2q[308]
    DIRECTION OUTPUT ;
    USE SIGNAL ;
    PORT
      LAYER M5 ;
        RECT  47.184 0 47.208 0.084 ;
    END
  END vr2q[308]
  PIN vr2q[309]
    DIRECTION OUTPUT ;
    USE SIGNAL ;
    PORT
      LAYER M5 ;
        RECT  47.28 0 47.304 0.084 ;
    END
  END vr2q[309]
  PIN vr2q[30]
    DIRECTION OUTPUT ;
    USE SIGNAL ;
    PORT
      LAYER M5 ;
        RECT  28.944 0 28.968 0.084 ;
    END
  END vr2q[30]
  PIN vr2q[310]
    DIRECTION OUTPUT ;
    USE SIGNAL ;
    PORT
      LAYER M5 ;
        RECT  47.376 0 47.4 0.084 ;
    END
  END vr2q[310]
  PIN vr2q[311]
    DIRECTION OUTPUT ;
    USE SIGNAL ;
    PORT
      LAYER M5 ;
        RECT  47.472 0 47.496 0.084 ;
    END
  END vr2q[311]
  PIN vr2q[312]
    DIRECTION OUTPUT ;
    USE SIGNAL ;
    PORT
      LAYER M5 ;
        RECT  47.568 0 47.592 0.084 ;
    END
  END vr2q[312]
  PIN vr2q[313]
    DIRECTION OUTPUT ;
    USE SIGNAL ;
    PORT
      LAYER M5 ;
        RECT  47.664 0 47.688 0.084 ;
    END
  END vr2q[313]
  PIN vr2q[314]
    DIRECTION OUTPUT ;
    USE SIGNAL ;
    PORT
      LAYER M5 ;
        RECT  47.76 0 47.784 0.084 ;
    END
  END vr2q[314]
  PIN vr2q[315]
    DIRECTION OUTPUT ;
    USE SIGNAL ;
    PORT
      LAYER M5 ;
        RECT  47.856 0 47.88 0.084 ;
    END
  END vr2q[315]
  PIN vr2q[316]
    DIRECTION OUTPUT ;
    USE SIGNAL ;
    PORT
      LAYER M5 ;
        RECT  47.952 0 47.976 0.084 ;
    END
  END vr2q[316]
  PIN vr2q[317]
    DIRECTION OUTPUT ;
    USE SIGNAL ;
    PORT
      LAYER M5 ;
        RECT  48.048 0 48.072 0.084 ;
    END
  END vr2q[317]
  PIN vr2q[318]
    DIRECTION OUTPUT ;
    USE SIGNAL ;
    PORT
      LAYER M5 ;
        RECT  48.144 0 48.168 0.084 ;
    END
  END vr2q[318]
  PIN vr2q[319]
    DIRECTION OUTPUT ;
    USE SIGNAL ;
    PORT
      LAYER M5 ;
        RECT  48.24 0 48.264 0.084 ;
    END
  END vr2q[319]
  PIN vr2q[31]
    DIRECTION OUTPUT ;
    USE SIGNAL ;
    PORT
      LAYER M5 ;
        RECT  29.04 0 29.064 0.084 ;
    END
  END vr2q[31]
  PIN vr2q[320]
    DIRECTION OUTPUT ;
    USE SIGNAL ;
    PORT
      LAYER M5 ;
        RECT  51.408 0 51.432 0.084 ;
    END
  END vr2q[320]
  PIN vr2q[321]
    DIRECTION OUTPUT ;
    USE SIGNAL ;
    PORT
      LAYER M5 ;
        RECT  51.504 0 51.528 0.084 ;
    END
  END vr2q[321]
  PIN vr2q[322]
    DIRECTION OUTPUT ;
    USE SIGNAL ;
    PORT
      LAYER M5 ;
        RECT  51.6 0 51.624 0.084 ;
    END
  END vr2q[322]
  PIN vr2q[323]
    DIRECTION OUTPUT ;
    USE SIGNAL ;
    PORT
      LAYER M5 ;
        RECT  51.696 0 51.72 0.084 ;
    END
  END vr2q[323]
  PIN vr2q[324]
    DIRECTION OUTPUT ;
    USE SIGNAL ;
    PORT
      LAYER M5 ;
        RECT  51.792 0 51.816 0.084 ;
    END
  END vr2q[324]
  PIN vr2q[325]
    DIRECTION OUTPUT ;
    USE SIGNAL ;
    PORT
      LAYER M5 ;
        RECT  51.888 0 51.912 0.084 ;
    END
  END vr2q[325]
  PIN vr2q[326]
    DIRECTION OUTPUT ;
    USE SIGNAL ;
    PORT
      LAYER M5 ;
        RECT  51.984 0 52.008 0.084 ;
    END
  END vr2q[326]
  PIN vr2q[327]
    DIRECTION OUTPUT ;
    USE SIGNAL ;
    PORT
      LAYER M5 ;
        RECT  52.08 0 52.104 0.084 ;
    END
  END vr2q[327]
  PIN vr2q[328]
    DIRECTION OUTPUT ;
    USE SIGNAL ;
    PORT
      LAYER M5 ;
        RECT  52.176 0 52.2 0.084 ;
    END
  END vr2q[328]
  PIN vr2q[329]
    DIRECTION OUTPUT ;
    USE SIGNAL ;
    PORT
      LAYER M5 ;
        RECT  52.272 0 52.296 0.084 ;
    END
  END vr2q[329]
  PIN vr2q[32]
    DIRECTION OUTPUT ;
    USE SIGNAL ;
    PORT
      LAYER M5 ;
        RECT  19.92 0 19.944 0.084 ;
    END
  END vr2q[32]
  PIN vr2q[330]
    DIRECTION OUTPUT ;
    USE SIGNAL ;
    PORT
      LAYER M5 ;
        RECT  52.368 0 52.392 0.084 ;
    END
  END vr2q[330]
  PIN vr2q[331]
    DIRECTION OUTPUT ;
    USE SIGNAL ;
    PORT
      LAYER M5 ;
        RECT  52.464 0 52.488 0.084 ;
    END
  END vr2q[331]
  PIN vr2q[332]
    DIRECTION OUTPUT ;
    USE SIGNAL ;
    PORT
      LAYER M5 ;
        RECT  52.56 0 52.584 0.084 ;
    END
  END vr2q[332]
  PIN vr2q[333]
    DIRECTION OUTPUT ;
    USE SIGNAL ;
    PORT
      LAYER M5 ;
        RECT  52.656 0 52.68 0.084 ;
    END
  END vr2q[333]
  PIN vr2q[334]
    DIRECTION OUTPUT ;
    USE SIGNAL ;
    PORT
      LAYER M5 ;
        RECT  52.752 0 52.776 0.084 ;
    END
  END vr2q[334]
  PIN vr2q[335]
    DIRECTION OUTPUT ;
    USE SIGNAL ;
    PORT
      LAYER M5 ;
        RECT  52.848 0 52.872 0.084 ;
    END
  END vr2q[335]
  PIN vr2q[336]
    DIRECTION OUTPUT ;
    USE SIGNAL ;
    PORT
      LAYER M5 ;
        RECT  52.944 0 52.968 0.084 ;
    END
  END vr2q[336]
  PIN vr2q[337]
    DIRECTION OUTPUT ;
    USE SIGNAL ;
    PORT
      LAYER M5 ;
        RECT  53.04 0 53.064 0.084 ;
    END
  END vr2q[337]
  PIN vr2q[338]
    DIRECTION OUTPUT ;
    USE SIGNAL ;
    PORT
      LAYER M5 ;
        RECT  53.136 0 53.16 0.084 ;
    END
  END vr2q[338]
  PIN vr2q[339]
    DIRECTION OUTPUT ;
    USE SIGNAL ;
    PORT
      LAYER M5 ;
        RECT  53.232 0 53.256 0.084 ;
    END
  END vr2q[339]
  PIN vr2q[33]
    DIRECTION OUTPUT ;
    USE SIGNAL ;
    PORT
      LAYER M5 ;
        RECT  20.016 0 20.04 0.084 ;
    END
  END vr2q[33]
  PIN vr2q[340]
    DIRECTION OUTPUT ;
    USE SIGNAL ;
    PORT
      LAYER M5 ;
        RECT  53.328 0 53.352 0.084 ;
    END
  END vr2q[340]
  PIN vr2q[341]
    DIRECTION OUTPUT ;
    USE SIGNAL ;
    PORT
      LAYER M5 ;
        RECT  53.424 0 53.448 0.084 ;
    END
  END vr2q[341]
  PIN vr2q[342]
    DIRECTION OUTPUT ;
    USE SIGNAL ;
    PORT
      LAYER M5 ;
        RECT  53.52 0 53.544 0.084 ;
    END
  END vr2q[342]
  PIN vr2q[343]
    DIRECTION OUTPUT ;
    USE SIGNAL ;
    PORT
      LAYER M5 ;
        RECT  53.616 0 53.64 0.084 ;
    END
  END vr2q[343]
  PIN vr2q[344]
    DIRECTION OUTPUT ;
    USE SIGNAL ;
    PORT
      LAYER M5 ;
        RECT  53.712 0 53.736 0.084 ;
    END
  END vr2q[344]
  PIN vr2q[345]
    DIRECTION OUTPUT ;
    USE SIGNAL ;
    PORT
      LAYER M5 ;
        RECT  53.808 0 53.832 0.084 ;
    END
  END vr2q[345]
  PIN vr2q[346]
    DIRECTION OUTPUT ;
    USE SIGNAL ;
    PORT
      LAYER M5 ;
        RECT  53.904 0 53.928 0.084 ;
    END
  END vr2q[346]
  PIN vr2q[347]
    DIRECTION OUTPUT ;
    USE SIGNAL ;
    PORT
      LAYER M5 ;
        RECT  54 0 54.024 0.084 ;
    END
  END vr2q[347]
  PIN vr2q[348]
    DIRECTION OUTPUT ;
    USE SIGNAL ;
    PORT
      LAYER M5 ;
        RECT  54.096 0 54.12 0.084 ;
    END
  END vr2q[348]
  PIN vr2q[349]
    DIRECTION OUTPUT ;
    USE SIGNAL ;
    PORT
      LAYER M5 ;
        RECT  54.192 0 54.216 0.084 ;
    END
  END vr2q[349]
  PIN vr2q[34]
    DIRECTION OUTPUT ;
    USE SIGNAL ;
    PORT
      LAYER M5 ;
        RECT  20.112 0 20.136 0.084 ;
    END
  END vr2q[34]
  PIN vr2q[350]
    DIRECTION OUTPUT ;
    USE SIGNAL ;
    PORT
      LAYER M5 ;
        RECT  54.288 0 54.312 0.084 ;
    END
  END vr2q[350]
  PIN vr2q[351]
    DIRECTION OUTPUT ;
    USE SIGNAL ;
    PORT
      LAYER M5 ;
        RECT  54.384 0 54.408 0.084 ;
    END
  END vr2q[351]
  PIN vr2q[352]
    DIRECTION OUTPUT ;
    USE SIGNAL ;
    PORT
      LAYER M5 ;
        RECT  42.192 0 42.216 0.084 ;
    END
  END vr2q[352]
  PIN vr2q[353]
    DIRECTION OUTPUT ;
    USE SIGNAL ;
    PORT
      LAYER M5 ;
        RECT  42.288 0 42.312 0.084 ;
    END
  END vr2q[353]
  PIN vr2q[354]
    DIRECTION OUTPUT ;
    USE SIGNAL ;
    PORT
      LAYER M5 ;
        RECT  42.384 0 42.408 0.084 ;
    END
  END vr2q[354]
  PIN vr2q[355]
    DIRECTION OUTPUT ;
    USE SIGNAL ;
    PORT
      LAYER M5 ;
        RECT  42.48 0 42.504 0.084 ;
    END
  END vr2q[355]
  PIN vr2q[356]
    DIRECTION OUTPUT ;
    USE SIGNAL ;
    PORT
      LAYER M5 ;
        RECT  42.576 0 42.6 0.084 ;
    END
  END vr2q[356]
  PIN vr2q[357]
    DIRECTION OUTPUT ;
    USE SIGNAL ;
    PORT
      LAYER M5 ;
        RECT  42.672 0 42.696 0.084 ;
    END
  END vr2q[357]
  PIN vr2q[358]
    DIRECTION OUTPUT ;
    USE SIGNAL ;
    PORT
      LAYER M5 ;
        RECT  42.768 0 42.792 0.084 ;
    END
  END vr2q[358]
  PIN vr2q[359]
    DIRECTION OUTPUT ;
    USE SIGNAL ;
    PORT
      LAYER M5 ;
        RECT  42.864 0 42.888 0.084 ;
    END
  END vr2q[359]
  PIN vr2q[35]
    DIRECTION OUTPUT ;
    USE SIGNAL ;
    PORT
      LAYER M5 ;
        RECT  20.208 0 20.232 0.084 ;
    END
  END vr2q[35]
  PIN vr2q[360]
    DIRECTION OUTPUT ;
    USE SIGNAL ;
    PORT
      LAYER M5 ;
        RECT  42.96 0 42.984 0.084 ;
    END
  END vr2q[360]
  PIN vr2q[361]
    DIRECTION OUTPUT ;
    USE SIGNAL ;
    PORT
      LAYER M5 ;
        RECT  43.056 0 43.08 0.084 ;
    END
  END vr2q[361]
  PIN vr2q[362]
    DIRECTION OUTPUT ;
    USE SIGNAL ;
    PORT
      LAYER M5 ;
        RECT  43.152 0 43.176 0.084 ;
    END
  END vr2q[362]
  PIN vr2q[363]
    DIRECTION OUTPUT ;
    USE SIGNAL ;
    PORT
      LAYER M5 ;
        RECT  43.248 0 43.272 0.084 ;
    END
  END vr2q[363]
  PIN vr2q[364]
    DIRECTION OUTPUT ;
    USE SIGNAL ;
    PORT
      LAYER M5 ;
        RECT  43.344 0 43.368 0.084 ;
    END
  END vr2q[364]
  PIN vr2q[365]
    DIRECTION OUTPUT ;
    USE SIGNAL ;
    PORT
      LAYER M5 ;
        RECT  43.44 0 43.464 0.084 ;
    END
  END vr2q[365]
  PIN vr2q[366]
    DIRECTION OUTPUT ;
    USE SIGNAL ;
    PORT
      LAYER M5 ;
        RECT  43.536 0 43.56 0.084 ;
    END
  END vr2q[366]
  PIN vr2q[367]
    DIRECTION OUTPUT ;
    USE SIGNAL ;
    PORT
      LAYER M5 ;
        RECT  43.632 0 43.656 0.084 ;
    END
  END vr2q[367]
  PIN vr2q[368]
    DIRECTION OUTPUT ;
    USE SIGNAL ;
    PORT
      LAYER M5 ;
        RECT  43.728 0 43.752 0.084 ;
    END
  END vr2q[368]
  PIN vr2q[369]
    DIRECTION OUTPUT ;
    USE SIGNAL ;
    PORT
      LAYER M5 ;
        RECT  43.824 0 43.848 0.084 ;
    END
  END vr2q[369]
  PIN vr2q[36]
    DIRECTION OUTPUT ;
    USE SIGNAL ;
    PORT
      LAYER M5 ;
        RECT  20.304 0 20.328 0.084 ;
    END
  END vr2q[36]
  PIN vr2q[370]
    DIRECTION OUTPUT ;
    USE SIGNAL ;
    PORT
      LAYER M5 ;
        RECT  43.92 0 43.944 0.084 ;
    END
  END vr2q[370]
  PIN vr2q[371]
    DIRECTION OUTPUT ;
    USE SIGNAL ;
    PORT
      LAYER M5 ;
        RECT  44.016 0 44.04 0.084 ;
    END
  END vr2q[371]
  PIN vr2q[372]
    DIRECTION OUTPUT ;
    USE SIGNAL ;
    PORT
      LAYER M5 ;
        RECT  44.112 0 44.136 0.084 ;
    END
  END vr2q[372]
  PIN vr2q[373]
    DIRECTION OUTPUT ;
    USE SIGNAL ;
    PORT
      LAYER M5 ;
        RECT  44.208 0 44.232 0.084 ;
    END
  END vr2q[373]
  PIN vr2q[374]
    DIRECTION OUTPUT ;
    USE SIGNAL ;
    PORT
      LAYER M5 ;
        RECT  44.304 0 44.328 0.084 ;
    END
  END vr2q[374]
  PIN vr2q[375]
    DIRECTION OUTPUT ;
    USE SIGNAL ;
    PORT
      LAYER M5 ;
        RECT  44.4 0 44.424 0.084 ;
    END
  END vr2q[375]
  PIN vr2q[376]
    DIRECTION OUTPUT ;
    USE SIGNAL ;
    PORT
      LAYER M5 ;
        RECT  44.496 0 44.52 0.084 ;
    END
  END vr2q[376]
  PIN vr2q[377]
    DIRECTION OUTPUT ;
    USE SIGNAL ;
    PORT
      LAYER M5 ;
        RECT  44.592 0 44.616 0.084 ;
    END
  END vr2q[377]
  PIN vr2q[378]
    DIRECTION OUTPUT ;
    USE SIGNAL ;
    PORT
      LAYER M5 ;
        RECT  44.688 0 44.712 0.084 ;
    END
  END vr2q[378]
  PIN vr2q[379]
    DIRECTION OUTPUT ;
    USE SIGNAL ;
    PORT
      LAYER M5 ;
        RECT  44.784 0 44.808 0.084 ;
    END
  END vr2q[379]
  PIN vr2q[37]
    DIRECTION OUTPUT ;
    USE SIGNAL ;
    PORT
      LAYER M5 ;
        RECT  20.4 0 20.424 0.084 ;
    END
  END vr2q[37]
  PIN vr2q[380]
    DIRECTION OUTPUT ;
    USE SIGNAL ;
    PORT
      LAYER M5 ;
        RECT  44.88 0 44.904 0.084 ;
    END
  END vr2q[380]
  PIN vr2q[381]
    DIRECTION OUTPUT ;
    USE SIGNAL ;
    PORT
      LAYER M5 ;
        RECT  44.976 0 45 0.084 ;
    END
  END vr2q[381]
  PIN vr2q[382]
    DIRECTION OUTPUT ;
    USE SIGNAL ;
    PORT
      LAYER M5 ;
        RECT  45.072 0 45.096 0.084 ;
    END
  END vr2q[382]
  PIN vr2q[383]
    DIRECTION OUTPUT ;
    USE SIGNAL ;
    PORT
      LAYER M5 ;
        RECT  45.168 0 45.192 0.084 ;
    END
  END vr2q[383]
  PIN vr2q[384]
    DIRECTION OUTPUT ;
    USE SIGNAL ;
    PORT
      LAYER M5 ;
        RECT  13.008 0 13.032 0.084 ;
    END
  END vr2q[384]
  PIN vr2q[385]
    DIRECTION OUTPUT ;
    USE SIGNAL ;
    PORT
      LAYER M5 ;
        RECT  13.104 0 13.128 0.084 ;
    END
  END vr2q[385]
  PIN vr2q[386]
    DIRECTION OUTPUT ;
    USE SIGNAL ;
    PORT
      LAYER M5 ;
        RECT  13.2 0 13.224 0.084 ;
    END
  END vr2q[386]
  PIN vr2q[387]
    DIRECTION OUTPUT ;
    USE SIGNAL ;
    PORT
      LAYER M5 ;
        RECT  13.296 0 13.32 0.084 ;
    END
  END vr2q[387]
  PIN vr2q[388]
    DIRECTION OUTPUT ;
    USE SIGNAL ;
    PORT
      LAYER M5 ;
        RECT  13.392 0 13.416 0.084 ;
    END
  END vr2q[388]
  PIN vr2q[389]
    DIRECTION OUTPUT ;
    USE SIGNAL ;
    PORT
      LAYER M5 ;
        RECT  13.488 0 13.512 0.084 ;
    END
  END vr2q[389]
  PIN vr2q[38]
    DIRECTION OUTPUT ;
    USE SIGNAL ;
    PORT
      LAYER M5 ;
        RECT  20.496 0 20.52 0.084 ;
    END
  END vr2q[38]
  PIN vr2q[390]
    DIRECTION OUTPUT ;
    USE SIGNAL ;
    PORT
      LAYER M5 ;
        RECT  13.584 0 13.608 0.084 ;
    END
  END vr2q[390]
  PIN vr2q[391]
    DIRECTION OUTPUT ;
    USE SIGNAL ;
    PORT
      LAYER M5 ;
        RECT  13.68 0 13.704 0.084 ;
    END
  END vr2q[391]
  PIN vr2q[392]
    DIRECTION OUTPUT ;
    USE SIGNAL ;
    PORT
      LAYER M5 ;
        RECT  13.776 0 13.8 0.084 ;
    END
  END vr2q[392]
  PIN vr2q[393]
    DIRECTION OUTPUT ;
    USE SIGNAL ;
    PORT
      LAYER M5 ;
        RECT  13.872 0 13.896 0.084 ;
    END
  END vr2q[393]
  PIN vr2q[394]
    DIRECTION OUTPUT ;
    USE SIGNAL ;
    PORT
      LAYER M5 ;
        RECT  13.968 0 13.992 0.084 ;
    END
  END vr2q[394]
  PIN vr2q[395]
    DIRECTION OUTPUT ;
    USE SIGNAL ;
    PORT
      LAYER M5 ;
        RECT  14.064 0 14.088 0.084 ;
    END
  END vr2q[395]
  PIN vr2q[396]
    DIRECTION OUTPUT ;
    USE SIGNAL ;
    PORT
      LAYER M5 ;
        RECT  14.16 0 14.184 0.084 ;
    END
  END vr2q[396]
  PIN vr2q[397]
    DIRECTION OUTPUT ;
    USE SIGNAL ;
    PORT
      LAYER M5 ;
        RECT  14.256 0 14.28 0.084 ;
    END
  END vr2q[397]
  PIN vr2q[398]
    DIRECTION OUTPUT ;
    USE SIGNAL ;
    PORT
      LAYER M5 ;
        RECT  14.352 0 14.376 0.084 ;
    END
  END vr2q[398]
  PIN vr2q[399]
    DIRECTION OUTPUT ;
    USE SIGNAL ;
    PORT
      LAYER M5 ;
        RECT  14.448 0 14.472 0.084 ;
    END
  END vr2q[399]
  PIN vr2q[39]
    DIRECTION OUTPUT ;
    USE SIGNAL ;
    PORT
      LAYER M5 ;
        RECT  20.592 0 20.616 0.084 ;
    END
  END vr2q[39]
  PIN vr2q[3]
    DIRECTION OUTPUT ;
    USE SIGNAL ;
    PORT
      LAYER M5 ;
        RECT  26.352 0 26.376 0.084 ;
    END
  END vr2q[3]
  PIN vr2q[400]
    DIRECTION OUTPUT ;
    USE SIGNAL ;
    PORT
      LAYER M5 ;
        RECT  14.544 0 14.568 0.084 ;
    END
  END vr2q[400]
  PIN vr2q[401]
    DIRECTION OUTPUT ;
    USE SIGNAL ;
    PORT
      LAYER M5 ;
        RECT  14.64 0 14.664 0.084 ;
    END
  END vr2q[401]
  PIN vr2q[402]
    DIRECTION OUTPUT ;
    USE SIGNAL ;
    PORT
      LAYER M5 ;
        RECT  14.736 0 14.76 0.084 ;
    END
  END vr2q[402]
  PIN vr2q[403]
    DIRECTION OUTPUT ;
    USE SIGNAL ;
    PORT
      LAYER M5 ;
        RECT  14.832 0 14.856 0.084 ;
    END
  END vr2q[403]
  PIN vr2q[404]
    DIRECTION OUTPUT ;
    USE SIGNAL ;
    PORT
      LAYER M5 ;
        RECT  14.928 0 14.952 0.084 ;
    END
  END vr2q[404]
  PIN vr2q[405]
    DIRECTION OUTPUT ;
    USE SIGNAL ;
    PORT
      LAYER M5 ;
        RECT  15.024 0 15.048 0.084 ;
    END
  END vr2q[405]
  PIN vr2q[406]
    DIRECTION OUTPUT ;
    USE SIGNAL ;
    PORT
      LAYER M5 ;
        RECT  15.12 0 15.144 0.084 ;
    END
  END vr2q[406]
  PIN vr2q[407]
    DIRECTION OUTPUT ;
    USE SIGNAL ;
    PORT
      LAYER M5 ;
        RECT  15.216 0 15.24 0.084 ;
    END
  END vr2q[407]
  PIN vr2q[408]
    DIRECTION OUTPUT ;
    USE SIGNAL ;
    PORT
      LAYER M5 ;
        RECT  15.312 0 15.336 0.084 ;
    END
  END vr2q[408]
  PIN vr2q[409]
    DIRECTION OUTPUT ;
    USE SIGNAL ;
    PORT
      LAYER M5 ;
        RECT  15.408 0 15.432 0.084 ;
    END
  END vr2q[409]
  PIN vr2q[40]
    DIRECTION OUTPUT ;
    USE SIGNAL ;
    PORT
      LAYER M5 ;
        RECT  20.688 0 20.712 0.084 ;
    END
  END vr2q[40]
  PIN vr2q[410]
    DIRECTION OUTPUT ;
    USE SIGNAL ;
    PORT
      LAYER M5 ;
        RECT  15.504 0 15.528 0.084 ;
    END
  END vr2q[410]
  PIN vr2q[411]
    DIRECTION OUTPUT ;
    USE SIGNAL ;
    PORT
      LAYER M5 ;
        RECT  15.6 0 15.624 0.084 ;
    END
  END vr2q[411]
  PIN vr2q[412]
    DIRECTION OUTPUT ;
    USE SIGNAL ;
    PORT
      LAYER M5 ;
        RECT  15.696 0 15.72 0.084 ;
    END
  END vr2q[412]
  PIN vr2q[413]
    DIRECTION OUTPUT ;
    USE SIGNAL ;
    PORT
      LAYER M5 ;
        RECT  15.792 0 15.816 0.084 ;
    END
  END vr2q[413]
  PIN vr2q[414]
    DIRECTION OUTPUT ;
    USE SIGNAL ;
    PORT
      LAYER M5 ;
        RECT  15.888 0 15.912 0.084 ;
    END
  END vr2q[414]
  PIN vr2q[415]
    DIRECTION OUTPUT ;
    USE SIGNAL ;
    PORT
      LAYER M5 ;
        RECT  15.984 0 16.008 0.084 ;
    END
  END vr2q[415]
  PIN vr2q[416]
    DIRECTION OUTPUT ;
    USE SIGNAL ;
    PORT
      LAYER M5 ;
        RECT  9.936 0 9.96 0.084 ;
    END
  END vr2q[416]
  PIN vr2q[417]
    DIRECTION OUTPUT ;
    USE SIGNAL ;
    PORT
      LAYER M5 ;
        RECT  10.032 0 10.056 0.084 ;
    END
  END vr2q[417]
  PIN vr2q[418]
    DIRECTION OUTPUT ;
    USE SIGNAL ;
    PORT
      LAYER M5 ;
        RECT  10.128 0 10.152 0.084 ;
    END
  END vr2q[418]
  PIN vr2q[419]
    DIRECTION OUTPUT ;
    USE SIGNAL ;
    PORT
      LAYER M5 ;
        RECT  10.224 0 10.248 0.084 ;
    END
  END vr2q[419]
  PIN vr2q[41]
    DIRECTION OUTPUT ;
    USE SIGNAL ;
    PORT
      LAYER M5 ;
        RECT  20.784 0 20.808 0.084 ;
    END
  END vr2q[41]
  PIN vr2q[420]
    DIRECTION OUTPUT ;
    USE SIGNAL ;
    PORT
      LAYER M5 ;
        RECT  10.32 0 10.344 0.084 ;
    END
  END vr2q[420]
  PIN vr2q[421]
    DIRECTION OUTPUT ;
    USE SIGNAL ;
    PORT
      LAYER M5 ;
        RECT  10.416 0 10.44 0.084 ;
    END
  END vr2q[421]
  PIN vr2q[422]
    DIRECTION OUTPUT ;
    USE SIGNAL ;
    PORT
      LAYER M5 ;
        RECT  10.512 0 10.536 0.084 ;
    END
  END vr2q[422]
  PIN vr2q[423]
    DIRECTION OUTPUT ;
    USE SIGNAL ;
    PORT
      LAYER M5 ;
        RECT  10.608 0 10.632 0.084 ;
    END
  END vr2q[423]
  PIN vr2q[424]
    DIRECTION OUTPUT ;
    USE SIGNAL ;
    PORT
      LAYER M5 ;
        RECT  10.704 0 10.728 0.084 ;
    END
  END vr2q[424]
  PIN vr2q[425]
    DIRECTION OUTPUT ;
    USE SIGNAL ;
    PORT
      LAYER M5 ;
        RECT  10.8 0 10.824 0.084 ;
    END
  END vr2q[425]
  PIN vr2q[426]
    DIRECTION OUTPUT ;
    USE SIGNAL ;
    PORT
      LAYER M5 ;
        RECT  10.896 0 10.92 0.084 ;
    END
  END vr2q[426]
  PIN vr2q[427]
    DIRECTION OUTPUT ;
    USE SIGNAL ;
    PORT
      LAYER M5 ;
        RECT  10.992 0 11.016 0.084 ;
    END
  END vr2q[427]
  PIN vr2q[428]
    DIRECTION OUTPUT ;
    USE SIGNAL ;
    PORT
      LAYER M5 ;
        RECT  11.088 0 11.112 0.084 ;
    END
  END vr2q[428]
  PIN vr2q[429]
    DIRECTION OUTPUT ;
    USE SIGNAL ;
    PORT
      LAYER M5 ;
        RECT  11.184 0 11.208 0.084 ;
    END
  END vr2q[429]
  PIN vr2q[42]
    DIRECTION OUTPUT ;
    USE SIGNAL ;
    PORT
      LAYER M5 ;
        RECT  20.88 0 20.904 0.084 ;
    END
  END vr2q[42]
  PIN vr2q[430]
    DIRECTION OUTPUT ;
    USE SIGNAL ;
    PORT
      LAYER M5 ;
        RECT  11.28 0 11.304 0.084 ;
    END
  END vr2q[430]
  PIN vr2q[431]
    DIRECTION OUTPUT ;
    USE SIGNAL ;
    PORT
      LAYER M5 ;
        RECT  11.376 0 11.4 0.084 ;
    END
  END vr2q[431]
  PIN vr2q[432]
    DIRECTION OUTPUT ;
    USE SIGNAL ;
    PORT
      LAYER M5 ;
        RECT  11.472 0 11.496 0.084 ;
    END
  END vr2q[432]
  PIN vr2q[433]
    DIRECTION OUTPUT ;
    USE SIGNAL ;
    PORT
      LAYER M5 ;
        RECT  11.568 0 11.592 0.084 ;
    END
  END vr2q[433]
  PIN vr2q[434]
    DIRECTION OUTPUT ;
    USE SIGNAL ;
    PORT
      LAYER M5 ;
        RECT  11.664 0 11.688 0.084 ;
    END
  END vr2q[434]
  PIN vr2q[435]
    DIRECTION OUTPUT ;
    USE SIGNAL ;
    PORT
      LAYER M5 ;
        RECT  11.76 0 11.784 0.084 ;
    END
  END vr2q[435]
  PIN vr2q[436]
    DIRECTION OUTPUT ;
    USE SIGNAL ;
    PORT
      LAYER M5 ;
        RECT  11.856 0 11.88 0.084 ;
    END
  END vr2q[436]
  PIN vr2q[437]
    DIRECTION OUTPUT ;
    USE SIGNAL ;
    PORT
      LAYER M5 ;
        RECT  11.952 0 11.976 0.084 ;
    END
  END vr2q[437]
  PIN vr2q[438]
    DIRECTION OUTPUT ;
    USE SIGNAL ;
    PORT
      LAYER M5 ;
        RECT  12.048 0 12.072 0.084 ;
    END
  END vr2q[438]
  PIN vr2q[439]
    DIRECTION OUTPUT ;
    USE SIGNAL ;
    PORT
      LAYER M5 ;
        RECT  12.144 0 12.168 0.084 ;
    END
  END vr2q[439]
  PIN vr2q[43]
    DIRECTION OUTPUT ;
    USE SIGNAL ;
    PORT
      LAYER M5 ;
        RECT  20.976 0 21 0.084 ;
    END
  END vr2q[43]
  PIN vr2q[440]
    DIRECTION OUTPUT ;
    USE SIGNAL ;
    PORT
      LAYER M5 ;
        RECT  12.24 0 12.264 0.084 ;
    END
  END vr2q[440]
  PIN vr2q[441]
    DIRECTION OUTPUT ;
    USE SIGNAL ;
    PORT
      LAYER M5 ;
        RECT  12.336 0 12.36 0.084 ;
    END
  END vr2q[441]
  PIN vr2q[442]
    DIRECTION OUTPUT ;
    USE SIGNAL ;
    PORT
      LAYER M5 ;
        RECT  12.432 0 12.456 0.084 ;
    END
  END vr2q[442]
  PIN vr2q[443]
    DIRECTION OUTPUT ;
    USE SIGNAL ;
    PORT
      LAYER M5 ;
        RECT  12.528 0 12.552 0.084 ;
    END
  END vr2q[443]
  PIN vr2q[444]
    DIRECTION OUTPUT ;
    USE SIGNAL ;
    PORT
      LAYER M5 ;
        RECT  12.624 0 12.648 0.084 ;
    END
  END vr2q[444]
  PIN vr2q[445]
    DIRECTION OUTPUT ;
    USE SIGNAL ;
    PORT
      LAYER M5 ;
        RECT  12.72 0 12.744 0.084 ;
    END
  END vr2q[445]
  PIN vr2q[446]
    DIRECTION OUTPUT ;
    USE SIGNAL ;
    PORT
      LAYER M5 ;
        RECT  12.816 0 12.84 0.084 ;
    END
  END vr2q[446]
  PIN vr2q[447]
    DIRECTION OUTPUT ;
    USE SIGNAL ;
    PORT
      LAYER M5 ;
        RECT  12.912 0 12.936 0.084 ;
    END
  END vr2q[447]
  PIN vr2q[448]
    DIRECTION OUTPUT ;
    USE SIGNAL ;
    PORT
      LAYER M5 ;
        RECT  6.864 0 6.888 0.084 ;
    END
  END vr2q[448]
  PIN vr2q[449]
    DIRECTION OUTPUT ;
    USE SIGNAL ;
    PORT
      LAYER M5 ;
        RECT  6.96 0 6.984 0.084 ;
    END
  END vr2q[449]
  PIN vr2q[44]
    DIRECTION OUTPUT ;
    USE SIGNAL ;
    PORT
      LAYER M5 ;
        RECT  21.072 0 21.096 0.084 ;
    END
  END vr2q[44]
  PIN vr2q[450]
    DIRECTION OUTPUT ;
    USE SIGNAL ;
    PORT
      LAYER M5 ;
        RECT  7.056 0 7.08 0.084 ;
    END
  END vr2q[450]
  PIN vr2q[451]
    DIRECTION OUTPUT ;
    USE SIGNAL ;
    PORT
      LAYER M5 ;
        RECT  7.152 0 7.176 0.084 ;
    END
  END vr2q[451]
  PIN vr2q[452]
    DIRECTION OUTPUT ;
    USE SIGNAL ;
    PORT
      LAYER M5 ;
        RECT  7.248 0 7.272 0.084 ;
    END
  END vr2q[452]
  PIN vr2q[453]
    DIRECTION OUTPUT ;
    USE SIGNAL ;
    PORT
      LAYER M5 ;
        RECT  7.344 0 7.368 0.084 ;
    END
  END vr2q[453]
  PIN vr2q[454]
    DIRECTION OUTPUT ;
    USE SIGNAL ;
    PORT
      LAYER M5 ;
        RECT  7.44 0 7.464 0.084 ;
    END
  END vr2q[454]
  PIN vr2q[455]
    DIRECTION OUTPUT ;
    USE SIGNAL ;
    PORT
      LAYER M5 ;
        RECT  7.536 0 7.56 0.084 ;
    END
  END vr2q[455]
  PIN vr2q[456]
    DIRECTION OUTPUT ;
    USE SIGNAL ;
    PORT
      LAYER M5 ;
        RECT  7.632 0 7.656 0.084 ;
    END
  END vr2q[456]
  PIN vr2q[457]
    DIRECTION OUTPUT ;
    USE SIGNAL ;
    PORT
      LAYER M5 ;
        RECT  7.728 0 7.752 0.084 ;
    END
  END vr2q[457]
  PIN vr2q[458]
    DIRECTION OUTPUT ;
    USE SIGNAL ;
    PORT
      LAYER M5 ;
        RECT  7.824 0 7.848 0.084 ;
    END
  END vr2q[458]
  PIN vr2q[459]
    DIRECTION OUTPUT ;
    USE SIGNAL ;
    PORT
      LAYER M5 ;
        RECT  7.92 0 7.944 0.084 ;
    END
  END vr2q[459]
  PIN vr2q[45]
    DIRECTION OUTPUT ;
    USE SIGNAL ;
    PORT
      LAYER M5 ;
        RECT  21.168 0 21.192 0.084 ;
    END
  END vr2q[45]
  PIN vr2q[460]
    DIRECTION OUTPUT ;
    USE SIGNAL ;
    PORT
      LAYER M5 ;
        RECT  8.016 0 8.04 0.084 ;
    END
  END vr2q[460]
  PIN vr2q[461]
    DIRECTION OUTPUT ;
    USE SIGNAL ;
    PORT
      LAYER M5 ;
        RECT  8.112 0 8.136 0.084 ;
    END
  END vr2q[461]
  PIN vr2q[462]
    DIRECTION OUTPUT ;
    USE SIGNAL ;
    PORT
      LAYER M5 ;
        RECT  8.208 0 8.232 0.084 ;
    END
  END vr2q[462]
  PIN vr2q[463]
    DIRECTION OUTPUT ;
    USE SIGNAL ;
    PORT
      LAYER M5 ;
        RECT  8.304 0 8.328 0.084 ;
    END
  END vr2q[463]
  PIN vr2q[464]
    DIRECTION OUTPUT ;
    USE SIGNAL ;
    PORT
      LAYER M5 ;
        RECT  8.4 0 8.424 0.084 ;
    END
  END vr2q[464]
  PIN vr2q[465]
    DIRECTION OUTPUT ;
    USE SIGNAL ;
    PORT
      LAYER M5 ;
        RECT  8.496 0 8.52 0.084 ;
    END
  END vr2q[465]
  PIN vr2q[466]
    DIRECTION OUTPUT ;
    USE SIGNAL ;
    PORT
      LAYER M5 ;
        RECT  8.592 0 8.616 0.084 ;
    END
  END vr2q[466]
  PIN vr2q[467]
    DIRECTION OUTPUT ;
    USE SIGNAL ;
    PORT
      LAYER M5 ;
        RECT  8.688 0 8.712 0.084 ;
    END
  END vr2q[467]
  PIN vr2q[468]
    DIRECTION OUTPUT ;
    USE SIGNAL ;
    PORT
      LAYER M5 ;
        RECT  8.784 0 8.808 0.084 ;
    END
  END vr2q[468]
  PIN vr2q[469]
    DIRECTION OUTPUT ;
    USE SIGNAL ;
    PORT
      LAYER M5 ;
        RECT  8.88 0 8.904 0.084 ;
    END
  END vr2q[469]
  PIN vr2q[46]
    DIRECTION OUTPUT ;
    USE SIGNAL ;
    PORT
      LAYER M5 ;
        RECT  21.264 0 21.288 0.084 ;
    END
  END vr2q[46]
  PIN vr2q[470]
    DIRECTION OUTPUT ;
    USE SIGNAL ;
    PORT
      LAYER M5 ;
        RECT  8.976 0 9 0.084 ;
    END
  END vr2q[470]
  PIN vr2q[471]
    DIRECTION OUTPUT ;
    USE SIGNAL ;
    PORT
      LAYER M5 ;
        RECT  9.072 0 9.096 0.084 ;
    END
  END vr2q[471]
  PIN vr2q[472]
    DIRECTION OUTPUT ;
    USE SIGNAL ;
    PORT
      LAYER M5 ;
        RECT  9.168 0 9.192 0.084 ;
    END
  END vr2q[472]
  PIN vr2q[473]
    DIRECTION OUTPUT ;
    USE SIGNAL ;
    PORT
      LAYER M5 ;
        RECT  9.264 0 9.288 0.084 ;
    END
  END vr2q[473]
  PIN vr2q[474]
    DIRECTION OUTPUT ;
    USE SIGNAL ;
    PORT
      LAYER M5 ;
        RECT  9.36 0 9.384 0.084 ;
    END
  END vr2q[474]
  PIN vr2q[475]
    DIRECTION OUTPUT ;
    USE SIGNAL ;
    PORT
      LAYER M5 ;
        RECT  9.456 0 9.48 0.084 ;
    END
  END vr2q[475]
  PIN vr2q[476]
    DIRECTION OUTPUT ;
    USE SIGNAL ;
    PORT
      LAYER M5 ;
        RECT  9.552 0 9.576 0.084 ;
    END
  END vr2q[476]
  PIN vr2q[477]
    DIRECTION OUTPUT ;
    USE SIGNAL ;
    PORT
      LAYER M5 ;
        RECT  9.648 0 9.672 0.084 ;
    END
  END vr2q[477]
  PIN vr2q[478]
    DIRECTION OUTPUT ;
    USE SIGNAL ;
    PORT
      LAYER M5 ;
        RECT  9.744 0 9.768 0.084 ;
    END
  END vr2q[478]
  PIN vr2q[479]
    DIRECTION OUTPUT ;
    USE SIGNAL ;
    PORT
      LAYER M5 ;
        RECT  9.84 0 9.864 0.084 ;
    END
  END vr2q[479]
  PIN vr2q[47]
    DIRECTION OUTPUT ;
    USE SIGNAL ;
    PORT
      LAYER M5 ;
        RECT  21.36 0 21.384 0.084 ;
    END
  END vr2q[47]
  PIN vr2q[480]
    DIRECTION OUTPUT ;
    USE SIGNAL ;
    PORT
      LAYER M5 ;
        RECT  16.08 0 16.104 0.084 ;
    END
  END vr2q[480]
  PIN vr2q[481]
    DIRECTION OUTPUT ;
    USE SIGNAL ;
    PORT
      LAYER M5 ;
        RECT  16.176 0 16.2 0.084 ;
    END
  END vr2q[481]
  PIN vr2q[482]
    DIRECTION OUTPUT ;
    USE SIGNAL ;
    PORT
      LAYER M5 ;
        RECT  16.272 0 16.296 0.084 ;
    END
  END vr2q[482]
  PIN vr2q[483]
    DIRECTION OUTPUT ;
    USE SIGNAL ;
    PORT
      LAYER M5 ;
        RECT  16.368 0 16.392 0.084 ;
    END
  END vr2q[483]
  PIN vr2q[484]
    DIRECTION OUTPUT ;
    USE SIGNAL ;
    PORT
      LAYER M5 ;
        RECT  16.464 0 16.488 0.084 ;
    END
  END vr2q[484]
  PIN vr2q[485]
    DIRECTION OUTPUT ;
    USE SIGNAL ;
    PORT
      LAYER M5 ;
        RECT  16.56 0 16.584 0.084 ;
    END
  END vr2q[485]
  PIN vr2q[486]
    DIRECTION OUTPUT ;
    USE SIGNAL ;
    PORT
      LAYER M5 ;
        RECT  16.656 0 16.68 0.084 ;
    END
  END vr2q[486]
  PIN vr2q[487]
    DIRECTION OUTPUT ;
    USE SIGNAL ;
    PORT
      LAYER M5 ;
        RECT  16.752 0 16.776 0.084 ;
    END
  END vr2q[487]
  PIN vr2q[488]
    DIRECTION OUTPUT ;
    USE SIGNAL ;
    PORT
      LAYER M5 ;
        RECT  16.848 0 16.872 0.084 ;
    END
  END vr2q[488]
  PIN vr2q[489]
    DIRECTION OUTPUT ;
    USE SIGNAL ;
    PORT
      LAYER M5 ;
        RECT  16.944 0 16.968 0.084 ;
    END
  END vr2q[489]
  PIN vr2q[48]
    DIRECTION OUTPUT ;
    USE SIGNAL ;
    PORT
      LAYER M5 ;
        RECT  21.456 0 21.48 0.084 ;
    END
  END vr2q[48]
  PIN vr2q[490]
    DIRECTION OUTPUT ;
    USE SIGNAL ;
    PORT
      LAYER M5 ;
        RECT  17.04 0 17.064 0.084 ;
    END
  END vr2q[490]
  PIN vr2q[491]
    DIRECTION OUTPUT ;
    USE SIGNAL ;
    PORT
      LAYER M5 ;
        RECT  17.136 0 17.16 0.084 ;
    END
  END vr2q[491]
  PIN vr2q[492]
    DIRECTION OUTPUT ;
    USE SIGNAL ;
    PORT
      LAYER M5 ;
        RECT  17.232 0 17.256 0.084 ;
    END
  END vr2q[492]
  PIN vr2q[493]
    DIRECTION OUTPUT ;
    USE SIGNAL ;
    PORT
      LAYER M5 ;
        RECT  17.328 0 17.352 0.084 ;
    END
  END vr2q[493]
  PIN vr2q[494]
    DIRECTION OUTPUT ;
    USE SIGNAL ;
    PORT
      LAYER M5 ;
        RECT  17.424 0 17.448 0.084 ;
    END
  END vr2q[494]
  PIN vr2q[495]
    DIRECTION OUTPUT ;
    USE SIGNAL ;
    PORT
      LAYER M5 ;
        RECT  17.52 0 17.544 0.084 ;
    END
  END vr2q[495]
  PIN vr2q[496]
    DIRECTION OUTPUT ;
    USE SIGNAL ;
    PORT
      LAYER M5 ;
        RECT  17.616 0 17.64 0.084 ;
    END
  END vr2q[496]
  PIN vr2q[497]
    DIRECTION OUTPUT ;
    USE SIGNAL ;
    PORT
      LAYER M5 ;
        RECT  17.712 0 17.736 0.084 ;
    END
  END vr2q[497]
  PIN vr2q[498]
    DIRECTION OUTPUT ;
    USE SIGNAL ;
    PORT
      LAYER M5 ;
        RECT  17.808 0 17.832 0.084 ;
    END
  END vr2q[498]
  PIN vr2q[499]
    DIRECTION OUTPUT ;
    USE SIGNAL ;
    PORT
      LAYER M5 ;
        RECT  17.904 0 17.928 0.084 ;
    END
  END vr2q[499]
  PIN vr2q[49]
    DIRECTION OUTPUT ;
    USE SIGNAL ;
    PORT
      LAYER M5 ;
        RECT  21.552 0 21.576 0.084 ;
    END
  END vr2q[49]
  PIN vr2q[4]
    DIRECTION OUTPUT ;
    USE SIGNAL ;
    PORT
      LAYER M5 ;
        RECT  26.448 0 26.472 0.084 ;
    END
  END vr2q[4]
  PIN vr2q[500]
    DIRECTION OUTPUT ;
    USE SIGNAL ;
    PORT
      LAYER M5 ;
        RECT  18 0 18.024 0.084 ;
    END
  END vr2q[500]
  PIN vr2q[501]
    DIRECTION OUTPUT ;
    USE SIGNAL ;
    PORT
      LAYER M5 ;
        RECT  18.096 0 18.12 0.084 ;
    END
  END vr2q[501]
  PIN vr2q[502]
    DIRECTION OUTPUT ;
    USE SIGNAL ;
    PORT
      LAYER M5 ;
        RECT  18.192 0 18.216 0.084 ;
    END
  END vr2q[502]
  PIN vr2q[503]
    DIRECTION OUTPUT ;
    USE SIGNAL ;
    PORT
      LAYER M5 ;
        RECT  18.288 0 18.312 0.084 ;
    END
  END vr2q[503]
  PIN vr2q[504]
    DIRECTION OUTPUT ;
    USE SIGNAL ;
    PORT
      LAYER M5 ;
        RECT  18.384 0 18.408 0.084 ;
    END
  END vr2q[504]
  PIN vr2q[505]
    DIRECTION OUTPUT ;
    USE SIGNAL ;
    PORT
      LAYER M5 ;
        RECT  18.48 0 18.504 0.084 ;
    END
  END vr2q[505]
  PIN vr2q[506]
    DIRECTION OUTPUT ;
    USE SIGNAL ;
    PORT
      LAYER M5 ;
        RECT  18.576 0 18.6 0.084 ;
    END
  END vr2q[506]
  PIN vr2q[507]
    DIRECTION OUTPUT ;
    USE SIGNAL ;
    PORT
      LAYER M5 ;
        RECT  18.672 0 18.696 0.084 ;
    END
  END vr2q[507]
  PIN vr2q[508]
    DIRECTION OUTPUT ;
    USE SIGNAL ;
    PORT
      LAYER M5 ;
        RECT  18.768 0 18.792 0.084 ;
    END
  END vr2q[508]
  PIN vr2q[509]
    DIRECTION OUTPUT ;
    USE SIGNAL ;
    PORT
      LAYER M5 ;
        RECT  18.864 0 18.888 0.084 ;
    END
  END vr2q[509]
  PIN vr2q[50]
    DIRECTION OUTPUT ;
    USE SIGNAL ;
    PORT
      LAYER M5 ;
        RECT  21.648 0 21.672 0.084 ;
    END
  END vr2q[50]
  PIN vr2q[510]
    DIRECTION OUTPUT ;
    USE SIGNAL ;
    PORT
      LAYER M5 ;
        RECT  18.96 0 18.984 0.084 ;
    END
  END vr2q[510]
  PIN vr2q[511]
    DIRECTION OUTPUT ;
    USE SIGNAL ;
    PORT
      LAYER M5 ;
        RECT  19.056 0 19.08 0.084 ;
    END
  END vr2q[511]
  PIN vr2q[512]
    DIRECTION OUTPUT ;
    USE SIGNAL ;
    PORT
      LAYER M5 ;
        RECT  57.552 0 57.576 0.084 ;
    END
  END vr2q[512]
  PIN vr2q[51]
    DIRECTION OUTPUT ;
    USE SIGNAL ;
    PORT
      LAYER M5 ;
        RECT  21.744 0 21.768 0.084 ;
    END
  END vr2q[51]
  PIN vr2q[52]
    DIRECTION OUTPUT ;
    USE SIGNAL ;
    PORT
      LAYER M5 ;
        RECT  21.84 0 21.864 0.084 ;
    END
  END vr2q[52]
  PIN vr2q[53]
    DIRECTION OUTPUT ;
    USE SIGNAL ;
    PORT
      LAYER M5 ;
        RECT  21.936 0 21.96 0.084 ;
    END
  END vr2q[53]
  PIN vr2q[54]
    DIRECTION OUTPUT ;
    USE SIGNAL ;
    PORT
      LAYER M5 ;
        RECT  22.032 0 22.056 0.084 ;
    END
  END vr2q[54]
  PIN vr2q[55]
    DIRECTION OUTPUT ;
    USE SIGNAL ;
    PORT
      LAYER M5 ;
        RECT  22.128 0 22.152 0.084 ;
    END
  END vr2q[55]
  PIN vr2q[56]
    DIRECTION OUTPUT ;
    USE SIGNAL ;
    PORT
      LAYER M5 ;
        RECT  22.224 0 22.248 0.084 ;
    END
  END vr2q[56]
  PIN vr2q[57]
    DIRECTION OUTPUT ;
    USE SIGNAL ;
    PORT
      LAYER M5 ;
        RECT  22.32 0 22.344 0.084 ;
    END
  END vr2q[57]
  PIN vr2q[58]
    DIRECTION OUTPUT ;
    USE SIGNAL ;
    PORT
      LAYER M5 ;
        RECT  22.416 0 22.44 0.084 ;
    END
  END vr2q[58]
  PIN vr2q[59]
    DIRECTION OUTPUT ;
    USE SIGNAL ;
    PORT
      LAYER M5 ;
        RECT  22.512 0 22.536 0.084 ;
    END
  END vr2q[59]
  PIN vr2q[5]
    DIRECTION OUTPUT ;
    USE SIGNAL ;
    PORT
      LAYER M5 ;
        RECT  26.544 0 26.568 0.084 ;
    END
  END vr2q[5]
  PIN vr2q[60]
    DIRECTION OUTPUT ;
    USE SIGNAL ;
    PORT
      LAYER M5 ;
        RECT  22.608 0 22.632 0.084 ;
    END
  END vr2q[60]
  PIN vr2q[61]
    DIRECTION OUTPUT ;
    USE SIGNAL ;
    PORT
      LAYER M5 ;
        RECT  22.704 0 22.728 0.084 ;
    END
  END vr2q[61]
  PIN vr2q[62]
    DIRECTION OUTPUT ;
    USE SIGNAL ;
    PORT
      LAYER M5 ;
        RECT  22.8 0 22.824 0.084 ;
    END
  END vr2q[62]
  PIN vr2q[63]
    DIRECTION OUTPUT ;
    USE SIGNAL ;
    PORT
      LAYER M5 ;
        RECT  22.896 0 22.92 0.084 ;
    END
  END vr2q[63]
  PIN vr2q[64]
    DIRECTION OUTPUT ;
    USE SIGNAL ;
    PORT
      LAYER M5 ;
        RECT  29.136 0 29.16 0.084 ;
    END
  END vr2q[64]
  PIN vr2q[65]
    DIRECTION OUTPUT ;
    USE SIGNAL ;
    PORT
      LAYER M5 ;
        RECT  29.232 0 29.256 0.084 ;
    END
  END vr2q[65]
  PIN vr2q[66]
    DIRECTION OUTPUT ;
    USE SIGNAL ;
    PORT
      LAYER M5 ;
        RECT  29.328 0 29.352 0.084 ;
    END
  END vr2q[66]
  PIN vr2q[67]
    DIRECTION OUTPUT ;
    USE SIGNAL ;
    PORT
      LAYER M5 ;
        RECT  29.424 0 29.448 0.084 ;
    END
  END vr2q[67]
  PIN vr2q[68]
    DIRECTION OUTPUT ;
    USE SIGNAL ;
    PORT
      LAYER M5 ;
        RECT  29.52 0 29.544 0.084 ;
    END
  END vr2q[68]
  PIN vr2q[69]
    DIRECTION OUTPUT ;
    USE SIGNAL ;
    PORT
      LAYER M5 ;
        RECT  29.616 0 29.64 0.084 ;
    END
  END vr2q[69]
  PIN vr2q[6]
    DIRECTION OUTPUT ;
    USE SIGNAL ;
    PORT
      LAYER M5 ;
        RECT  26.64 0 26.664 0.084 ;
    END
  END vr2q[6]
  PIN vr2q[70]
    DIRECTION OUTPUT ;
    USE SIGNAL ;
    PORT
      LAYER M5 ;
        RECT  29.712 0 29.736 0.084 ;
    END
  END vr2q[70]
  PIN vr2q[71]
    DIRECTION OUTPUT ;
    USE SIGNAL ;
    PORT
      LAYER M5 ;
        RECT  29.808 0 29.832 0.084 ;
    END
  END vr2q[71]
  PIN vr2q[72]
    DIRECTION OUTPUT ;
    USE SIGNAL ;
    PORT
      LAYER M5 ;
        RECT  29.904 0 29.928 0.084 ;
    END
  END vr2q[72]
  PIN vr2q[73]
    DIRECTION OUTPUT ;
    USE SIGNAL ;
    PORT
      LAYER M5 ;
        RECT  30 0 30.024 0.084 ;
    END
  END vr2q[73]
  PIN vr2q[74]
    DIRECTION OUTPUT ;
    USE SIGNAL ;
    PORT
      LAYER M5 ;
        RECT  30.096 0 30.12 0.084 ;
    END
  END vr2q[74]
  PIN vr2q[75]
    DIRECTION OUTPUT ;
    USE SIGNAL ;
    PORT
      LAYER M5 ;
        RECT  30.192 0 30.216 0.084 ;
    END
  END vr2q[75]
  PIN vr2q[76]
    DIRECTION OUTPUT ;
    USE SIGNAL ;
    PORT
      LAYER M5 ;
        RECT  30.288 0 30.312 0.084 ;
    END
  END vr2q[76]
  PIN vr2q[77]
    DIRECTION OUTPUT ;
    USE SIGNAL ;
    PORT
      LAYER M5 ;
        RECT  30.384 0 30.408 0.084 ;
    END
  END vr2q[77]
  PIN vr2q[78]
    DIRECTION OUTPUT ;
    USE SIGNAL ;
    PORT
      LAYER M5 ;
        RECT  30.48 0 30.504 0.084 ;
    END
  END vr2q[78]
  PIN vr2q[79]
    DIRECTION OUTPUT ;
    USE SIGNAL ;
    PORT
      LAYER M5 ;
        RECT  30.576 0 30.6 0.084 ;
    END
  END vr2q[79]
  PIN vr2q[7]
    DIRECTION OUTPUT ;
    USE SIGNAL ;
    PORT
      LAYER M5 ;
        RECT  26.736 0 26.76 0.084 ;
    END
  END vr2q[7]
  PIN vr2q[80]
    DIRECTION OUTPUT ;
    USE SIGNAL ;
    PORT
      LAYER M5 ;
        RECT  30.672 0 30.696 0.084 ;
    END
  END vr2q[80]
  PIN vr2q[81]
    DIRECTION OUTPUT ;
    USE SIGNAL ;
    PORT
      LAYER M5 ;
        RECT  30.768 0 30.792 0.084 ;
    END
  END vr2q[81]
  PIN vr2q[82]
    DIRECTION OUTPUT ;
    USE SIGNAL ;
    PORT
      LAYER M5 ;
        RECT  30.864 0 30.888 0.084 ;
    END
  END vr2q[82]
  PIN vr2q[83]
    DIRECTION OUTPUT ;
    USE SIGNAL ;
    PORT
      LAYER M5 ;
        RECT  30.96 0 30.984 0.084 ;
    END
  END vr2q[83]
  PIN vr2q[84]
    DIRECTION OUTPUT ;
    USE SIGNAL ;
    PORT
      LAYER M5 ;
        RECT  31.056 0 31.08 0.084 ;
    END
  END vr2q[84]
  PIN vr2q[85]
    DIRECTION OUTPUT ;
    USE SIGNAL ;
    PORT
      LAYER M5 ;
        RECT  31.152 0 31.176 0.084 ;
    END
  END vr2q[85]
  PIN vr2q[86]
    DIRECTION OUTPUT ;
    USE SIGNAL ;
    PORT
      LAYER M5 ;
        RECT  31.248 0 31.272 0.084 ;
    END
  END vr2q[86]
  PIN vr2q[87]
    DIRECTION OUTPUT ;
    USE SIGNAL ;
    PORT
      LAYER M5 ;
        RECT  31.344 0 31.368 0.084 ;
    END
  END vr2q[87]
  PIN vr2q[88]
    DIRECTION OUTPUT ;
    USE SIGNAL ;
    PORT
      LAYER M5 ;
        RECT  31.44 0 31.464 0.084 ;
    END
  END vr2q[88]
  PIN vr2q[89]
    DIRECTION OUTPUT ;
    USE SIGNAL ;
    PORT
      LAYER M5 ;
        RECT  31.536 0 31.56 0.084 ;
    END
  END vr2q[89]
  PIN vr2q[8]
    DIRECTION OUTPUT ;
    USE SIGNAL ;
    PORT
      LAYER M5 ;
        RECT  26.832 0 26.856 0.084 ;
    END
  END vr2q[8]
  PIN vr2q[90]
    DIRECTION OUTPUT ;
    USE SIGNAL ;
    PORT
      LAYER M5 ;
        RECT  31.632 0 31.656 0.084 ;
    END
  END vr2q[90]
  PIN vr2q[91]
    DIRECTION OUTPUT ;
    USE SIGNAL ;
    PORT
      LAYER M5 ;
        RECT  31.728 0 31.752 0.084 ;
    END
  END vr2q[91]
  PIN vr2q[92]
    DIRECTION OUTPUT ;
    USE SIGNAL ;
    PORT
      LAYER M5 ;
        RECT  31.824 0 31.848 0.084 ;
    END
  END vr2q[92]
  PIN vr2q[93]
    DIRECTION OUTPUT ;
    USE SIGNAL ;
    PORT
      LAYER M5 ;
        RECT  31.92 0 31.944 0.084 ;
    END
  END vr2q[93]
  PIN vr2q[94]
    DIRECTION OUTPUT ;
    USE SIGNAL ;
    PORT
      LAYER M5 ;
        RECT  32.016 0 32.04 0.084 ;
    END
  END vr2q[94]
  PIN vr2q[95]
    DIRECTION OUTPUT ;
    USE SIGNAL ;
    PORT
      LAYER M5 ;
        RECT  32.112 0 32.136 0.084 ;
    END
  END vr2q[95]
  PIN vr2q[96]
    DIRECTION OUTPUT ;
    USE SIGNAL ;
    PORT
      LAYER M5 ;
        RECT  22.992 0 23.016 0.084 ;
    END
  END vr2q[96]
  PIN vr2q[97]
    DIRECTION OUTPUT ;
    USE SIGNAL ;
    PORT
      LAYER M5 ;
        RECT  23.088 0 23.112 0.084 ;
    END
  END vr2q[97]
  PIN vr2q[98]
    DIRECTION OUTPUT ;
    USE SIGNAL ;
    PORT
      LAYER M5 ;
        RECT  23.184 0 23.208 0.084 ;
    END
  END vr2q[98]
  PIN vr2q[99]
    DIRECTION OUTPUT ;
    USE SIGNAL ;
    PORT
      LAYER M5 ;
        RECT  23.28 0 23.304 0.084 ;
    END
  END vr2q[99]
  PIN vr2q[9]
    DIRECTION OUTPUT ;
    USE SIGNAL ;
    PORT
      LAYER M5 ;
        RECT  26.928 0 26.952 0.084 ;
    END
  END vr2q[9]
  PIN VDD
    DIRECTION INOUT ;
    USE POWER ;
    PORT
      LAYER M5 ;
        RECT  61.992 2.151 62.112 41.049 ;
        RECT  56.592 2.151 56.712 41.049 ;
        RECT  51.192 2.151 51.312 41.049 ;
        RECT  45.792 2.151 45.912 41.049 ;
        RECT  40.392 2.151 40.512 41.049 ;
        RECT  34.992 2.151 35.112 41.049 ;
        RECT  29.592 2.151 29.712 41.049 ;
        RECT  24.192 2.151 24.312 41.049 ;
        RECT  18.792 2.151 18.912 41.049 ;
        RECT  13.392 2.151 13.512 41.049 ;
        RECT  7.992 2.151 8.112 41.049 ;
        RECT  2.592 2.151 2.712 41.049 ;
    END
  END VDD
  PIN VSS
    DIRECTION INOUT ;
    USE GROUND ;
    PORT
      LAYER M5 ;
        RECT  61.8 2.137 61.92 41.063 ;
        RECT  56.4 2.137 56.52 41.063 ;
        RECT  51 2.137 51.12 41.063 ;
        RECT  45.6 2.137 45.72 41.063 ;
        RECT  40.2 2.137 40.32 41.063 ;
        RECT  34.8 2.137 34.92 41.063 ;
        RECT  29.4 2.137 29.52 41.063 ;
        RECT  24 2.137 24.12 41.063 ;
        RECT  18.6 2.137 18.72 41.063 ;
        RECT  13.2 2.137 13.32 41.063 ;
        RECT  7.8 2.137 7.92 41.063 ;
        RECT  2.4 2.137 2.52 41.063 ;
    END
  END VSS
  # OT_OBS_CLOSED layer=M5 d_um=1.536 added=153
  OBS
    LAYER RVTN ;
     RECT  2.16 2.16 62.64 2.295 ;
     RECT  2.16 2.565 62.64 2.835 ;
     RECT  2.16 3.105 62.64 3.375 ;
     RECT  2.16 3.645 62.64 3.915 ;
     RECT  2.16 4.185 62.64 4.455 ;
     RECT  2.16 4.725 62.64 4.995 ;
     RECT  2.16 5.265 62.64 5.535 ;
     RECT  2.16 5.805 62.64 6.075 ;
     RECT  2.16 6.345 62.64 6.615 ;
     RECT  2.16 6.885 62.64 7.155 ;
     RECT  2.16 7.425 62.64 7.695 ;
     RECT  2.16 7.965 62.64 8.235 ;
     RECT  2.16 8.505 62.64 8.775 ;
     RECT  2.16 9.045 62.64 9.315 ;
     RECT  2.16 9.585 62.64 9.855 ;
     RECT  2.16 10.125 62.64 10.395 ;
     RECT  2.16 10.665 62.64 10.935 ;
     RECT  2.16 11.205 62.64 11.475 ;
     RECT  2.16 11.745 62.64 12.015 ;
     RECT  2.16 12.285 62.64 12.555 ;
     RECT  2.16 12.825 62.64 13.095 ;
     RECT  2.16 13.365 62.64 13.635 ;
     RECT  2.16 13.905 62.64 14.175 ;
     RECT  2.16 14.445 62.64 14.715 ;
     RECT  2.16 14.985 62.64 15.255 ;
     RECT  2.16 15.525 62.64 15.795 ;
     RECT  2.16 16.065 62.64 16.335 ;
     RECT  2.16 16.605 62.64 16.875 ;
     RECT  2.16 17.145 62.64 17.415 ;
     RECT  2.16 17.685 62.64 17.955 ;
     RECT  2.16 18.225 62.64 18.495 ;
     RECT  2.16 18.765 62.64 19.035 ;
     RECT  2.16 19.305 62.64 19.575 ;
     RECT  2.16 19.845 62.64 20.115 ;
     RECT  2.16 20.385 62.64 20.655 ;
     RECT  2.16 20.925 62.64 21.195 ;
     RECT  2.16 21.465 62.64 21.735 ;
     RECT  2.16 22.005 62.64 22.275 ;
     RECT  2.16 22.545 62.64 22.815 ;
     RECT  2.16 23.085 62.64 23.355 ;
     RECT  2.16 23.625 62.64 23.895 ;
     RECT  2.16 24.165 62.64 24.435 ;
     RECT  2.16 24.705 62.64 24.975 ;
     RECT  2.16 25.245 62.64 25.515 ;
     RECT  2.16 25.785 62.64 26.055 ;
     RECT  2.16 26.325 62.64 26.595 ;
     RECT  2.16 26.865 62.64 27.135 ;
     RECT  2.16 27.405 62.64 27.675 ;
     RECT  2.16 27.945 62.64 28.215 ;
     RECT  2.16 28.485 62.64 28.755 ;
     RECT  2.16 29.025 62.64 29.295 ;
     RECT  2.16 29.565 62.64 29.835 ;
     RECT  2.16 30.105 62.64 30.375 ;
     RECT  2.16 30.645 62.64 30.915 ;
     RECT  2.16 31.185 62.64 31.455 ;
     RECT  2.16 31.725 62.64 31.995 ;
     RECT  2.16 32.265 62.64 32.535 ;
     RECT  2.16 32.805 62.64 33.075 ;
     RECT  2.16 33.345 62.64 33.615 ;
     RECT  2.16 33.885 62.64 34.155 ;
     RECT  2.16 34.425 62.64 34.695 ;
     RECT  2.16 34.965 62.64 35.235 ;
     RECT  2.16 35.505 62.64 35.775 ;
     RECT  2.16 36.045 62.64 36.315 ;
     RECT  2.16 36.585 62.64 36.855 ;
     RECT  2.16 37.125 62.64 37.395 ;
     RECT  2.16 37.665 62.64 37.935 ;
     RECT  2.16 38.205 62.64 38.475 ;
     RECT  2.16 38.745 62.64 39.015 ;
     RECT  2.16 39.285 62.64 39.555 ;
     RECT  2.16 39.825 62.64 40.095 ;
     RECT  2.16 40.365 62.64 40.635 ;
     RECT  2.16 40.905 62.64 41.04 ;
    LAYER RVTP ;
     RECT  2.16 2.295 62.64 2.565 ;
     RECT  2.16 2.835 62.64 3.105 ;
     RECT  2.16 3.375 62.64 3.645 ;
     RECT  2.16 3.915 62.64 4.185 ;
     RECT  2.16 4.455 62.64 4.725 ;
     RECT  2.16 4.995 62.64 5.265 ;
     RECT  2.16 5.535 62.64 5.805 ;
     RECT  2.16 6.075 62.64 6.345 ;
     RECT  2.16 6.615 62.64 6.885 ;
     RECT  2.16 7.155 62.64 7.425 ;
     RECT  2.16 7.695 62.64 7.965 ;
     RECT  2.16 8.235 62.64 8.505 ;
     RECT  2.16 8.775 62.64 9.045 ;
     RECT  2.16 9.315 62.64 9.585 ;
     RECT  2.16 9.855 62.64 10.125 ;
     RECT  2.16 10.395 62.64 10.665 ;
     RECT  2.16 10.935 62.64 11.205 ;
     RECT  2.16 11.475 62.64 11.745 ;
     RECT  2.16 12.015 62.64 12.285 ;
     RECT  2.16 12.555 62.64 12.825 ;
     RECT  2.16 13.095 62.64 13.365 ;
     RECT  2.16 13.635 62.64 13.905 ;
     RECT  2.16 14.175 62.64 14.445 ;
     RECT  2.16 14.715 62.64 14.985 ;
     RECT  2.16 15.255 62.64 15.525 ;
     RECT  2.16 15.795 62.64 16.065 ;
     RECT  2.16 16.335 62.64 16.605 ;
     RECT  2.16 16.875 62.64 17.145 ;
     RECT  2.16 17.415 62.64 17.685 ;
     RECT  2.16 17.955 62.64 18.225 ;
     RECT  2.16 18.495 62.64 18.765 ;
     RECT  2.16 19.035 62.64 19.305 ;
     RECT  2.16 19.575 62.64 19.845 ;
     RECT  2.16 20.115 62.64 20.385 ;
     RECT  2.16 20.655 62.64 20.925 ;
     RECT  2.16 21.195 62.64 21.465 ;
     RECT  2.16 21.735 62.64 22.005 ;
     RECT  2.16 22.275 62.64 22.545 ;
     RECT  2.16 22.815 62.64 23.085 ;
     RECT  2.16 23.355 62.64 23.625 ;
     RECT  2.16 23.895 62.64 24.165 ;
     RECT  2.16 24.435 62.64 24.705 ;
     RECT  2.16 24.975 62.64 25.245 ;
     RECT  2.16 25.515 62.64 25.785 ;
     RECT  2.16 26.055 62.64 26.325 ;
     RECT  2.16 26.595 62.64 26.865 ;
     RECT  2.16 27.135 62.64 27.405 ;
     RECT  2.16 27.675 62.64 27.945 ;
     RECT  2.16 28.215 62.64 28.485 ;
     RECT  2.16 28.755 62.64 29.025 ;
     RECT  2.16 29.295 62.64 29.565 ;
     RECT  2.16 29.835 62.64 30.105 ;
     RECT  2.16 30.375 62.64 30.645 ;
     RECT  2.16 30.915 62.64 31.185 ;
     RECT  2.16 31.455 62.64 31.725 ;
     RECT  2.16 31.995 62.64 32.265 ;
     RECT  2.16 32.535 62.64 32.805 ;
     RECT  2.16 33.075 62.64 33.345 ;
     RECT  2.16 33.615 62.64 33.885 ;
     RECT  2.16 34.155 62.64 34.425 ;
     RECT  2.16 34.695 62.64 34.965 ;
     RECT  2.16 35.235 62.64 35.505 ;
     RECT  2.16 35.775 62.64 36.045 ;
     RECT  2.16 36.315 62.64 36.585 ;
     RECT  2.16 36.855 62.64 37.125 ;
     RECT  2.16 37.395 62.64 37.665 ;
     RECT  2.16 37.935 62.64 38.205 ;
     RECT  2.16 38.475 62.64 38.745 ;
     RECT  2.16 39.015 62.64 39.285 ;
     RECT  2.16 39.555 62.64 39.825 ;
     RECT  2.16 40.095 62.64 40.365 ;
     RECT  2.16 40.635 62.64 40.905 ;
    LAYER M1 ;
     RECT  2.16 2.151 62.64 41.049 ;
    LAYER M2 ;
     RECT  2.16 2.151 6.331 41.049 ;
     RECT  6.331 2.034 7.151 41.049 ;
     RECT  7.151 2.151 10.291 41.049 ;
     RECT  10.291 2.151 10.723 41.094 ;
     RECT  10.723 2.106 11.867 41.094 ;
     RECT  11.867 2.151 17.527 41.094 ;
     RECT  17.527 2.106 18.059 41.094 ;
     RECT  18.059 2.151 21.559 41.094 ;
     RECT  21.559 2.106 22.819 41.094 ;
     RECT  22.819 2.106 22.919 41.166 ;
     RECT  22.919 2.151 24.287 41.166 ;
     RECT  24.287 2.151 25.123 41.094 ;
     RECT  25.123 2.106 26.915 41.094 ;
     RECT  26.915 2.151 30.775 41.094 ;
     RECT  30.919 1.152 31.019 1.17 ;
     RECT  31.999 1.224 32.071 1.242 ;
     RECT  32.071 1.152 32.135 1.242 ;
     RECT  32.135 1.152 33.755 1.17 ;
     RECT  30.775 2.151 34.951 41.166 ;
     RECT  34.951 2.106 35.087 41.166 ;
     RECT  34.555 1.152 35.159 1.17 ;
     RECT  35.087 2.106 35.591 41.094 ;
     RECT  35.591 2.151 36.355 41.094 ;
     RECT  36.355 2.106 37.751 41.094 ;
     RECT  37.751 2.151 40.927 41.094 ;
     RECT  40.927 2.106 41.387 41.094 ;
     RECT  41.387 2.151 42.763 41.094 ;
     RECT  42.763 2.151 45.887 41.166 ;
     RECT  45.887 2.151 48.731 41.094 ;
     RECT  48.731 2.151 62.64 41.049 ;
    LAYER M3 ;
     RECT  6.804 0.091 6.822 0.139 ;
     RECT  7.776 0.091 8.298 0.139 ;
     RECT  10.908 0.091 11.61 0.139 ;
     RECT  27.036 0.091 27.054 0.139 ;
     RECT  41.832 0.091 41.85 0.139 ;
     RECT  45.756 0.091 45.774 0.139 ;
     RECT  25.488 0.091 25.974 0.187 ;
     RECT  23.976 0.091 23.994 0.235 ;
     RECT  6.804 0.139 8.442 0.331 ;
     RECT  28.404 0.091 28.422 0.475 ;
     RECT  10.908 0.139 11.718 0.523 ;
     RECT  19.836 0.091 20.07 0.523 ;
     RECT  22.176 0.091 22.842 0.523 ;
     RECT  23.976 0.235 24.462 0.523 ;
     RECT  25.488 0.187 26.01 0.523 ;
     RECT  26.964 0.139 27.054 0.523 ;
     RECT  33.372 0.091 33.678 0.523 ;
     RECT  6.804 0.331 8.514 0.557 ;
     RECT  6.804 0.557 7.794 0.571 ;
     RECT  9.828 0.523 9.846 0.571 ;
     RECT  14.004 0.091 14.166 0.571 ;
     RECT  16.74 0.091 17.982 0.571 ;
     RECT  19.836 0.523 20.502 0.571 ;
     RECT  22.176 0.523 27.126 0.571 ;
     RECT  28.404 0.475 28.962 0.571 ;
     RECT  30.42 0.091 30.618 0.571 ;
     RECT  32.004 0.091 32.346 0.571 ;
     RECT  33.156 0.523 33.678 0.571 ;
     RECT  38.232 0.091 38.25 0.571 ;
     RECT  39.924 0.091 40.662 0.571 ;
     RECT  41.832 0.139 42.066 0.571 ;
     RECT  48.528 0.091 50.886 0.571 ;
     RECT  51.984 0.091 52.47 0.571 ;
     RECT  53.352 0.091 53.37 0.571 ;
     RECT  54.54 0.091 55.458 0.571 ;
     RECT  56.196 0.091 56.826 0.571 ;
     RECT  9.36 0.571 9.846 1.099 ;
     RECT  15.336 0.091 15.714 1.099 ;
     RECT  16.704 0.571 18.018 1.099 ;
     RECT  19.836 0.571 21.222 1.099 ;
     RECT  22.176 0.571 28.998 1.099 ;
     RECT  30.024 0.571 31.014 1.099 ;
     RECT  32.004 0.571 33.678 1.099 ;
     RECT  34.956 0.091 34.974 1.099 ;
     RECT  10.908 0.523 12.222 1.147 ;
     RECT  13.644 0.571 14.166 1.147 ;
     RECT  18.972 0.571 18.99 1.147 ;
     RECT  30.024 1.099 33.678 1.147 ;
     RECT  34.704 1.099 34.974 1.147 ;
     RECT  36.324 0.091 36.342 1.147 ;
     RECT  39.924 0.571 42.066 1.147 ;
     RECT  44.208 0.571 44.838 1.147 ;
     RECT  45.756 0.139 45.99 1.147 ;
     RECT  47.772 0.091 47.79 1.147 ;
     RECT  48.528 0.571 56.826 1.147 ;
     RECT  13.644 1.147 14.418 1.195 ;
     RECT  15.336 1.099 18.018 1.195 ;
     RECT  9.18 1.099 9.846 1.675 ;
     RECT  10.908 1.147 12.654 1.675 ;
     RECT  39.42 1.147 42.246 1.675 ;
     RECT  43.2 1.147 43.218 1.675 ;
     RECT  47.016 1.147 47.034 1.675 ;
     RECT  47.772 1.147 56.826 1.675 ;
     RECT  6.264 0.571 7.794 1.723 ;
     RECT  9.18 1.675 12.654 1.723 ;
     RECT  13.644 1.195 18.018 1.723 ;
     RECT  18.972 1.147 19.098 1.723 ;
     RECT  19.836 1.099 21.33 1.723 ;
     RECT  22.104 1.099 28.998 1.723 ;
     RECT  30.024 1.147 33.75 1.723 ;
     RECT  34.56 1.147 35.154 1.723 ;
     RECT  35.964 1.147 36.342 1.723 ;
     RECT  37.404 0.571 38.25 1.723 ;
     RECT  39.096 1.675 43.218 1.723 ;
     RECT  44.208 1.147 45.99 1.723 ;
     RECT  47.016 1.675 56.826 1.723 ;
     RECT  39.096 1.723 56.826 1.771 ;
     RECT  58.212 1.723 58.23 1.771 ;
     RECT  39.096 1.771 57.402 1.819 ;
     RECT  58.212 1.771 58.77 1.819 ;
     RECT  6.264 1.723 8.046 2.191 ;
     RECT  9.18 1.723 38.25 2.191 ;
     RECT  39.096 1.819 58.77 2.191 ;
     RECT  6.264 2.191 58.77 2.219 ;
     RECT  6.264 2.219 58.626 2.263 ;
     RECT  6.12 2.263 58.626 2.335 ;
     RECT  2.415 2.143 2.505 2.413 ;
     RECT  61.815 2.143 61.905 2.413 ;
     RECT  5.688 2.335 58.626 2.489 ;
     RECT  5.796 2.489 58.626 2.525 ;
     RECT  6.012 2.525 58.626 2.561 ;
     RECT  6.12 2.561 58.626 3.569 ;
     RECT  6.228 3.569 58.626 4.559 ;
     RECT  6.732 4.559 58.626 4.649 ;
     RECT  6.732 4.649 58.086 4.991 ;
     RECT  7.524 4.991 58.086 5.063 ;
     RECT  7.632 5.063 58.086 5.459 ;
     RECT  7.632 5.459 57.546 6.179 ;
     RECT  7.815 6.179 57.546 12.857 ;
     RECT  7.815 12.857 57.294 21.389 ;
     RECT  7.815 21.389 55.674 23.117 ;
     RECT  52.704 23.117 55.674 23.189 ;
     RECT  7.815 23.117 51.75 24.233 ;
     RECT  52.776 23.189 55.674 24.359 ;
     RECT  54.108 24.359 55.674 24.935 ;
     RECT  9.576 24.233 51.75 25.349 ;
     RECT  54.612 24.935 55.674 25.439 ;
     RECT  9.72 25.349 51.75 25.475 ;
     RECT  56.415 21.389 57.294 25.979 ;
     RECT  9.72 25.475 51.642 26.519 ;
     RECT  54.612 25.439 55.134 27.671 ;
     RECT  55.116 27.671 55.134 28.211 ;
     RECT  52.776 24.359 53.334 28.247 ;
     RECT  6.732 4.991 6.75 28.787 ;
     RECT  9.72 26.519 51.297 29.839 ;
     RECT  9.72 29.839 51.822 30.037 ;
     RECT  9.72 30.037 52.182 30.073 ;
     RECT  53.316 28.247 53.334 30.073 ;
     RECT  56.415 25.979 56.697 30.109 ;
     RECT  56.415 30.109 57.186 30.139 ;
     RECT  56.415 30.139 57.222 30.145 ;
     RECT  56.415 30.145 57.726 30.181 ;
     RECT  9.72 30.073 53.334 30.649 ;
     RECT  9.72 30.649 53.874 30.839 ;
     RECT  9.828 30.839 53.874 31.117 ;
     RECT  55.008 31.081 55.026 31.117 ;
     RECT  9.828 31.117 55.026 31.243 ;
     RECT  9.828 31.243 55.53 31.723 ;
     RECT  9.828 31.723 55.566 32.299 ;
     RECT  56.415 30.181 58.086 32.299 ;
     RECT  9.828 32.299 58.086 32.459 ;
     RECT  9.828 32.459 57.726 32.701 ;
     RECT  9.612 32.701 57.726 33.269 ;
     RECT  7.815 24.233 8.766 33.385 ;
     RECT  9.612 33.269 57.402 33.385 ;
     RECT  7.815 33.385 57.402 34.159 ;
     RECT  7.815 34.159 57.798 34.205 ;
     RECT  7.815 34.205 57.438 34.349 ;
     RECT  7.815 34.349 57.402 35.803 ;
     RECT  7.815 35.803 57.978 35.851 ;
     RECT  58.896 35.545 58.914 35.851 ;
     RECT  7.815 35.851 58.914 36.391 ;
     RECT  7.815 36.391 59.022 36.625 ;
     RECT  7.704 36.625 59.022 37.165 ;
     RECT  7.56 37.165 59.022 37.291 ;
     RECT  7.452 37.291 59.022 37.963 ;
     RECT  7.344 37.963 59.022 38.039 ;
     RECT  7.488 38.039 59.022 38.813 ;
     RECT  7.488 38.813 58.59 39.289 ;
     RECT  7.2 39.289 58.59 39.353 ;
     RECT  7.2 39.353 58.374 40.135 ;
     RECT  6.948 40.135 58.374 40.171 ;
     RECT  6.948 40.171 58.554 40.289 ;
     RECT  6.948 40.289 58.374 40.559 ;
     RECT  2.415 2.413 2.697 40.787 ;
     RECT  61.815 2.413 62.097 40.787 ;
     RECT  6.948 40.559 57.87 40.829 ;
     RECT  25.848 40.829 57.87 40.979 ;
     RECT  6.948 40.829 25.038 41.021 ;
     RECT  25.848 40.979 52.218 41.021 ;
     RECT  53.28 40.979 57.87 41.021 ;
     RECT  2.415 40.787 2.505 41.057 ;
     RECT  61.815 40.787 61.905 41.057 ;
     RECT  11.772 41.021 15.966 41.069 ;
     RECT  22.572 41.021 25.038 41.069 ;
     RECT  25.848 41.021 26.73 41.069 ;
     RECT  27.684 41.021 27.702 41.069 ;
     RECT  36 41.021 36.342 41.069 ;
     RECT  49.86 41.021 51.93 41.069 ;
     RECT  10.296 41.021 10.314 41.099 ;
     RECT  49.86 41.069 51.318 41.117 ;
     RECT  53.532 41.021 57.042 41.117 ;
     RECT  28.584 41.021 29.898 41.165 ;
     RECT  50.868 41.117 51.318 41.165 ;
     RECT  30.78 41.021 31.122 41.171 ;
     RECT  42.3 41.021 43.182 41.171 ;
     RECT  17.532 41.021 19.89 41.213 ;
     RECT  22.716 41.069 25.038 41.213 ;
     RECT  34.632 41.021 35.19 41.213 ;
     RECT  39.816 41.021 41.418 41.213 ;
     RECT  50.976 41.165 51.174 41.213 ;
     RECT  53.532 41.117 56.862 41.213 ;
     RECT  12.24 41.069 15.966 41.261 ;
     RECT  29.376 41.165 29.898 41.261 ;
     RECT  7.344 41.021 9.198 41.309 ;
     RECT  12.24 41.261 12.942 41.309 ;
     RECT  8.388 41.309 9.198 41.597 ;
     RECT  19.008 41.213 19.89 41.597 ;
     RECT  8.388 41.597 8.406 41.645 ;
     RECT  9.18 41.597 9.198 41.645 ;
     RECT  13.716 41.261 15.966 41.645 ;
     RECT  19.008 41.597 19.026 41.645 ;
     RECT  25.848 41.069 26.226 41.645 ;
     RECT  29.88 41.261 29.898 41.645 ;
     RECT  32.508 41.021 32.958 41.645 ;
     RECT  38.736 41.021 38.754 41.645 ;
     RECT  39.816 41.213 39.834 41.645 ;
     RECT  43.164 41.171 43.182 41.645 ;
     RECT  44.244 41.021 46.602 41.645 ;
     RECT  47.412 41.021 47.43 41.645 ;
     RECT  48.312 41.021 48.798 41.645 ;
     RECT  50.976 41.213 50.994 41.645 ;
     RECT  53.532 41.213 55.818 41.645 ;
     RECT  7.344 41.309 7.398 42.173 ;
     RECT  22.716 41.213 23.886 42.173 ;
     RECT  36 41.069 36.018 42.173 ;
     RECT  40.572 41.213 41.418 42.173 ;
     RECT  45.396 41.645 46.602 42.173 ;
     RECT  12.924 41.309 12.942 42.221 ;
     RECT  15.3 41.645 15.966 42.221 ;
     RECT  17.532 41.213 18.126 42.221 ;
     RECT  19.872 41.597 19.89 42.221 ;
     RECT  21.564 41.021 21.582 42.221 ;
     RECT  22.716 42.173 23.31 42.221 ;
     RECT  25.02 41.213 25.038 42.221 ;
     RECT  25.848 41.645 26.154 42.221 ;
     RECT  31.104 41.171 31.122 42.221 ;
     RECT  35.172 41.213 35.19 42.221 ;
     RECT  44.244 41.645 44.442 42.221 ;
     RECT  49.86 41.117 50.094 42.221 ;
     RECT  55.26 41.645 55.818 42.221 ;
     RECT  13.716 41.645 14.418 42.269 ;
     RECT  55.8 42.221 55.818 42.317 ;
     RECT  49.32 42.715 49.482 42.811 ;
     RECT  45.576 42.173 46.134 42.845 ;
     RECT  41.4 42.173 41.418 42.955 ;
     RECT  48.312 41.645 48.33 42.955 ;
     RECT  49.104 42.811 49.482 42.989 ;
     RECT  7.344 42.173 7.362 43.085 ;
     RECT  10.872 42.955 10.89 43.085 ;
     RECT  13.716 42.269 13.734 43.085 ;
     RECT  15.948 42.221 15.966 43.085 ;
     RECT  25.848 42.221 25.866 43.085 ;
     RECT  28.584 41.165 28.602 43.085 ;
     RECT  34.2 42.955 34.218 43.085 ;
     RECT  35.928 42.955 35.946 43.085 ;
     RECT  41.004 42.955 41.418 43.085 ;
     RECT  42.3 41.171 42.318 43.085 ;
     RECT  44.424 42.221 44.442 43.085 ;
     RECT  45.576 42.845 45.594 43.085 ;
     RECT  48.132 42.955 48.33 43.085 ;
     RECT  49.176 42.989 49.482 43.085 ;
     RECT  52.308 42.955 52.326 43.085 ;
     RECT  53.64 41.645 54.306 43.085 ;
     RECT  56.844 41.213 56.862 43.085 ;
    LAYER M4 ;
     RECT  2.408 2.148 2.512 41.052 ;
     RECT  2.512 2.418 2.704 40.782 ;
     RECT  6.253 0.576 6.793 0.6 ;
     RECT  5.785 2.496 6.793 2.52 ;
     RECT  6.757 3.552 6.793 3.576 ;
     RECT  6.793 2.496 6.865 3.576 ;
     RECT  6.793 0.096 6.898 0.6 ;
     RECT  6.937 40.992 7.189 41.016 ;
     RECT  6.898 0.096 7.333 0.648 ;
     RECT  6.865 1.728 7.333 4.488 ;
     RECT  7.333 43.056 7.369 43.08 ;
     RECT  7.369 42.144 7.475 43.08 ;
     RECT  7.475 43.056 7.571 43.08 ;
     RECT  7.189 40.464 7.693 41.016 ;
     RECT  7.693 40.464 7.729 41.16 ;
     RECT  7.333 0.096 7.808 4.488 ;
     RECT  7.333 37.968 7.808 37.992 ;
     RECT  7.729 40.464 7.808 41.64 ;
     RECT  7.808 0.096 7.955 41.64 ;
     RECT  7.955 1.728 8.057 41.64 ;
     RECT  8.057 2.208 8.104 41.64 ;
     RECT  7.955 0.096 8.353 0.552 ;
     RECT  8.353 0.144 8.476 0.552 ;
     RECT  8.104 2.208 8.483 4.488 ;
     RECT  8.476 0.336 8.531 0.552 ;
     RECT  8.104 5.856 9.097 6.024 ;
     RECT  8.104 33.6 9.133 34.248 ;
     RECT  8.104 35.712 9.133 37.992 ;
     RECT  9.133 33.6 9.205 37.992 ;
     RECT  8.104 40.464 9.209 41.64 ;
     RECT  9.205 33.6 9.289 38.76 ;
     RECT  9.209 40.464 9.299 41.592 ;
     RECT  9.169 0.576 9.394 1.128 ;
     RECT  9.394 0.576 9.497 1.176 ;
     RECT  8.483 2.256 9.541 4.488 ;
     RECT  9.097 5.472 9.541 6.84 ;
     RECT  9.541 2.256 9.596 6.84 ;
     RECT  9.788 0.528 9.875 0.552 ;
     RECT  9.289 33.6 9.889 38.712 ;
     RECT  9.596 1.68 9.965 6.84 ;
     RECT  9.299 40.464 10.069 41.016 ;
     RECT  9.889 33.36 10.105 38.712 ;
     RECT  9.965 1.68 10.451 4.488 ;
     RECT  10.105 32.496 10.508 38.712 ;
     RECT  10.549 43.008 10.834 43.032 ;
     RECT  10.853 0.096 10.936 0.12 ;
     RECT  10.834 42.96 10.945 43.08 ;
     RECT  10.508 32.496 10.969 38.76 ;
     RECT  10.945 42.96 10.979 42.984 ;
     RECT  10.969 31.728 11.005 38.76 ;
     RECT  10.069 39.84 11.005 41.016 ;
     RECT  10.936 0.096 11.621 0.168 ;
     RECT  11.005 31.728 11.717 41.016 ;
     RECT  11.621 0.144 11.729 0.168 ;
     RECT  11.717 31.728 12.188 41.064 ;
     RECT  10.069 30.672 12.265 30.696 ;
     RECT  12.188 31.728 12.265 41.304 ;
     RECT  11.825 0.528 12.581 0.6 ;
     RECT  10.451 1.728 12.581 4.488 ;
     RECT  12.581 0.528 12.665 4.488 ;
     RECT  11.149 29.616 12.769 29.64 ;
     RECT  12.265 30.672 12.769 41.304 ;
     RECT  12.769 29.616 12.913 41.304 ;
     RECT  12.661 43.008 12.913 43.032 ;
     RECT  12.665 1.728 12.949 4.488 ;
     RECT  9.965 5.472 12.949 6.84 ;
     RECT  12.913 29.616 13.139 43.032 ;
     RECT  12.949 1.728 13.208 6.84 ;
     RECT  8.104 18.48 13.208 18.504 ;
     RECT  8.104 21.408 13.208 21.432 ;
     RECT  8.104 23.616 13.208 23.64 ;
     RECT  13.139 29.616 13.208 41.256 ;
     RECT  13.208 1.728 13.249 41.256 ;
     RECT  12.665 0.528 13.285 0.6 ;
     RECT  13.285 0.336 13.381 0.6 ;
     RECT  13.381 0.24 13.429 0.6 ;
     RECT  13.249 1.728 13.504 41.208 ;
     RECT  13.139 42.96 13.661 43.032 ;
     RECT  13.429 0.144 13.673 0.6 ;
     RECT  13.661 42.96 13.745 43.08 ;
     RECT  13.949 0.096 14.221 0.12 ;
     RECT  13.504 29.616 14.237 41.208 ;
     RECT  13.504 1.728 14.245 6.84 ;
     RECT  14.237 29.616 14.317 41.592 ;
     RECT  14.245 1.152 14.429 6.84 ;
     RECT  14.317 29.616 14.429 42.264 ;
     RECT  15.281 0.096 15.397 0.12 ;
     RECT  14.429 1.2 15.397 6.84 ;
     RECT  14.429 29.616 15.553 42.216 ;
     RECT  15.553 42.192 15.827 42.216 ;
     RECT  15.937 43.056 16.021 43.08 ;
     RECT  15.397 0.096 16.307 6.84 ;
     RECT  17.521 42.192 17.845 42.216 ;
     RECT  16.307 0.096 18.037 0.6 ;
     RECT  17.845 42.192 18.323 43.032 ;
     RECT  15.553 29.616 18.385 41.112 ;
     RECT  16.307 1.728 18.608 6.84 ;
     RECT  13.504 18.48 18.608 18.504 ;
     RECT  13.504 21.408 18.608 21.432 ;
     RECT  13.504 23.616 18.608 23.64 ;
     RECT  18.385 29.616 18.608 41.208 ;
     RECT  18.323 43.008 18.611 43.032 ;
     RECT  18.608 1.728 18.904 41.208 ;
     RECT  18.904 29.616 18.949 41.208 ;
     RECT  18.037 0.576 19.001 0.6 ;
     RECT  18.904 1.728 19.025 6.84 ;
     RECT  19.025 1.152 19.109 6.84 ;
     RECT  18.949 29.616 19.685 41.64 ;
     RECT  19.861 42.192 20.051 42.216 ;
     RECT  19.825 0.096 20.092 0.12 ;
     RECT  20.156 0.528 20.627 0.552 ;
     RECT  19.109 1.68 20.677 6.84 ;
     RECT  18.904 18.48 20.869 18.504 ;
     RECT  20.677 0.576 21.233 6.84 ;
     RECT  22.021 0.096 22.853 0.12 ;
     RECT  21.233 1.104 23.219 6.84 ;
     RECT  21.553 42.192 23.461 42.216 ;
     RECT  19.685 29.616 23.569 41.112 ;
     RECT  23.516 0.528 23.921 0.552 ;
     RECT  23.461 42.096 23.987 42.216 ;
     RECT  23.921 0.096 24.005 0.552 ;
     RECT  23.219 1.728 24.008 6.84 ;
     RECT  20.869 18.48 24.008 19.08 ;
     RECT  18.904 21.408 24.008 21.432 ;
     RECT  18.904 23.616 24.008 23.64 ;
     RECT  23.569 29.088 24.008 41.112 ;
     RECT  24.008 1.728 24.133 41.112 ;
     RECT  24.133 1.728 24.304 41.208 ;
     RECT  24.304 29.616 24.371 41.208 ;
     RECT  24.005 0.24 24.517 0.552 ;
     RECT  24.517 0.24 24.541 0.6 ;
     RECT  24.304 1.728 24.541 6.84 ;
     RECT  24.541 0.24 24.659 6.84 ;
     RECT  24.371 29.616 24.659 41.16 ;
     RECT  24.659 0.24 24.725 0.6 ;
     RECT  24.037 43.008 25.009 43.032 ;
     RECT  24.725 0.24 25.165 0.552 ;
     RECT  24.659 29.616 25.477 41.112 ;
     RECT  25.477 29.088 25.589 41.112 ;
     RECT  25.009 42.192 25.837 43.032 ;
     RECT  25.381 0.096 25.985 0.216 ;
     RECT  25.589 29.616 26.197 41.112 ;
     RECT  25.837 42.192 26.197 43.08 ;
     RECT  26.197 29.616 26.291 43.08 ;
     RECT  25.985 0.144 26.3 0.216 ;
     RECT  26.291 29.616 26.387 42.216 ;
     RECT  26.387 29.616 26.867 41.64 ;
     RECT  26.3 0.144 26.981 0.552 ;
     RECT  26.981 0.096 27.065 0.552 ;
     RECT  27.065 0.528 27.493 0.552 ;
     RECT  27.493 0.528 27.589 0.6 ;
     RECT  27.589 0.528 28.141 0.648 ;
     RECT  24.659 1.728 28.141 6.84 ;
     RECT  28.141 0.528 28.349 6.84 ;
     RECT  28.349 0.096 28.433 6.84 ;
     RECT  28.529 43.056 28.613 43.08 ;
     RECT  28.433 0.48 28.787 6.84 ;
     RECT  28.787 0.48 29.171 0.6 ;
     RECT  26.867 29.616 29.257 41.112 ;
     RECT  29.257 29.616 29.365 41.16 ;
     RECT  28.787 1.728 29.408 6.84 ;
     RECT  24.304 18.48 29.408 19.08 ;
     RECT  24.304 21.408 29.408 21.432 ;
     RECT  24.304 23.616 29.408 23.64 ;
     RECT  29.029 25.824 29.408 25.848 ;
     RECT  29.365 29.616 29.408 41.256 ;
     RECT  29.408 1.728 29.704 41.256 ;
     RECT  29.704 29.088 29.797 41.256 ;
     RECT  29.704 18.48 29.843 19.08 ;
     RECT  29.797 29.088 29.909 41.64 ;
     RECT  29.909 29.088 29.939 41.112 ;
     RECT  29.171 0.576 30.365 0.6 ;
     RECT  30.365 0.096 30.629 0.6 ;
     RECT  30.421 43.008 30.707 43.032 ;
     RECT  30.757 42.96 30.805 42.984 ;
     RECT  30.805 42.864 30.853 42.984 ;
     RECT  30.629 0.192 30.947 0.6 ;
     RECT  30.853 42.192 30.947 42.984 ;
     RECT  30.947 0.576 31.025 0.6 ;
     RECT  30.947 42.192 31.133 42.216 ;
     RECT  29.704 1.728 31.525 6.84 ;
     RECT  32.149 43.008 32.435 43.032 ;
     RECT  29.939 29.616 32.497 41.112 ;
     RECT  31.993 0.096 32.581 0.12 ;
     RECT  31.525 1.104 32.581 6.84 ;
     RECT  32.581 0.096 32.915 6.84 ;
     RECT  32.497 29.616 33.107 41.64 ;
     RECT  32.915 0.096 33.185 0.552 ;
     RECT  32.915 1.728 33.445 6.84 ;
     RECT  33.185 0.096 33.689 0.12 ;
     RECT  33.877 43.008 34.162 43.032 ;
     RECT  34.162 42.96 34.273 43.08 ;
     RECT  34.273 42.96 34.307 42.984 ;
     RECT  33.107 29.616 34.621 41.112 ;
     RECT  33.445 1.728 34.652 6.888 ;
     RECT  34.652 1.104 34.739 6.888 ;
     RECT  34.739 1.728 34.808 6.888 ;
     RECT  29.843 18.48 34.808 18.552 ;
     RECT  29.704 21.408 34.808 21.432 ;
     RECT  29.704 23.616 34.808 23.64 ;
     RECT  29.704 25.968 34.808 25.992 ;
     RECT  34.621 29.616 34.808 41.208 ;
     RECT  34.789 0.336 34.885 0.456 ;
     RECT  34.885 0.096 34.985 0.456 ;
     RECT  34.808 1.728 35.057 41.208 ;
     RECT  35.057 1.728 35.104 41.16 ;
     RECT  35.104 29.616 35.267 41.16 ;
     RECT  34.985 0.192 35.363 0.456 ;
     RECT  34.981 42.192 35.605 42.936 ;
     RECT  35.605 42.192 35.89 43.032 ;
     RECT  35.104 1.728 35.909 6.696 ;
     RECT  35.89 42.192 35.989 43.08 ;
     RECT  35.909 1.152 35.993 6.696 ;
     RECT  35.989 42.144 36.001 43.08 ;
     RECT  36.001 42.144 36.035 42.984 ;
     RECT  36.035 42.144 36.083 42.168 ;
     RECT  36.037 0.096 36.353 0.12 ;
     RECT  35.993 1.728 36.673 6.696 ;
     RECT  35.267 29.616 37.321 41.112 ;
     RECT  37.321 29.088 37.433 41.112 ;
     RECT  37.349 0.576 38.045 0.6 ;
     RECT  38.221 0.096 38.305 0.12 ;
     RECT  37.433 29.616 38.725 41.112 ;
     RECT  36.673 1.728 38.761 7.08 ;
     RECT  35.104 25.968 38.761 25.992 ;
     RECT  38.761 25.968 38.801 26.088 ;
     RECT  38.761 1.728 39.068 7.176 ;
     RECT  38.725 29.616 39.121 41.64 ;
     RECT  39.068 1.68 39.365 7.176 ;
     RECT  39.121 29.088 39.589 41.64 ;
     RECT  39.869 0.096 39.941 0.12 ;
     RECT  39.941 0.096 40.124 0.168 ;
     RECT  39.365 1.152 40.124 7.176 ;
     RECT  40.124 0.096 40.208 7.176 ;
     RECT  38.581 8.784 40.208 8.808 ;
     RECT  35.104 18.48 40.208 18.552 ;
     RECT  35.104 21.408 40.208 21.432 ;
     RECT  35.104 23.616 40.208 23.64 ;
     RECT  38.801 26.064 40.208 26.088 ;
     RECT  39.589 28.176 40.208 41.64 ;
     RECT  40.208 0.096 40.307 41.64 ;
     RECT  39.925 42.96 40.453 42.984 ;
     RECT  40.307 0.096 40.504 41.16 ;
     RECT  40.504 0.096 40.673 7.176 ;
     RECT  40.504 29.616 40.709 41.16 ;
     RECT  40.453 42.144 40.789 42.984 ;
     RECT  40.504 10.8 40.925 10.824 ;
     RECT  40.789 42.144 40.978 43.032 ;
     RECT  40.978 42.144 41.075 43.08 ;
     RECT  40.504 26.064 41.141 26.088 ;
     RECT  41.075 42.96 41.219 43.08 ;
     RECT  40.673 0.576 41.363 7.176 ;
     RECT  41.777 0.096 41.861 0.168 ;
     RECT  41.861 0.144 42.077 0.168 ;
     RECT  41.219 43.056 42.329 43.08 ;
     RECT  41.363 1.152 42.467 7.176 ;
     RECT  42.467 1.152 42.977 6.84 ;
     RECT  40.709 29.616 43.153 41.112 ;
     RECT  42.977 1.152 43.229 6.648 ;
     RECT  43.117 10.8 43.301 10.824 ;
     RECT  43.153 29.616 43.379 41.64 ;
     RECT  40.504 8.784 44.291 8.808 ;
     RECT  44.197 0.576 44.293 0.6 ;
     RECT  43.229 1.728 44.293 6.648 ;
     RECT  40.504 28.176 44.309 28.2 ;
     RECT  44.233 42.192 44.413 42.216 ;
     RECT  44.293 0.576 44.849 6.648 ;
     RECT  43.379 29.616 45.097 41.112 ;
     RECT  44.413 42.192 45.097 43.08 ;
     RECT  44.849 1.152 45.169 6.648 ;
     RECT  45.169 1.152 45.533 6.696 ;
     RECT  45.533 1.728 45.601 6.696 ;
     RECT  45.601 1.728 45.608 6.84 ;
     RECT  44.629 11.376 45.608 11.4 ;
     RECT  40.504 18.48 45.608 18.552 ;
     RECT  40.504 21.408 45.608 21.432 ;
     RECT  40.504 23.616 45.608 23.64 ;
     RECT  45.097 29.616 45.608 43.08 ;
     RECT  45.397 0.144 45.637 0.168 ;
     RECT  45.608 1.728 45.779 43.08 ;
     RECT  45.637 0.096 45.785 0.168 ;
     RECT  45.779 42.144 45.875 43.08 ;
     RECT  45.779 1.728 45.904 41.112 ;
     RECT  45.904 1.728 45.929 6.84 ;
     RECT  45.785 0.144 46.001 0.168 ;
     RECT  45.904 10.656 46.001 10.824 ;
     RECT  46.001 10.656 46.019 10.776 ;
     RECT  46.019 10.752 46.145 10.776 ;
     RECT  45.929 1.728 46.253 6.696 ;
     RECT  45.875 42.144 46.259 42.84 ;
     RECT  46.253 1.728 46.403 6.6 ;
     RECT  46.403 5.76 46.433 6.6 ;
     RECT  45.904 21.408 46.691 21.432 ;
     RECT  46.259 42.144 46.835 42.168 ;
     RECT  46.403 1.728 46.885 4.584 ;
     RECT  46.885 1.152 46.937 4.584 ;
     RECT  46.937 1.152 47.045 3.384 ;
     RECT  45.904 18.48 47.123 18.552 ;
     RECT  45.904 23.616 47.219 23.64 ;
     RECT  45.904 29.616 47.401 41.112 ;
     RECT  47.401 29.616 47.507 41.64 ;
     RECT  46.937 4.512 47.657 4.584 ;
     RECT  47.657 4.512 47.987 4.536 ;
     RECT  48.037 43.056 48.085 43.08 ;
     RECT  47.045 1.68 48.133 3.384 ;
     RECT  48.133 1.152 48.341 3.384 ;
     RECT  47.507 29.616 48.769 41.112 ;
     RECT  47.365 0.096 48.78 0.12 ;
     RECT  48.085 42.96 48.997 43.08 ;
     RECT  48.997 42.864 49.093 43.08 ;
     RECT  48.769 29.616 49.241 41.64 ;
     RECT  48.341 1.728 49.273 3.384 ;
     RECT  49.093 42.816 49.309 43.08 ;
     RECT  49.093 10.8 49.313 10.824 ;
     RECT  48.78 0.096 49.381 0.168 ;
     RECT  49.309 42.72 49.537 43.08 ;
     RECT  46.433 5.76 49.561 6.072 ;
     RECT  49.241 30.144 49.571 41.64 ;
     RECT  49.537 42.72 49.669 43.032 ;
     RECT  49.561 5.76 49.781 6.696 ;
     RECT  49.273 1.728 49.861 3.432 ;
     RECT  49.669 42.144 49.889 43.032 ;
     RECT  49.861 1.728 49.961 3.96 ;
     RECT  49.889 42.192 50.291 43.032 ;
     RECT  49.571 37.632 50.857 41.112 ;
     RECT  49.381 0.096 50.897 0.6 ;
     RECT  49.781 5.76 50.929 6.072 ;
     RECT  50.857 37.632 50.965 41.16 ;
     RECT  49.961 1.728 51.008 3.384 ;
     RECT  50.929 5.472 51.008 6.072 ;
     RECT  47.123 18.528 51.008 18.552 ;
     RECT  49.571 30.144 51.008 36.648 ;
     RECT  50.965 37.632 51.008 41.64 ;
     RECT  50.291 43.008 51.059 43.032 ;
     RECT  51.008 1.728 51.251 41.64 ;
     RECT  51.251 1.728 51.304 41.16 ;
     RECT  51.304 1.728 51.329 2.04 ;
     RECT  51.304 38.16 51.347 41.16 ;
     RECT  50.897 0.576 51.389 0.6 ;
     RECT  51.329 1.728 51.389 1.8 ;
     RECT  51.389 0.576 51.653 1.8 ;
     RECT  51.653 0.576 51.761 0.648 ;
     RECT  51.304 36 51.905 36.648 ;
     RECT  51.347 38.16 51.941 41.064 ;
     RECT  51.761 0.576 51.973 0.6 ;
     RECT  51.304 30.144 52.157 31.752 ;
     RECT  51.941 38.16 52.252 41.016 ;
     RECT  52.069 43.008 52.258 43.032 ;
     RECT  52.258 42.96 52.403 43.08 ;
     RECT  52.403 42.96 52.451 42.984 ;
     RECT  51.304 5.712 52.453 6.072 ;
     RECT  51.304 32.832 52.741 35.016 ;
     RECT  52.453 5.136 52.769 6.072 ;
     RECT  52.741 32.832 52.828 35.352 ;
     RECT  52.769 5.376 52.837 6.072 ;
     RECT  51.653 1.728 53.221 1.8 ;
     RECT  51.304 3.072 53.221 3.384 ;
     RECT  52.837 5.376 53.237 6.312 ;
     RECT  52.252 38.16 53.269 40.968 ;
     RECT  51.905 36.528 53.485 36.648 ;
     RECT  53.237 5.376 53.489 6.072 ;
     RECT  53.269 38.16 53.521 41.016 ;
     RECT  53.221 1.728 53.605 3.384 ;
     RECT  53.605 1.728 53.701 4.008 ;
     RECT  53.489 5.76 53.777 6.072 ;
     RECT  52.828 32.832 53.953 33.096 ;
     RECT  52.828 34.08 53.953 35.352 ;
     RECT  53.701 1.728 54.029 4.104 ;
     RECT  54.029 4.08 54.065 4.104 ;
     RECT  53.777 5.76 54.173 5.784 ;
     RECT  53.521 38.16 54.181 41.64 ;
     RECT  51.304 18.528 54.227 18.552 ;
     RECT  53.953 32.832 54.227 35.352 ;
     RECT  53.585 43.056 54.317 43.08 ;
     RECT  51.973 0.096 54.373 0.6 ;
     RECT  54.029 1.728 54.373 3.096 ;
     RECT  54.181 37.632 54.497 41.64 ;
     RECT  54.373 0.096 54.515 3.096 ;
     RECT  53.485 36.432 54.605 36.648 ;
     RECT  54.605 36.432 54.637 36.456 ;
     RECT  54.497 38.16 54.677 41.64 ;
     RECT  54.677 40.896 54.899 41.64 ;
     RECT  54.637 36.096 55.181 36.456 ;
     RECT  54.515 0.096 55.621 1.848 ;
     RECT  54.515 2.928 55.621 3.096 ;
     RECT  55.621 0.096 55.763 3.096 ;
     RECT  55.249 42.096 55.763 42.216 ;
     RECT  55.763 42.192 55.789 42.216 ;
     RECT  52.157 31.248 55.933 31.752 ;
     RECT  54.227 32.832 55.933 34.44 ;
     RECT  55.181 36.096 55.933 36.12 ;
     RECT  55.789 42.192 55.955 42.312 ;
     RECT  54.677 38.16 56.005 39.912 ;
     RECT  54.899 40.896 56.005 41.016 ;
     RECT  55.955 42.288 56.147 42.312 ;
     RECT  56.005 38.16 56.185 41.016 ;
     RECT  55.763 0.096 56.261 0.6 ;
     RECT  56.185 37.584 56.329 41.016 ;
     RECT  55.763 1.728 56.408 3.096 ;
     RECT  52.157 30.144 56.408 30.168 ;
     RECT  55.933 31.248 56.408 34.44 ;
     RECT  55.933 35.808 56.408 36.12 ;
     RECT  56.329 37.584 56.408 41.208 ;
     RECT  56.408 1.728 56.621 41.208 ;
     RECT  56.621 1.728 56.704 41.112 ;
     RECT  56.261 0.096 56.801 0.216 ;
     RECT  56.581 42.864 56.819 43.08 ;
     RECT  56.801 0.096 56.837 0.12 ;
     RECT  56.819 42.96 56.873 43.08 ;
     RECT  56.704 2.88 56.909 3.096 ;
     RECT  56.873 42.96 56.963 42.984 ;
     RECT  56.704 32.304 57.089 32.328 ;
     RECT  56.704 40.896 57.203 41.112 ;
     RECT  56.704 30.144 57.233 30.168 ;
     RECT  56.704 34.176 57.269 34.44 ;
     RECT  56.704 37.584 57.305 39.768 ;
     RECT  56.704 1.728 57.449 1.896 ;
     RECT  57.449 1.728 57.521 1.848 ;
     RECT  57.305 38.208 57.733 39.768 ;
     RECT  57.203 40.896 57.733 41.016 ;
     RECT  57.269 34.176 57.809 34.2 ;
     RECT  57.733 38.208 57.82 41.016 ;
     RECT  57.82 40.992 57.881 41.016 ;
     RECT  56.704 35.808 57.989 35.832 ;
     RECT  56.909 3.072 58.097 3.096 ;
     RECT  57.521 1.728 58.241 1.8 ;
     RECT  57.82 38.208 58.241 39.768 ;
     RECT  58.241 38.208 58.313 39.528 ;
     RECT  58.313 38.208 58.493 38.808 ;
     RECT  58.241 1.776 58.781 1.8 ;
     RECT  58.493 38.784 59.033 38.808 ;
     RECT  61.808 2.148 61.912 41.052 ;
     RECT  61.912 2.418 62.104 40.782 ;
    LAYER M5 ;
     RECT  6.864 0.016 57.576 0.131 ;
     RECT  6.864 0.131 19.08 0.611 ;
     RECT  6.96 0.611 19.08 0.659 ;
     RECT  7.056 0.659 19.08 1.187 ;
     RECT  20.112 0.131 57.576 1.715 ;
     RECT  7.056 1.187 18.888 1.763 ;
     RECT  39.216 1.715 57.576 1.763 ;
     RECT  7.728 1.763 18.888 1.811 ;
     RECT  39.312 1.763 57.576 1.811 ;
     RECT  20.304 1.715 38.184 1.859 ;
     RECT  39.504 1.811 57.48 1.859 ;
     RECT  39.504 1.859 57.288 1.907 ;
     RECT  7.728 1.811 15.912 2.051 ;
     RECT  2.4 2.137 2.52 2.151 ;
     RECT  17.328 1.811 18.888 2.151 ;
     RECT  61.8 2.137 61.92 2.151 ;
     RECT  17.328 2.151 18.912 2.195 ;
     RECT  20.304 1.859 35.496 2.195 ;
     RECT  39.504 1.907 56.712 2.195 ;
     RECT  7.8 2.051 15.912 2.243 ;
     RECT  7.8 2.243 11.4 2.291 ;
     RECT  12.912 2.243 15.912 2.291 ;
     RECT  17.616 2.195 18.912 2.291 ;
     RECT  21.552 2.195 35.496 2.291 ;
     RECT  39.504 2.195 55.272 2.291 ;
     RECT  7.8 2.291 10.632 2.339 ;
     RECT  20.304 2.195 20.52 2.339 ;
     RECT  21.552 2.291 31.752 2.339 ;
     RECT  20.4 2.339 20.52 2.387 ;
     RECT  7.8 2.339 10.536 2.915 ;
     RECT  12.912 2.291 15.048 2.915 ;
     RECT  21.84 2.339 31.752 2.915 ;
     RECT  36.528 1.859 38.184 2.915 ;
     RECT  39.504 2.291 47.976 2.915 ;
     RECT  7.8 2.915 9.768 2.963 ;
     RECT  13.008 2.915 15.048 2.963 ;
     RECT  27.696 2.915 31.752 2.963 ;
     RECT  36.624 2.915 37.512 2.963 ;
     RECT  39.6 2.915 47.976 2.963 ;
     RECT  55.248 2.291 55.272 2.963 ;
     RECT  36.912 2.963 37.512 3.107 ;
     RECT  36.912 3.107 37.416 3.203 ;
     RECT  21.936 2.915 26.712 3.251 ;
     RECT  7.8 2.963 9.576 3.443 ;
     RECT  20.4 2.387 20.424 3.443 ;
     RECT  27.696 2.963 28.2 3.443 ;
     RECT  39.6 2.963 43.608 3.443 ;
     RECT  49.296 2.291 49.32 3.443 ;
     RECT  21.936 3.251 26.664 3.827 ;
     RECT  13.008 2.963 14.568 4.019 ;
     RECT  51 2.291 54.216 4.115 ;
     RECT  18.48 2.291 18.912 4.165 ;
     RECT  38.592 4.117 38.616 4.165 ;
     RECT  39.6 3.443 41.112 4.165 ;
     RECT  29.184 2.963 30.264 4.213 ;
     RECT  13.008 4.019 14.088 4.307 ;
     RECT  23.28 3.827 26.664 4.405 ;
     RECT  27.696 3.443 27.72 4.405 ;
     RECT  29.088 4.213 30.264 4.453 ;
     RECT  31.248 2.963 31.752 4.453 ;
     RECT  42.624 3.443 43.608 4.453 ;
     RECT  44.592 2.963 47.976 4.547 ;
     RECT  21.936 3.827 22.248 4.595 ;
     RECT  29.088 4.453 31.752 4.595 ;
     RECT  44.592 4.547 47.112 4.595 ;
     RECT  29.088 4.595 30.312 4.693 ;
     RECT  44.592 4.595 46.392 5.075 ;
     RECT  9.552 3.443 9.576 5.171 ;
     RECT  32.784 2.291 35.496 5.171 ;
     RECT  42.336 4.453 43.608 5.221 ;
     RECT  18.288 4.165 18.912 5.651 ;
     RECT  32.832 5.171 35.496 5.747 ;
     RECT  51 4.115 52.872 5.747 ;
     RECT  13.104 4.307 14.088 5.795 ;
     RECT  23.28 4.405 27.72 5.843 ;
     RECT  32.832 5.747 35.352 5.987 ;
     RECT  13.2 5.795 14.088 5.989 ;
     RECT  37.344 3.203 37.416 5.989 ;
     RECT  38.592 4.165 41.112 5.989 ;
     RECT  34.656 5.987 35.352 6.083 ;
     RECT  13.2 5.989 14.856 6.131 ;
     RECT  37.344 5.989 41.112 6.179 ;
     RECT  34.8 6.083 35.352 6.227 ;
     RECT  13.2 6.131 14.088 6.323 ;
     RECT  24 5.843 27.72 6.323 ;
     RECT  34.8 6.227 35.208 6.323 ;
     RECT  52.848 5.747 52.872 6.323 ;
     RECT  32.832 5.987 33.48 6.899 ;
     RECT  42.288 5.221 43.608 8.773 ;
     RECT  44.592 5.075 46.104 8.773 ;
     RECT  54.192 4.115 54.216 18.563 ;
     RECT  42.288 8.773 46.104 21.397 ;
     RECT  47.088 18.469 47.112 21.397 ;
     RECT  42.288 21.397 47.112 23.605 ;
     RECT  29.04 4.693 30.312 25.859 ;
     RECT  38.592 6.179 41.112 28.211 ;
     RECT  39.84 28.211 41.112 30.803 ;
     RECT  37.344 6.179 37.416 32.147 ;
     RECT  18.48 5.651 18.912 32.197 ;
     RECT  18.48 32.197 19.176 32.437 ;
     RECT  51 5.747 51.312 32.437 ;
     RECT  32.832 6.899 32.856 32.675 ;
     RECT  39.888 30.803 41.112 32.675 ;
     RECT  25.488 6.323 26.76 32.677 ;
     RECT  31.728 4.595 31.752 32.917 ;
     RECT  25.488 32.677 27.096 33.013 ;
     RECT  42.288 23.605 47.208 33.013 ;
     RECT  24 6.323 24.408 33.061 ;
     RECT  29.28 25.859 30.312 33.061 ;
     RECT  34.8 6.323 35.112 33.061 ;
     RECT  42.192 33.013 47.208 33.107 ;
     RECT  21.936 4.595 21.96 33.109 ;
     RECT  24 33.061 24.504 33.109 ;
     RECT  25.488 33.013 27.336 33.109 ;
     RECT  21.936 33.109 22.056 33.157 ;
     RECT  34.224 33.061 35.112 33.203 ;
     RECT  37.344 32.147 37.368 33.301 ;
     RECT  31.728 32.917 32.136 33.491 ;
     RECT  34.8 33.203 35.112 33.541 ;
     RECT  37.344 33.301 37.464 33.541 ;
     RECT  50.88 32.437 51.312 33.587 ;
     RECT  13.2 6.323 13.608 33.637 ;
     RECT  24 33.109 27.336 33.685 ;
     RECT  18.288 32.437 19.176 33.779 ;
     RECT  15.36 31.861 15.384 33.781 ;
     RECT  16.512 33.301 16.536 33.781 ;
     RECT  15.36 33.781 16.536 33.827 ;
     RECT  21.792 33.157 22.056 33.829 ;
     RECT  38.592 28.211 38.76 33.973 ;
     RECT  40.2 32.675 41.112 33.973 ;
     RECT  29.136 33.061 30.312 34.021 ;
     RECT  31.728 33.491 31.752 34.021 ;
     RECT  29.136 34.021 31.752 34.163 ;
     RECT  13.104 33.637 13.608 34.211 ;
     RECT  34.8 33.541 35.4 34.259 ;
     RECT  18.432 33.779 19.176 34.307 ;
     RECT  37.344 33.541 37.512 34.307 ;
     RECT  42.192 33.107 47.112 34.403 ;
     RECT  37.344 34.307 37.464 34.549 ;
     RECT  15.984 33.827 16.536 34.595 ;
     RECT  49.872 3.925 49.896 34.741 ;
     RECT  21.12 33.829 22.056 34.789 ;
     RECT  24 33.685 27.432 34.789 ;
     RECT  49.584 34.741 49.896 34.835 ;
     RECT  42.288 34.403 47.112 34.883 ;
     RECT  20.976 34.789 22.056 34.931 ;
     RECT  29.136 34.163 30.312 34.931 ;
     RECT  36.576 34.549 37.464 34.931 ;
     RECT  38.592 33.973 41.112 34.979 ;
     RECT  48.24 34.741 48.264 35.075 ;
     RECT  21.648 34.931 22.056 35.077 ;
     RECT  31.728 34.163 31.752 35.125 ;
     RECT  38.592 34.979 40.92 35.171 ;
     RECT  13.2 34.211 13.608 35.173 ;
     RECT  29.136 34.931 30.264 35.173 ;
     RECT  15.984 34.595 16.008 35.219 ;
     RECT  21.648 35.077 22.584 35.269 ;
     RECT  23.904 34.789 27.432 35.269 ;
     RECT  42.288 34.883 46.68 35.363 ;
     RECT  49.584 34.835 49.608 35.363 ;
     RECT  52.752 33.397 52.776 35.363 ;
     RECT  21.648 35.269 27.432 35.411 ;
     RECT  31.584 35.125 31.752 35.411 ;
     RECT  29.088 35.173 30.264 35.459 ;
     RECT  17.136 35.317 17.16 35.507 ;
     RECT  34.8 34.259 35.256 35.509 ;
     RECT  29.088 35.459 30.168 35.651 ;
     RECT  51 33.587 51.312 35.797 ;
     RECT  29.088 35.651 29.928 35.893 ;
     RECT  13.104 35.173 13.608 35.939 ;
     RECT  42.288 35.363 44.616 35.939 ;
     RECT  50.688 35.797 51.312 35.939 ;
     RECT  18.432 34.307 19.08 35.941 ;
     RECT  38.592 35.171 38.76 35.987 ;
     RECT  36.576 34.931 37.368 36.035 ;
     RECT  40.2 35.171 40.92 36.179 ;
     RECT  34.8 35.509 35.352 36.181 ;
     RECT  36.576 36.035 36.6 36.181 ;
     RECT  21.648 35.411 26.808 36.229 ;
     RECT  18.432 35.941 19.368 36.275 ;
     RECT  43.584 35.939 44.616 36.421 ;
     RECT  45.6 35.363 46.68 36.421 ;
     RECT  21.12 36.229 26.808 36.467 ;
     RECT  34.416 36.181 36.6 36.469 ;
     RECT  21.936 36.467 26.808 36.515 ;
     RECT  28.56 35.893 29.928 36.515 ;
     RECT  43.584 36.421 46.68 36.515 ;
     RECT  45.264 36.515 45.912 36.563 ;
     RECT  43.584 36.515 43.896 36.659 ;
     RECT  42.288 35.939 42.456 36.707 ;
     RECT  24 36.515 26.808 36.757 ;
     RECT  24 36.757 27.432 36.851 ;
     RECT  13.104 35.939 13.512 36.997 ;
     RECT  18.432 36.275 18.912 37.043 ;
     RECT  24 36.851 24.456 37.043 ;
     RECT  25.488 36.851 27.432 37.043 ;
     RECT  48.48 36.757 48.504 37.043 ;
     RECT  42.336 36.707 42.456 37.139 ;
     RECT  21.936 36.515 22.584 37.283 ;
     RECT  28.56 36.515 29.832 37.283 ;
     RECT  43.872 36.659 43.896 37.283 ;
     RECT  20.112 37.189 20.136 37.379 ;
     RECT  28.56 37.283 29.712 37.379 ;
     RECT  31.728 35.411 31.752 37.379 ;
     RECT  17.28 37.093 17.304 37.477 ;
     RECT  11.088 34.741 11.112 37.667 ;
     RECT  22.176 37.283 22.584 37.667 ;
     RECT  25.872 37.043 26.808 37.667 ;
     RECT  54.192 35.317 54.216 37.667 ;
     RECT  24 37.043 24.312 37.669 ;
     RECT  33.456 36.469 36.6 37.669 ;
     RECT  33.168 37.669 36.6 37.715 ;
     RECT  25.872 37.667 25.896 37.811 ;
     RECT  33.168 37.715 35.4 37.811 ;
     RECT  36.576 37.715 36.6 37.811 ;
     RECT  16.08 37.045 16.104 37.909 ;
     RECT  22.56 37.667 22.584 38.051 ;
     RECT  33.456 37.811 35.4 38.051 ;
     RECT  49.536 36.661 49.56 38.051 ;
     RECT  51 35.939 51.312 38.245 ;
     RECT  29.28 37.379 29.712 38.341 ;
     RECT  42.336 37.139 42.36 38.387 ;
     RECT  23.904 37.669 24.312 38.437 ;
     RECT  40.2 36.179 40.728 38.437 ;
     RECT  51 38.245 51.432 38.437 ;
     RECT  15.984 37.909 16.104 38.533 ;
     RECT  17.28 37.477 17.4 38.533 ;
     RECT  51 38.437 51.912 38.533 ;
     RECT  51 38.533 52.44 38.581 ;
     RECT  23.904 38.437 24.408 38.629 ;
     RECT  40.2 38.437 40.824 38.629 ;
     RECT  12.24 36.997 13.512 38.677 ;
     RECT  15.888 38.533 17.4 38.677 ;
     RECT  18.48 37.043 18.912 38.677 ;
     RECT  23.472 38.629 24.408 38.677 ;
     RECT  25.584 38.485 25.752 38.677 ;
     RECT  27.984 38.341 29.712 38.677 ;
     RECT  33.888 38.051 35.4 38.677 ;
     RECT  38.736 38.053 38.76 38.677 ;
     RECT  40.08 38.629 40.824 38.677 ;
     RECT  48.192 38.629 48.216 38.677 ;
     RECT  51 38.581 53.208 38.677 ;
     RECT  56.4 2.195 56.712 38.677 ;
     RECT  10.032 38.677 10.056 38.725 ;
     RECT  11.76 38.677 13.512 38.725 ;
     RECT  55.824 38.677 56.712 38.725 ;
     RECT  45.6 36.563 45.912 38.965 ;
     RECT  47.232 38.677 48.696 38.965 ;
     RECT  9.216 38.725 14.424 39.013 ;
     RECT  55.44 38.725 56.904 39.013 ;
     RECT  32.16 38.677 32.184 39.109 ;
     RECT  38.736 38.677 41.784 39.109 ;
     RECT  9.216 39.013 14.568 39.253 ;
     RECT  15.6 38.677 18.912 39.253 ;
     RECT  23.472 38.677 25.752 39.253 ;
     RECT  32.16 39.109 32.232 39.253 ;
     RECT  23.376 39.253 25.752 39.301 ;
     RECT  43.632 38.821 43.656 39.301 ;
     RECT  49.776 38.677 53.208 39.301 ;
     RECT  54.432 38.677 54.456 39.301 ;
     RECT  55.44 39.013 57 39.301 ;
     RECT  27.648 38.677 30.84 39.397 ;
     RECT  32.016 39.253 32.232 39.397 ;
     RECT  33.888 38.677 36.024 39.397 ;
     RECT  22.704 39.301 25.752 39.493 ;
     RECT  33.264 39.397 36.024 39.925 ;
     RECT  43.248 39.301 43.656 39.925 ;
     RECT  42.768 39.925 43.656 40.405 ;
     RECT  7.8 3.443 8.112 40.453 ;
     RECT  9.216 39.253 19.944 40.453 ;
     RECT  20.976 39.109 21 40.453 ;
     RECT  22.704 39.493 26.472 40.453 ;
     RECT  27.648 39.397 32.232 40.453 ;
     RECT  33.264 39.925 36.552 40.453 ;
     RECT  38.256 39.109 41.784 40.453 ;
     RECT  42.768 40.405 44.04 40.453 ;
     RECT  45.6 38.965 48.696 40.453 ;
     RECT  49.776 39.301 54.456 40.453 ;
     RECT  55.44 39.301 57.48 40.453 ;
     RECT  7.344 40.453 44.04 40.789 ;
     RECT  45.6 40.453 54.456 40.789 ;
     RECT  55.44 40.453 57.768 40.789 ;
     RECT  7.344 40.789 44.424 40.981 ;
     RECT  45.6 40.789 57.768 40.981 ;
     RECT  2.4 2.151 2.712 41.049 ;
     RECT  61.8 2.151 62.112 41.049 ;
     RECT  2.4 41.049 2.52 41.063 ;
     RECT  61.8 41.049 61.92 41.063 ;
     RECT  7.248 40.981 57.864 43.152 ;
     RECT  19.128 0.131 19.872 0.132 ;
     RECT  19.08 0.132 20.112 1.187 ;
     RECT  18.888 1.187 20.112 1.715 ;
     RECT  18.888 1.715 20.304 2.151 ;
     RECT  38.184 1.715 39.216 1.763 ;
     RECT  38.184 1.763 39.312 1.811 ;
     RECT  15.912 1.811 17.328 2.195 ;
     RECT  38.184 1.811 39.504 2.915 ;
     RECT  35.496 1.859 36.528 2.915 ;
     RECT  18.912 2.151 20.304 2.339 ;
     RECT  20.52 2.195 21.552 2.339 ;
     RECT  55.272 2.195 56.4 2.963 ;
     RECT  11.4 2.243 12.912 2.291 ;
     RECT  31.752 2.291 32.784 5.171 ;
     RECT  47.976 2.291 49.296 3.443 ;
     RECT  54.216 2.291 55.248 2.963 ;
     RECT  18.912 2.339 20.4 3.443 ;
     RECT  20.52 2.339 21.84 2.387 ;
     RECT  20.424 2.387 21.84 2.915 ;
     RECT  20.424 2.915 21.936 3.443 ;
     RECT  26.712 2.915 27.696 3.251 ;
     RECT  35.496 2.915 36.624 2.963 ;
     RECT  37.512 2.915 39.6 3.107 ;
     RECT  28.2 2.963 29.184 3.443 ;
     RECT  30.264 2.963 31.248 4.453 ;
     RECT  35.496 2.963 36.912 3.203 ;
     RECT  43.608 2.963 44.592 8.773 ;
     RECT  37.416 3.107 39.6 4.117 ;
     RECT  26.664 3.251 27.696 4.405 ;
     RECT  8.112 3.443 9.552 5.171 ;
     RECT  27.72 3.443 29.184 4.213 ;
     RECT  41.112 3.443 42.624 4.453 ;
     RECT  22.248 3.827 23.28 4.595 ;
     RECT  49.896 3.925 51 32.437 ;
     RECT  52.872 4.115 54.192 6.323 ;
     RECT  37.416 4.117 38.592 5.989 ;
     RECT  38.616 4.117 39.6 4.165 ;
     RECT  27.72 4.213 29.088 4.693 ;
     RECT  41.112 4.453 42.336 5.221 ;
     RECT  21.96 4.595 23.28 5.843 ;
     RECT  30.312 4.595 31.728 34.021 ;
     RECT  27.72 4.693 29.04 6.323 ;
     RECT  31.752 5.171 32.832 32.675 ;
     RECT  41.112 5.221 42.288 33.013 ;
     RECT  33.48 5.987 34.656 6.083 ;
     RECT  33.48 6.083 34.8 6.899 ;
     RECT  37.416 6.179 38.592 32.147 ;
     RECT  24.408 6.323 25.488 33.061 ;
     RECT  46.104 18.469 47.088 21.397 ;
     RECT  38.76 28.211 39.84 30.803 ;
     RECT  38.76 30.803 39.888 32.675 ;
     RECT  37.368 32.147 38.592 33.301 ;
     RECT  49.896 32.437 50.88 33.587 ;
     RECT  31.752 32.675 32.136 32.917 ;
     RECT  38.76 32.675 40.2 33.973 ;
     RECT  41.112 33.013 42.192 34.403 ;
     RECT  24.504 33.061 25.488 33.109 ;
     RECT  15.384 33.301 16.512 33.781 ;
     RECT  37.464 33.301 38.592 33.541 ;
     RECT  51.312 33.397 52.752 35.363 ;
     RECT  37.512 33.541 38.592 34.307 ;
     RECT  49.896 33.587 51 34.835 ;
     RECT  30.312 34.163 31.728 34.931 ;
     RECT  13.104 34.211 13.2 35.173 ;
     RECT  35.256 34.259 35.4 34.549 ;
     RECT  37.464 34.307 38.592 34.931 ;
     RECT  41.112 34.403 42.288 34.979 ;
     RECT  35.256 34.549 36.576 35.509 ;
     RECT  47.112 34.741 48.24 34.883 ;
     RECT  48.264 34.741 49.584 35.075 ;
     RECT  49.608 34.835 51 35.363 ;
     RECT  21.12 34.931 21.648 36.229 ;
     RECT  30.264 34.931 31.728 35.125 ;
     RECT  37.368 34.931 38.592 35.987 ;
     RECT  40.92 34.979 42.288 36.179 ;
     RECT  22.584 35.077 23.904 35.269 ;
     RECT  30.264 35.125 31.584 35.411 ;
     RECT  38.76 35.171 40.2 35.987 ;
     RECT  17.16 35.317 18.432 35.507 ;
     RECT  52.776 35.317 54.192 35.363 ;
     RECT  44.616 35.363 45.6 36.421 ;
     RECT  49.584 35.363 51 35.797 ;
     RECT  26.808 35.411 27.432 35.893 ;
     RECT  30.264 35.411 31.728 35.459 ;
     RECT  35.352 35.509 36.576 36.181 ;
     RECT  49.584 35.797 50.688 35.939 ;
     RECT  26.808 35.893 28.56 36.757 ;
     RECT  42.456 35.939 43.584 36.659 ;
     RECT  49.584 35.939 51 36.661 ;
     RECT  18.912 36.275 19.368 37.189 ;
     RECT  22.584 36.515 24 37.669 ;
     RECT  43.896 36.515 45.264 36.563 ;
     RECT  42.456 36.659 43.872 37.139 ;
     RECT  49.56 36.661 51 38.051 ;
     RECT  27.432 36.757 28.56 37.043 ;
     RECT  48.504 36.757 49.536 37.043 ;
     RECT  24.456 36.851 25.488 37.043 ;
     RECT  11.112 36.997 12.24 37.667 ;
     RECT  18.432 37.043 18.48 37.093 ;
     RECT  24.312 37.043 25.872 37.811 ;
     RECT  26.808 37.043 28.56 37.379 ;
     RECT  16.104 37.093 17.28 38.533 ;
     RECT  17.304 37.093 18.48 37.477 ;
     RECT  42.36 37.139 43.872 37.283 ;
     RECT  18.912 37.189 20.112 37.379 ;
     RECT  29.712 37.283 29.832 38.677 ;
     RECT  26.808 37.379 29.28 37.667 ;
     RECT  31.728 37.379 31.752 37.669 ;
     RECT  17.4 37.477 18.48 38.677 ;
     RECT  11.088 37.667 12.24 38.677 ;
     RECT  27.648 37.667 29.28 38.341 ;
     RECT  54.192 37.667 54.216 38.581 ;
     RECT  22.584 37.669 23.904 38.051 ;
     RECT  31.728 37.669 33.168 37.811 ;
     RECT  35.4 37.715 36.576 37.811 ;
     RECT  24.312 37.811 25.752 38.437 ;
     RECT  31.728 37.811 33.456 38.051 ;
     RECT  35.4 37.811 36.024 38.677 ;
     RECT  22.704 38.051 23.904 38.629 ;
     RECT  31.728 38.051 33.888 38.677 ;
     RECT  49.536 38.051 51 38.629 ;
     RECT  38.76 38.053 40.2 38.629 ;
     RECT  27.648 38.341 27.984 38.677 ;
     RECT  42.336 38.387 42.36 38.437 ;
     RECT  24.408 38.437 25.752 38.485 ;
     RECT  40.824 38.437 42.36 38.677 ;
     RECT  24.408 38.485 25.584 38.677 ;
     RECT  53.208 38.581 54.216 38.677 ;
     RECT  22.704 38.629 23.472 39.253 ;
     RECT  38.76 38.629 40.08 38.677 ;
     RECT  48.216 38.629 51 38.677 ;
     RECT  10.056 38.677 11.76 38.725 ;
     RECT  30.84 38.677 32.16 39.253 ;
     RECT  32.184 38.677 33.888 39.109 ;
     RECT  41.784 38.677 42.36 38.821 ;
     RECT  45.912 38.677 47.232 38.965 ;
     RECT  48.696 38.677 49.776 40.453 ;
     RECT  53.208 38.677 54.432 39.301 ;
     RECT  54.456 38.677 55.824 38.725 ;
     RECT  8.112 38.725 9.216 40.453 ;
     RECT  14.424 38.725 15.6 39.013 ;
     RECT  54.456 38.725 55.44 40.789 ;
     RECT  41.784 38.821 43.632 39.301 ;
     RECT  14.568 39.013 15.6 39.253 ;
     RECT  32.232 39.109 33.888 39.397 ;
     RECT  19.944 39.253 20.976 40.453 ;
     RECT  22.704 39.253 23.376 39.301 ;
     RECT  30.84 39.253 32.016 39.397 ;
     RECT  41.784 39.301 43.248 39.925 ;
     RECT  32.232 39.397 33.264 40.453 ;
     RECT  26.472 39.493 27.648 40.453 ;
     RECT  41.784 39.925 42.768 40.453 ;
     RECT  44.424 40.789 45.6 40.981 ;
  END
END ot_hgi_b2_dma_groupface
END LIBRARY
